# Confidential Information of ARM, Inc.
# Use subject to ARM license.
# Copyright (c) 2022 ARM, Inc.

# ACI Version r1p1

# Reifier 4.0.0

VERSION 5.7 ;

BUSBITCHARS "[]" ;

#name: High Density Single Port Register File RVT RVT Compiler | LOGIC0040LL 40nm Process 0.299um^2 Bit Cell
#version: r1p1
#comment: This is a memory instance
#configuration:  -activity_factor 50 -back_biasing off -bits 16 -bmux off -bus_notation on -check_instname on -diodes on -drive 6 -ema on -frequency 1.0 -instname RAMSP128X16 -left_bus_delim "[" -mux 2 -mvt "" -name_case upper -power_type otc -prefix "" -pwr_gnd_rename vddpe:VDDPE,vddce:VDDCE,vsse:VSSE -retention on -right_bus_delim "]" -ser none -site_def off -top_layer m5-m10 -words 128 -write_mask on -write_thru off -corners ff_1p10v_1p10v_0c,ff_1p10v_1p10v_125c,ff_1p10v_1p10v_m40c,ff_1p21v_1p21v_0c,ff_1p21v_1p21v_125c,ff_1p21v_1p21v_m40c,ff_1p26v_1p26v_0c,ff_1p26v_1p26v_125c,ff_1p26v_1p26v_85c,ff_1p26v_1p26v_m40c,ss_0p90v_0p90v_0c,ss_0p90v_0p90v_125c,ss_0p90v_0p90v_m40c,ss_0p99v_0p99v_0c,ss_0p99v_0p99v_125c,ss_0p99v_0p99v_m40c,ss_1p08v_1p08v_0c,ss_1p08v_1p08v_125c,ss_1p08v_1p08v_m40c,tt_1p00v_1p00v_125c,tt_1p00v_1p00v_25c,tt_1p00v_1p00v_85c,tt_1p10v_1p10v_125c,tt_1p10v_1p10v_25c,tt_1p10v_1p10v_85c,tt_1p20v_1p20v_125c,tt_1p20v_1p20v_25c,tt_1p20v_1p20v_85c
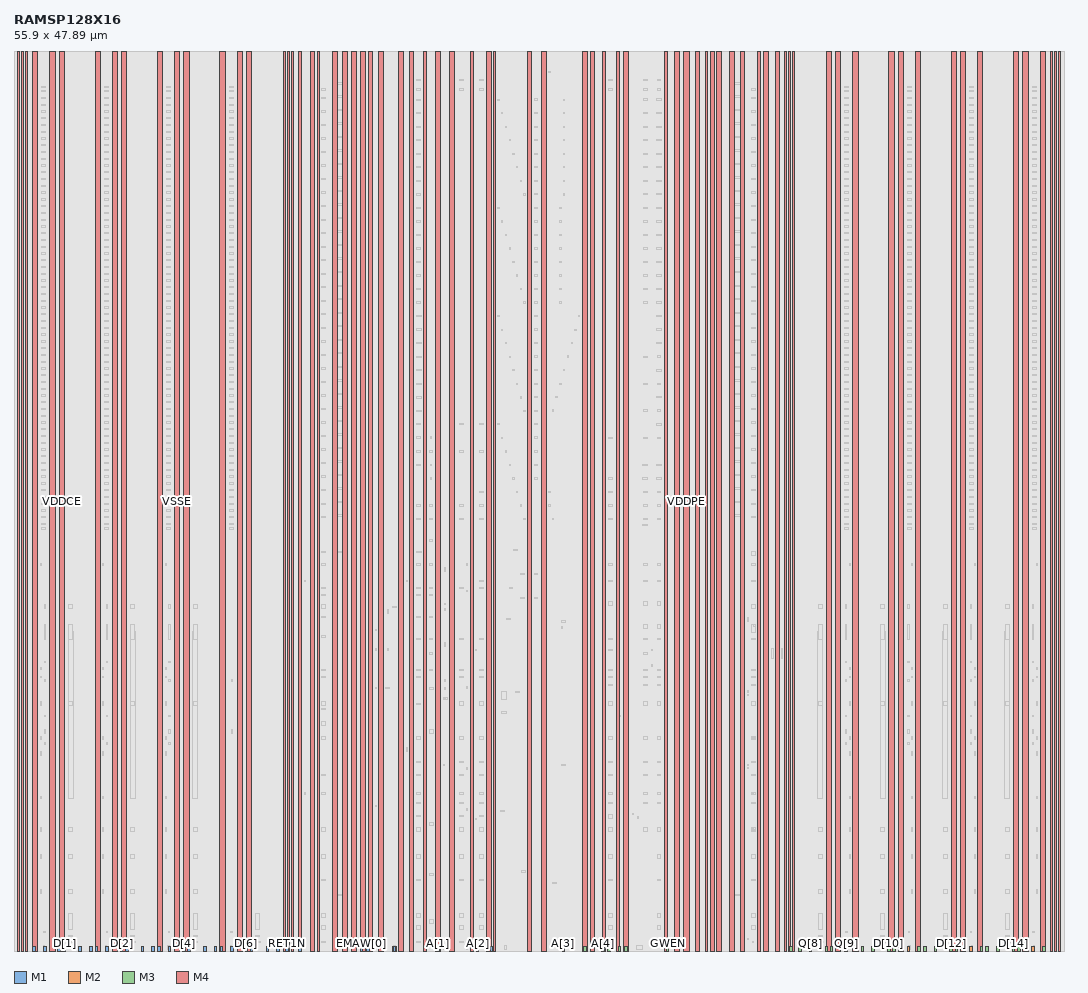
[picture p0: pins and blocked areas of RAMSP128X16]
MACRO RAMSP128X16
  FOREIGN RAMSP128X16 0 0 ;
  SYMMETRY X Y R90 ;
  SIZE 55.9 BY 47.89 ;
  CLASS BLOCK ;
  PIN A[3]
    DIRECTION INPUT ;
    USE SIGNAL ;
    SHAPE ABUTMENT ;
    PORT
      LAYER M1 ;
      RECT 29.175 0.0 29.315 0.25 ;
      LAYER M2 ;
      RECT 29.175 0.0 29.315 0.25 ;
      LAYER M3 ;
      RECT 29.175 0.0 29.315 0.25 ;
      END
    ANTENNAGATEAREA 0.0114 ;
    ANTENNADIFFAREA 0.035 ;
    END A[3]
  PIN A[5]
    DIRECTION INPUT ;
    USE SIGNAL ;
    SHAPE ABUTMENT ;
    PORT
      LAYER M3 ;
      RECT 25.345 0.0 25.485 0.25 ;
      LAYER M2 ;
      RECT 25.345 0.0 25.485 0.25 ;
      LAYER M1 ;
      RECT 25.345 0.0 25.485 0.25 ;
      END
    ANTENNAGATEAREA 0.0114 ;
    ANTENNADIFFAREA 0.035 ;
    END A[5]
  PIN EMA[0]
    DIRECTION INPUT ;
    USE SIGNAL ;
    SHAPE ABUTMENT ;
    PORT
      LAYER M1 ;
      RECT 30.33 0.0 30.47 0.25 ;
      LAYER M2 ;
      RECT 30.33 0.0 30.47 0.25 ;
      LAYER M3 ;
      RECT 30.33 0.0 30.47 0.25 ;
      END
    ANTENNAGATEAREA 0.0114 ;
    ANTENNADIFFAREA 0.035 ;
    END EMA[0]
  PIN A[2]
    DIRECTION INPUT ;
    USE SIGNAL ;
    SHAPE ABUTMENT ;
    PORT
      LAYER M3 ;
      RECT 24.615 0.0 24.755 0.25 ;
      LAYER M2 ;
      RECT 24.615 0.0 24.755 0.25 ;
      LAYER M1 ;
      RECT 24.615 0.0 24.755 0.25 ;
      END
    ANTENNAGATEAREA 0.0114 ;
    ANTENNADIFFAREA 0.035 ;
    END A[2]
  PIN A[4]
    DIRECTION INPUT ;
    USE SIGNAL ;
    SHAPE ABUTMENT ;
    PORT
      LAYER M1 ;
      RECT 31.29 0.0 31.43 0.25 ;
      LAYER M2 ;
      RECT 31.29 0.0 31.43 0.25 ;
      LAYER M3 ;
      RECT 31.29 0.0 31.43 0.25 ;
      END
    ANTENNAGATEAREA 0.0114 ;
    ANTENNADIFFAREA 0.035 ;
    END A[4]
  PIN A[1]
    DIRECTION INPUT ;
    USE SIGNAL ;
    SHAPE ABUTMENT ;
    PORT
      LAYER M3 ;
      RECT 22.52 0.0 22.66 0.25 ;
      LAYER M2 ;
      RECT 22.52 0.0 22.66 0.25 ;
      LAYER M1 ;
      RECT 22.52 0.0 22.66 0.25 ;
      END
    ANTENNAGATEAREA 0.0114 ;
    ANTENNADIFFAREA 0.035 ;
    END A[1]
  PIN A[6]
    DIRECTION INPUT ;
    USE SIGNAL ;
    SHAPE ABUTMENT ;
    PORT
      LAYER M1 ;
      RECT 31.595 0.0 31.735 0.25 ;
      LAYER M2 ;
      RECT 31.595 0.0 31.735 0.25 ;
      LAYER M3 ;
      RECT 31.595 0.0 31.735 0.25 ;
      END
    ANTENNAGATEAREA 0.0114 ;
    ANTENNADIFFAREA 0.035 ;
    END A[6]
  PIN CLK
    DIRECTION INPUT ;
    USE SIGNAL ;
    SHAPE ABUTMENT ;
    PORT
      LAYER M3 ;
      RECT 20.18 0.0 20.32 0.25 ;
      LAYER M2 ;
      RECT 20.18 0.0 20.32 0.25 ;
      LAYER M1 ;
      RECT 20.18 0.0 20.32 0.25 ;
      LAYER M4 ;
      RECT 20.14 0.0 20.35 0.25 ;
      END
    ANTENNAGATEAREA 0.0114 ;
    ANTENNADIFFAREA 0.035 ;
    END CLK
  PIN EMA[1]
    DIRECTION INPUT ;
    USE SIGNAL ;
    SHAPE ABUTMENT ;
    PORT
      LAYER M1 ;
      RECT 32.16 0.0 32.3 0.25 ;
      LAYER M2 ;
      RECT 32.16 0.0 32.3 0.25 ;
      LAYER M3 ;
      RECT 32.16 0.0 32.3 0.25 ;
      END
    ANTENNAGATEAREA 0.0114 ;
    ANTENNADIFFAREA 0.035 ;
    END EMA[1]
  PIN EMAW[1]
    DIRECTION INPUT ;
    USE SIGNAL ;
    SHAPE ABUTMENT ;
    PORT
      LAYER M3 ;
      RECT 18.785 0.0 18.925 0.25 ;
      LAYER M2 ;
      RECT 18.785 0.0 18.925 0.25 ;
      LAYER M1 ;
      RECT 18.785 0.0 18.925 0.25 ;
      END
    ANTENNAGATEAREA 0.0114 ;
    ANTENNADIFFAREA 0.035 ;
    END EMAW[1]
  PIN EMA[2]
    DIRECTION INPUT ;
    USE SIGNAL ;
    SHAPE ABUTMENT ;
    PORT
      LAYER M1 ;
      RECT 32.51 0.0 32.65 0.25 ;
      LAYER M2 ;
      RECT 32.51 0.0 32.65 0.25 ;
      LAYER M3 ;
      RECT 32.51 0.0 32.65 0.25 ;
      END
    ANTENNAGATEAREA 0.0114 ;
    ANTENNADIFFAREA 0.035 ;
    END EMA[2]
  PIN EMAW[0]
    DIRECTION INPUT ;
    USE SIGNAL ;
    SHAPE ABUTMENT ;
    PORT
      LAYER M3 ;
      RECT 18.43 0.0 18.57 0.25 ;
      LAYER M2 ;
      RECT 18.43 0.0 18.57 0.25 ;
      LAYER M1 ;
      RECT 18.43 0.0 18.57 0.25 ;
      END
    ANTENNAGATEAREA 0.0114 ;
    ANTENNADIFFAREA 0.035 ;
    END EMAW[0]
  PIN GWEN
    DIRECTION INPUT ;
    USE SIGNAL ;
    SHAPE ABUTMENT ;
    PORT
      LAYER M1 ;
      RECT 34.73 0.0 34.87 0.25 ;
      LAYER M2 ;
      RECT 34.73 0.0 34.87 0.25 ;
      LAYER M3 ;
      RECT 34.73 0.0 34.87 0.25 ;
      END
    ANTENNAGATEAREA 0.0114 ;
    ANTENNADIFFAREA 0.035 ;
    END GWEN
  PIN CEN
    DIRECTION INPUT ;
    USE SIGNAL ;
    SHAPE ABUTMENT ;
    PORT
      LAYER M3 ;
      RECT 15.17 0.0 15.31 0.25 ;
      LAYER M2 ;
      RECT 15.17 0.0 15.31 0.25 ;
      LAYER M1 ;
      RECT 15.17 0.0 15.31 0.25 ;
      END
    ANTENNAGATEAREA 0.0114 ;
    ANTENNADIFFAREA 0.035 ;
    END CEN
  PIN A[0]
    DIRECTION INPUT ;
    USE SIGNAL ;
    SHAPE ABUTMENT ;
    PORT
      LAYER M1 ;
      RECT 41.28 0.0 41.42 0.25 ;
      LAYER M2 ;
      RECT 41.28 0.0 41.42 0.25 ;
      LAYER M3 ;
      RECT 41.28 0.0 41.42 0.25 ;
      END
    ANTENNAGATEAREA 0.0114 ;
    ANTENNADIFFAREA 0.035 ;
    END A[0]
  PIN RET1N
    DIRECTION INPUT ;
    USE SIGNAL ;
    SHAPE ABUTMENT ;
    PORT
      LAYER M3 ;
      RECT 14.47 0.0 14.61 0.25 ;
      LAYER M2 ;
      RECT 14.47 0.0 14.61 0.25 ;
      LAYER M1 ;
      RECT 14.47 0.0 14.61 0.25 ;
      END
    ANTENNAGATEAREA 0.0114 ;
    ANTENNADIFFAREA 0.035 ;
    END RET1N
  PIN WEN[8]
    DIRECTION INPUT ;
    USE SIGNAL ;
    SHAPE ABUTMENT ;
    PORT
      LAYER M1 ;
      RECT 41.78 0.0 41.92 0.25 ;
      LAYER M2 ;
      RECT 41.78 0.0 41.92 0.25 ;
      LAYER M3 ;
      RECT 41.78 0.0 41.92 0.25 ;
      END
    ANTENNAGATEAREA 0.0114 ;
    ANTENNADIFFAREA 0.035 ;
    END WEN[8]
  PIN WEN[7]
    DIRECTION INPUT ;
    USE SIGNAL ;
    SHAPE ABUTMENT ;
    PORT
      LAYER M3 ;
      RECT 13.98 0.0 14.12 0.25 ;
      LAYER M2 ;
      RECT 13.98 0.0 14.12 0.25 ;
      LAYER M1 ;
      RECT 13.98 0.0 14.12 0.25 ;
      END
    ANTENNAGATEAREA 0.0114 ;
    ANTENNADIFFAREA 0.035 ;
    END WEN[7]
  PIN Q[8]
    DIRECTION OUTPUT ;
    USE SIGNAL ;
    SHAPE ABUTMENT ;
    PORT
      LAYER M1 ;
      RECT 42.34 0.0 42.48 0.25 ;
      LAYER M2 ;
      RECT 42.34 0.0 42.48 0.25 ;
      LAYER M3 ;
      RECT 42.34 0.0 42.48 0.25 ;
      END
    ANTENNADIFFAREA 0.035 ;
    END Q[8]
  PIN Q[7]
    DIRECTION OUTPUT ;
    USE SIGNAL ;
    SHAPE ABUTMENT ;
    PORT
      LAYER M3 ;
      RECT 13.42 0.0 13.56 0.25 ;
      LAYER M2 ;
      RECT 13.42 0.0 13.56 0.25 ;
      LAYER M1 ;
      RECT 13.42 0.0 13.56 0.25 ;
      END
    ANTENNADIFFAREA 0.035 ;
    END Q[7]
  PIN D[8]
    DIRECTION INPUT ;
    USE SIGNAL ;
    SHAPE ABUTMENT ;
    PORT
      LAYER M1 ;
      RECT 43.18 0.0 43.32 0.25 ;
      LAYER M2 ;
      RECT 43.18 0.0 43.32 0.25 ;
      LAYER M3 ;
      RECT 43.18 0.0 43.32 0.25 ;
      END
    ANTENNAGATEAREA 0.0114 ;
    ANTENNADIFFAREA 0.035 ;
    END D[8]
  PIN D[7]
    DIRECTION INPUT ;
    USE SIGNAL ;
    SHAPE ABUTMENT ;
    PORT
      LAYER M3 ;
      RECT 12.58 0.0 12.72 0.25 ;
      LAYER M2 ;
      RECT 12.58 0.0 12.72 0.25 ;
      LAYER M1 ;
      RECT 12.58 0.0 12.72 0.25 ;
      END
    ANTENNAGATEAREA 0.0114 ;
    ANTENNADIFFAREA 0.035 ;
    END D[7]
  PIN D[9]
    DIRECTION INPUT ;
    USE SIGNAL ;
    SHAPE ABUTMENT ;
    PORT
      LAYER M1 ;
      RECT 43.46 0.0 43.6 0.25 ;
      LAYER M2 ;
      RECT 43.46 0.0 43.6 0.25 ;
      LAYER M3 ;
      RECT 43.46 0.0 43.6 0.25 ;
      END
    ANTENNAGATEAREA 0.0114 ;
    ANTENNADIFFAREA 0.035 ;
    END D[9]
  PIN D[6]
    DIRECTION INPUT ;
    USE SIGNAL ;
    SHAPE ABUTMENT ;
    PORT
      LAYER M3 ;
      RECT 12.3 0.0 12.44 0.25 ;
      LAYER M2 ;
      RECT 12.3 0.0 12.44 0.25 ;
      LAYER M1 ;
      RECT 12.3 0.0 12.44 0.25 ;
      END
    ANTENNAGATEAREA 0.0114 ;
    ANTENNADIFFAREA 0.035 ;
    END D[6]
  PIN Q[9]
    DIRECTION OUTPUT ;
    USE SIGNAL ;
    SHAPE ABUTMENT ;
    PORT
      LAYER M1 ;
      RECT 44.23 0.0 44.37 0.25 ;
      LAYER M2 ;
      RECT 44.23 0.0 44.37 0.25 ;
      END
    ANTENNADIFFAREA 0.035 ;
    END Q[9]
  PIN Q[6]
    DIRECTION OUTPUT ;
    USE SIGNAL ;
    SHAPE ABUTMENT ;
    PORT
      LAYER M2 ;
      RECT 11.53 0.0 11.67 0.25 ;
      LAYER M1 ;
      RECT 11.53 0.0 11.67 0.25 ;
      END
    ANTENNADIFFAREA 0.035 ;
    END Q[6]
  PIN WEN[9]
    DIRECTION INPUT ;
    USE SIGNAL ;
    SHAPE ABUTMENT ;
    PORT
      LAYER M1 ;
      RECT 44.79 0.0 44.93 0.25 ;
      LAYER M2 ;
      RECT 44.79 0.0 44.93 0.25 ;
      LAYER M3 ;
      RECT 44.79 0.0 44.93 0.25 ;
      END
    ANTENNAGATEAREA 0.0114 ;
    ANTENNADIFFAREA 0.035 ;
    END WEN[9]
  PIN WEN[6]
    DIRECTION INPUT ;
    USE SIGNAL ;
    SHAPE ABUTMENT ;
    PORT
      LAYER M3 ;
      RECT 10.97 0.0 11.11 0.25 ;
      LAYER M2 ;
      RECT 10.97 0.0 11.11 0.25 ;
      LAYER M1 ;
      RECT 10.97 0.0 11.11 0.25 ;
      END
    ANTENNAGATEAREA 0.0114 ;
    ANTENNADIFFAREA 0.035 ;
    END WEN[6]
  PIN WEN[10]
    DIRECTION INPUT ;
    USE SIGNAL ;
    SHAPE ABUTMENT ;
    PORT
      LAYER M1 ;
      RECT 45.1 0.0 45.24 0.25 ;
      LAYER M2 ;
      RECT 45.1 0.0 45.24 0.25 ;
      LAYER M3 ;
      RECT 45.1 0.0 45.24 0.25 ;
      END
    ANTENNAGATEAREA 0.0114 ;
    ANTENNADIFFAREA 0.035 ;
    END WEN[10]
  PIN WEN[5]
    DIRECTION INPUT ;
    USE SIGNAL ;
    SHAPE ABUTMENT ;
    PORT
      LAYER M3 ;
      RECT 10.66 0.0 10.8 0.25 ;
      LAYER M2 ;
      RECT 10.66 0.0 10.8 0.25 ;
      LAYER M1 ;
      RECT 10.66 0.0 10.8 0.25 ;
      END
    ANTENNAGATEAREA 0.0114 ;
    ANTENNADIFFAREA 0.035 ;
    END WEN[5]
  PIN Q[10]
    DIRECTION OUTPUT ;
    USE SIGNAL ;
    SHAPE ABUTMENT ;
    PORT
      LAYER M1 ;
      RECT 45.66 0.0 45.8 0.25 ;
      LAYER M2 ;
      RECT 45.66 0.0 45.8 0.25 ;
      LAYER M3 ;
      RECT 45.66 0.0 45.8 0.25 ;
      END
    ANTENNADIFFAREA 0.035 ;
    END Q[10]
  PIN Q[5]
    DIRECTION OUTPUT ;
    USE SIGNAL ;
    SHAPE ABUTMENT ;
    PORT
      LAYER M3 ;
      RECT 10.1 0.0 10.24 0.25 ;
      LAYER M2 ;
      RECT 10.1 0.0 10.24 0.25 ;
      LAYER M1 ;
      RECT 10.1 0.0 10.24 0.25 ;
      END
    ANTENNADIFFAREA 0.035 ;
    END Q[5]
  PIN D[10]
    DIRECTION INPUT ;
    USE SIGNAL ;
    SHAPE ABUTMENT ;
    PORT
      LAYER M1 ;
      RECT 46.5 0.0 46.64 0.25 ;
      LAYER M2 ;
      RECT 46.5 0.0 46.64 0.25 ;
      LAYER M3 ;
      RECT 46.5 0.0 46.64 0.25 ;
      END
    ANTENNAGATEAREA 0.0114 ;
    ANTENNADIFFAREA 0.035 ;
    END D[10]
  PIN D[5]
    DIRECTION INPUT ;
    USE SIGNAL ;
    SHAPE ABUTMENT ;
    PORT
      LAYER M3 ;
      RECT 9.26 0.0 9.4 0.25 ;
      LAYER M2 ;
      RECT 9.26 0.0 9.4 0.25 ;
      LAYER M1 ;
      RECT 9.26 0.0 9.4 0.25 ;
      END
    ANTENNAGATEAREA 0.0114 ;
    ANTENNADIFFAREA 0.035 ;
    END D[5]
  PIN D[11]
    DIRECTION INPUT ;
    USE SIGNAL ;
    SHAPE ABUTMENT ;
    PORT
      LAYER M1 ;
      RECT 46.78 0.0 46.92 0.25 ;
      LAYER M2 ;
      RECT 46.78 0.0 46.92 0.25 ;
      LAYER M3 ;
      RECT 46.78 0.0 46.92 0.25 ;
      END
    ANTENNAGATEAREA 0.0114 ;
    ANTENNADIFFAREA 0.035 ;
    END D[11]
  PIN D[4]
    DIRECTION INPUT ;
    USE SIGNAL ;
    SHAPE ABUTMENT ;
    PORT
      LAYER M3 ;
      RECT 8.98 0.0 9.12 0.25 ;
      LAYER M2 ;
      RECT 8.98 0.0 9.12 0.25 ;
      LAYER M1 ;
      RECT 8.98 0.0 9.12 0.25 ;
      END
    ANTENNAGATEAREA 0.0114 ;
    ANTENNADIFFAREA 0.035 ;
    END D[4]
  PIN Q[11]
    DIRECTION OUTPUT ;
    USE SIGNAL ;
    SHAPE ABUTMENT ;
    PORT
      LAYER M1 ;
      RECT 47.55 0.0 47.69 0.25 ;
      LAYER M2 ;
      RECT 47.55 0.0 47.69 0.25 ;
      END
    ANTENNADIFFAREA 0.035 ;
    END Q[11]
  PIN Q[4]
    DIRECTION OUTPUT ;
    USE SIGNAL ;
    SHAPE ABUTMENT ;
    PORT
      LAYER M2 ;
      RECT 8.21 0.0 8.35 0.25 ;
      LAYER M1 ;
      RECT 8.21 0.0 8.35 0.25 ;
      END
    ANTENNADIFFAREA 0.035 ;
    END Q[4]
  PIN WEN[11]
    DIRECTION INPUT ;
    USE SIGNAL ;
    SHAPE ABUTMENT ;
    PORT
      LAYER M1 ;
      RECT 48.11 0.0 48.25 0.25 ;
      LAYER M2 ;
      RECT 48.11 0.0 48.25 0.25 ;
      LAYER M3 ;
      RECT 48.11 0.0 48.25 0.25 ;
      END
    ANTENNAGATEAREA 0.0114 ;
    ANTENNADIFFAREA 0.035 ;
    END WEN[11]
  PIN WEN[4]
    DIRECTION INPUT ;
    USE SIGNAL ;
    SHAPE ABUTMENT ;
    PORT
      LAYER M3 ;
      RECT 7.65 0.0 7.79 0.25 ;
      LAYER M2 ;
      RECT 7.65 0.0 7.79 0.25 ;
      LAYER M1 ;
      RECT 7.65 0.0 7.79 0.25 ;
      END
    ANTENNAGATEAREA 0.0114 ;
    ANTENNADIFFAREA 0.035 ;
    END WEN[4]
  PIN WEN[12]
    DIRECTION INPUT ;
    USE SIGNAL ;
    SHAPE ABUTMENT ;
    PORT
      LAYER M1 ;
      RECT 48.42 0.0 48.56 0.25 ;
      LAYER M2 ;
      RECT 48.42 0.0 48.56 0.25 ;
      LAYER M3 ;
      RECT 48.42 0.0 48.56 0.25 ;
      END
    ANTENNAGATEAREA 0.0114 ;
    ANTENNADIFFAREA 0.035 ;
    END WEN[12]
  PIN WEN[3]
    DIRECTION INPUT ;
    USE SIGNAL ;
    SHAPE ABUTMENT ;
    PORT
      LAYER M3 ;
      RECT 7.34 0.0 7.48 0.25 ;
      LAYER M2 ;
      RECT 7.34 0.0 7.48 0.25 ;
      LAYER M1 ;
      RECT 7.34 0.0 7.48 0.25 ;
      END
    ANTENNAGATEAREA 0.0114 ;
    ANTENNADIFFAREA 0.035 ;
    END WEN[3]
  PIN Q[12]
    DIRECTION OUTPUT ;
    USE SIGNAL ;
    SHAPE ABUTMENT ;
    PORT
      LAYER M1 ;
      RECT 48.98 0.0 49.12 0.25 ;
      LAYER M2 ;
      RECT 48.98 0.0 49.12 0.25 ;
      LAYER M3 ;
      RECT 48.98 0.0 49.12 0.25 ;
      END
    ANTENNADIFFAREA 0.035 ;
    END Q[12]
  PIN Q[3]
    DIRECTION OUTPUT ;
    USE SIGNAL ;
    SHAPE ABUTMENT ;
    PORT
      LAYER M3 ;
      RECT 6.78 0.0 6.92 0.25 ;
      LAYER M2 ;
      RECT 6.78 0.0 6.92 0.25 ;
      LAYER M1 ;
      RECT 6.78 0.0 6.92 0.25 ;
      END
    ANTENNADIFFAREA 0.035 ;
    END Q[3]
  PIN D[12]
    DIRECTION INPUT ;
    USE SIGNAL ;
    SHAPE ABUTMENT ;
    PORT
      LAYER M1 ;
      RECT 49.82 0.0 49.96 0.25 ;
      LAYER M2 ;
      RECT 49.82 0.0 49.96 0.25 ;
      LAYER M3 ;
      RECT 49.82 0.0 49.96 0.25 ;
      END
    ANTENNAGATEAREA 0.0114 ;
    ANTENNADIFFAREA 0.035 ;
    END D[12]
  PIN D[3]
    DIRECTION INPUT ;
    USE SIGNAL ;
    SHAPE ABUTMENT ;
    PORT
      LAYER M3 ;
      RECT 5.94 0.0 6.08 0.25 ;
      LAYER M2 ;
      RECT 5.94 0.0 6.08 0.25 ;
      LAYER M1 ;
      RECT 5.94 0.0 6.08 0.25 ;
      END
    ANTENNAGATEAREA 0.0114 ;
    ANTENNADIFFAREA 0.035 ;
    END D[3]
  PIN D[13]
    DIRECTION INPUT ;
    USE SIGNAL ;
    SHAPE ABUTMENT ;
    PORT
      LAYER M1 ;
      RECT 50.1 0.0 50.24 0.25 ;
      LAYER M2 ;
      RECT 50.1 0.0 50.24 0.25 ;
      LAYER M3 ;
      RECT 50.1 0.0 50.24 0.25 ;
      END
    ANTENNAGATEAREA 0.0114 ;
    ANTENNADIFFAREA 0.035 ;
    END D[13]
  PIN D[2]
    DIRECTION INPUT ;
    USE SIGNAL ;
    SHAPE ABUTMENT ;
    PORT
      LAYER M3 ;
      RECT 5.66 0.0 5.8 0.25 ;
      LAYER M2 ;
      RECT 5.66 0.0 5.8 0.25 ;
      LAYER M1 ;
      RECT 5.66 0.0 5.8 0.25 ;
      END
    ANTENNAGATEAREA 0.0114 ;
    ANTENNADIFFAREA 0.035 ;
    END D[2]
  PIN Q[13]
    DIRECTION OUTPUT ;
    USE SIGNAL ;
    SHAPE ABUTMENT ;
    PORT
      LAYER M1 ;
      RECT 50.87 0.0 51.01 0.25 ;
      LAYER M2 ;
      RECT 50.87 0.0 51.01 0.25 ;
      END
    ANTENNADIFFAREA 0.035 ;
    END Q[13]
  PIN Q[2]
    DIRECTION OUTPUT ;
    USE SIGNAL ;
    SHAPE ABUTMENT ;
    PORT
      LAYER M2 ;
      RECT 4.89 0.0 5.03 0.25 ;
      LAYER M1 ;
      RECT 4.89 0.0 5.03 0.25 ;
      END
    ANTENNADIFFAREA 0.035 ;
    END Q[2]
  PIN WEN[13]
    DIRECTION INPUT ;
    USE SIGNAL ;
    SHAPE ABUTMENT ;
    PORT
      LAYER M1 ;
      RECT 51.43 0.0 51.57 0.25 ;
      LAYER M2 ;
      RECT 51.43 0.0 51.57 0.25 ;
      LAYER M3 ;
      RECT 51.43 0.0 51.57 0.25 ;
      END
    ANTENNAGATEAREA 0.0114 ;
    ANTENNADIFFAREA 0.035 ;
    END WEN[13]
  PIN WEN[2]
    DIRECTION INPUT ;
    USE SIGNAL ;
    SHAPE ABUTMENT ;
    PORT
      LAYER M3 ;
      RECT 4.33 0.0 4.47 0.25 ;
      LAYER M2 ;
      RECT 4.33 0.0 4.47 0.25 ;
      LAYER M1 ;
      RECT 4.33 0.0 4.47 0.25 ;
      END
    ANTENNAGATEAREA 0.0114 ;
    ANTENNADIFFAREA 0.035 ;
    END WEN[2]
  PIN WEN[14]
    DIRECTION INPUT ;
    USE SIGNAL ;
    SHAPE ABUTMENT ;
    PORT
      LAYER M1 ;
      RECT 51.74 0.0 51.88 0.25 ;
      LAYER M2 ;
      RECT 51.74 0.0 51.88 0.25 ;
      LAYER M3 ;
      RECT 51.74 0.0 51.88 0.25 ;
      END
    ANTENNAGATEAREA 0.0114 ;
    ANTENNADIFFAREA 0.035 ;
    END WEN[14]
  PIN WEN[1]
    DIRECTION INPUT ;
    USE SIGNAL ;
    SHAPE ABUTMENT ;
    PORT
      LAYER M3 ;
      RECT 4.02 0.0 4.16 0.25 ;
      LAYER M2 ;
      RECT 4.02 0.0 4.16 0.25 ;
      LAYER M1 ;
      RECT 4.02 0.0 4.16 0.25 ;
      END
    ANTENNAGATEAREA 0.0114 ;
    ANTENNADIFFAREA 0.035 ;
    END WEN[1]
  PIN Q[14]
    DIRECTION OUTPUT ;
    USE SIGNAL ;
    SHAPE ABUTMENT ;
    PORT
      LAYER M1 ;
      RECT 52.3 0.0 52.44 0.25 ;
      LAYER M2 ;
      RECT 52.3 0.0 52.44 0.25 ;
      LAYER M3 ;
      RECT 52.3 0.0 52.44 0.25 ;
      END
    ANTENNADIFFAREA 0.035 ;
    END Q[14]
  PIN Q[1]
    DIRECTION OUTPUT ;
    USE SIGNAL ;
    SHAPE ABUTMENT ;
    PORT
      LAYER M3 ;
      RECT 3.46 0.0 3.6 0.25 ;
      LAYER M2 ;
      RECT 3.46 0.0 3.6 0.25 ;
      LAYER M1 ;
      RECT 3.46 0.0 3.6 0.25 ;
      END
    ANTENNADIFFAREA 0.035 ;
    END Q[1]
  PIN D[14]
    DIRECTION INPUT ;
    USE SIGNAL ;
    SHAPE ABUTMENT ;
    PORT
      LAYER M1 ;
      RECT 53.14 0.0 53.28 0.25 ;
      LAYER M2 ;
      RECT 53.14 0.0 53.28 0.25 ;
      LAYER M3 ;
      RECT 53.14 0.0 53.28 0.25 ;
      END
    ANTENNAGATEAREA 0.0114 ;
    ANTENNADIFFAREA 0.035 ;
    END D[14]
  PIN D[1]
    DIRECTION INPUT ;
    USE SIGNAL ;
    SHAPE ABUTMENT ;
    PORT
      LAYER M3 ;
      RECT 2.62 0.0 2.76 0.25 ;
      LAYER M2 ;
      RECT 2.62 0.0 2.76 0.25 ;
      LAYER M1 ;
      RECT 2.62 0.0 2.76 0.25 ;
      END
    ANTENNAGATEAREA 0.0114 ;
    ANTENNADIFFAREA 0.035 ;
    END D[1]
  PIN D[15]
    DIRECTION INPUT ;
    USE SIGNAL ;
    SHAPE ABUTMENT ;
    PORT
      LAYER M1 ;
      RECT 53.42 0.0 53.56 0.25 ;
      LAYER M2 ;
      RECT 53.42 0.0 53.56 0.25 ;
      LAYER M3 ;
      RECT 53.42 0.0 53.56 0.25 ;
      END
    ANTENNAGATEAREA 0.0114 ;
    ANTENNADIFFAREA 0.035 ;
    END D[15]
  PIN D[0]
    DIRECTION INPUT ;
    USE SIGNAL ;
    SHAPE ABUTMENT ;
    PORT
      LAYER M3 ;
      RECT 2.34 0.0 2.48 0.25 ;
      LAYER M2 ;
      RECT 2.34 0.0 2.48 0.25 ;
      LAYER M1 ;
      RECT 2.34 0.0 2.48 0.25 ;
      END
    ANTENNAGATEAREA 0.0114 ;
    ANTENNADIFFAREA 0.035 ;
    END D[0]
  PIN Q[15]
    DIRECTION OUTPUT ;
    USE SIGNAL ;
    SHAPE ABUTMENT ;
    PORT
      LAYER M1 ;
      RECT 54.19 0.0 54.33 0.25 ;
      LAYER M2 ;
      RECT 54.19 0.0 54.33 0.25 ;
      END
    ANTENNADIFFAREA 0.035 ;
    END Q[15]
  PIN Q[0]
    DIRECTION OUTPUT ;
    USE SIGNAL ;
    SHAPE ABUTMENT ;
    PORT
      LAYER M2 ;
      RECT 1.57 0.0 1.71 0.25 ;
      LAYER M1 ;
      RECT 1.57 0.0 1.71 0.25 ;
      END
    ANTENNADIFFAREA 0.035 ;
    END Q[0]
  PIN WEN[15]
    DIRECTION INPUT ;
    USE SIGNAL ;
    SHAPE ABUTMENT ;
    PORT
      LAYER M1 ;
      RECT 54.75 0.0 54.89 0.25 ;
      LAYER M2 ;
      RECT 54.75 0.0 54.89 0.25 ;
      LAYER M3 ;
      RECT 54.75 0.0 54.89 0.25 ;
      END
    ANTENNAGATEAREA 0.0114 ;
    ANTENNADIFFAREA 0.035 ;
    END WEN[15]
  PIN WEN[0]
    DIRECTION INPUT ;
    USE SIGNAL ;
    SHAPE ABUTMENT ;
    PORT
      LAYER M3 ;
      RECT 1.01 0.0 1.15 0.25 ;
      LAYER M2 ;
      RECT 1.01 0.0 1.15 0.25 ;
      LAYER M1 ;
      RECT 1.01 0.0 1.15 0.25 ;
      END
    ANTENNAGATEAREA 0.0114 ;
    ANTENNADIFFAREA 0.035 ;
    END WEN[0]
  PIN VDDPE
    DIRECTION INOUT ;
    USE POWER ;
    PORT
      LAYER M4 ;
      RECT 0.59 0.0 0.7 47.89 ;
      END
    PORT
      LAYER M4 ;
      RECT 0.995 0.0 1.275 47.89 ;
      END
    PORT
      LAYER M4 ;
      RECT 4.315 0.0 4.595 47.89 ;
      END
    PORT
      LAYER M4 ;
      RECT 7.635 0.0 7.915 47.89 ;
      END
    PORT
      LAYER M4 ;
      RECT 10.955 0.0 11.235 47.89 ;
      END
    PORT
      LAYER M4 ;
      RECT 14.355 0.0 14.465 47.89 ;
      END
    PORT
      LAYER M4 ;
      RECT 16.135 0.0 16.245 47.89 ;
      END
    PORT
      LAYER M4 ;
      RECT 18.44 0.0 18.72 47.89 ;
      END
    PORT
      LAYER M4 ;
      RECT 21.08 0.0 21.29 47.89 ;
      END
    PORT
      LAYER M4 ;
      RECT 21.825 0.0 21.975 47.89 ;
      END
    PORT
      LAYER M4 ;
      RECT 22.465 0.0 22.695 47.89 ;
      END
    PORT
      LAYER M4 ;
      RECT 23.175 0.0 23.445 47.89 ;
      END
    PORT
      LAYER M4 ;
      RECT 25.145 0.0 25.415 47.89 ;
      END
    PORT
      LAYER M4 ;
      RECT 27.335 0.0 27.545 47.89 ;
      END
    PORT
      LAYER M4 ;
      RECT 30.26 0.0 30.54 47.89 ;
      END
    PORT
      LAYER M4 ;
      RECT 31.35 0.0 31.49 47.89 ;
      END
    PORT
      LAYER M4 ;
      RECT 32.09 0.0 32.24 47.89 ;
      END
    PORT
      LAYER M4 ;
      RECT 32.45 0.0 32.72 47.89 ;
      END
    PORT
      LAYER M4 ;
      RECT 35.66 0.0 35.94 47.89 ;
      END
    PORT
      LAYER M4 ;
      RECT 37.07 0.0 37.28 47.89 ;
      END
    PORT
      LAYER M4 ;
      RECT 39.595 0.0 39.735 47.89 ;
      END
    PORT
      LAYER M4 ;
      RECT 40.525 0.0 40.735 47.89 ;
      END
    PORT
      LAYER M4 ;
      RECT 41.435 0.0 41.545 47.89 ;
      END
    PORT
      LAYER M4 ;
      RECT 44.665 0.0 44.945 47.89 ;
      END
    PORT
      LAYER M4 ;
      RECT 47.985 0.0 48.265 47.89 ;
      END
    PORT
      LAYER M4 ;
      RECT 51.305 0.0 51.585 47.89 ;
      END
    PORT
      LAYER M4 ;
      RECT 54.625 0.0 54.905 47.89 ;
      END
    PORT
      LAYER M4 ;
      RECT 55.2 0.0 55.31 47.89 ;
      END
    END VDDPE
  PIN VDDCE
    DIRECTION INOUT ;
    USE POWER ;
    PORT
      LAYER M4 ;
      RECT 0.17 0.0 0.28 47.89 ;
      END
    PORT
      LAYER M4 ;
      RECT 2.405 0.0 2.685 47.89 ;
      END
    PORT
      LAYER M4 ;
      RECT 5.725 0.0 6.005 47.89 ;
      END
    PORT
      LAYER M4 ;
      RECT 9.045 0.0 9.325 47.89 ;
      END
    PORT
      LAYER M4 ;
      RECT 12.365 0.0 12.645 47.89 ;
      END
    PORT
      LAYER M4 ;
      RECT 14.775 0.0 14.885 47.89 ;
      END
    PORT
      LAYER M4 ;
      RECT 16.965 0.0 17.235 47.89 ;
      END
    PORT
      LAYER M4 ;
      RECT 17.495 0.0 17.765 47.89 ;
      END
    PORT
      LAYER M4 ;
      RECT 19.405 0.0 19.665 47.89 ;
      END
    PORT
      LAYER M4 ;
      RECT 36.27 0.0 36.48 47.89 ;
      END
    PORT
      LAYER M4 ;
      RECT 38.075 0.0 38.345 47.89 ;
      END
    PORT
      LAYER M4 ;
      RECT 38.685 0.0 38.895 47.89 ;
      END
    PORT
      LAYER M4 ;
      RECT 41.015 0.0 41.125 47.89 ;
      END
    PORT
      LAYER M4 ;
      RECT 43.255 0.0 43.535 47.89 ;
      END
    PORT
      LAYER M4 ;
      RECT 46.575 0.0 46.855 47.89 ;
      END
    PORT
      LAYER M4 ;
      RECT 49.895 0.0 50.175 47.89 ;
      END
    PORT
      LAYER M4 ;
      RECT 53.215 0.0 53.495 47.89 ;
      END
    PORT
      LAYER M4 ;
      RECT 55.62 0.0 55.73 47.89 ;
      END
    END VDDCE
  PIN VSSE
    DIRECTION INOUT ;
    USE GROUND ;
    PORT
      LAYER M4 ;
      RECT 0.38 0.0 0.49 47.89 ;
      END
    PORT
      LAYER M4 ;
      RECT 1.915 0.0 2.195 47.89 ;
      END
    PORT
      LAYER M4 ;
      RECT 5.235 0.0 5.515 47.89 ;
      END
    PORT
      LAYER M4 ;
      RECT 8.555 0.0 8.835 47.89 ;
      END
    PORT
      LAYER M4 ;
      RECT 11.875 0.0 12.155 47.89 ;
      END
    PORT
      LAYER M4 ;
      RECT 14.565 0.0 14.675 47.89 ;
      END
    PORT
      LAYER M4 ;
      RECT 15.16 0.0 15.31 47.89 ;
      END
    PORT
      LAYER M4 ;
      RECT 15.8 0.0 16.01 47.89 ;
      END
    PORT
      LAYER M4 ;
      RECT 17.98 0.0 18.26 47.89 ;
      END
    PORT
      LAYER M4 ;
      RECT 18.87 0.0 19.08 47.89 ;
      END
    PORT
      LAYER M4 ;
      RECT 20.49 0.0 20.76 47.89 ;
      END
    PORT
      LAYER M4 ;
      RECT 24.315 0.0 24.465 47.89 ;
      END
    PORT
      LAYER M4 ;
      RECT 25.535 0.0 25.645 47.89 ;
      END
    PORT
      LAYER M4 ;
      RECT 28.065 0.0 28.345 47.89 ;
      END
    PORT
      LAYER M4 ;
      RECT 30.68 0.0 30.89 47.89 ;
      END
    PORT
      LAYER M4 ;
      RECT 34.615 0.0 34.765 47.89 ;
      END
    PORT
      LAYER M4 ;
      RECT 35.14 0.0 35.42 47.89 ;
      END
    PORT
      LAYER M4 ;
      RECT 36.79 0.0 36.93 47.89 ;
      END
    PORT
      LAYER M4 ;
      RECT 37.42 0.0 37.69 47.89 ;
      END
    PORT
      LAYER M4 ;
      RECT 39.885 0.0 40.165 47.89 ;
      END
    PORT
      LAYER M4 ;
      RECT 41.225 0.0 41.335 47.89 ;
      END
    PORT
      LAYER M4 ;
      RECT 43.745 0.0 44.025 47.89 ;
      END
    PORT
      LAYER M4 ;
      RECT 47.065 0.0 47.345 47.89 ;
      END
    PORT
      LAYER M4 ;
      RECT 50.385 0.0 50.665 47.89 ;
      END
    PORT
      LAYER M4 ;
      RECT 53.705 0.0 53.985 47.89 ;
      END
    PORT
      LAYER M4 ;
      RECT 55.41 0.0 55.52 47.89 ;
      END
    END VSSE
  OBS
    #otc obstructions
    LAYER M1 DESIGNRULEWIDTH 0.07 ;
    RECT 55.03 0.0 55.9 0.32 ;
    RECT 54.47 0.0 54.61 0.32 ;
    RECT 53.7 0.0 54.05 0.32 ;
    RECT 52.58 0.0 53.0 0.32 ;
    RECT 52.02 0.0 52.16 0.32 ;
    RECT 51.15 0.0 51.29 0.32 ;
    RECT 50.38 0.0 50.73 0.32 ;
    RECT 49.26 0.0 49.68 0.32 ;
    RECT 48.7 0.0 48.84 0.32 ;
    RECT 47.83 0.0 47.97 0.32 ;
    RECT 47.06 0.0 47.41 0.32 ;
    RECT 45.94 0.0 46.36 0.32 ;
    RECT 45.38 0.0 45.52 0.32 ;
    RECT 44.51 0.0 44.65 0.32 ;
    RECT 43.74 0.0 44.09 0.32 ;
    RECT 42.62 0.0 43.04 0.32 ;
    RECT 42.06 0.0 42.2 0.32 ;
    RECT 41.56 0.0 41.64 0.32 ;
    RECT 35.01 0.0 41.14 0.32 ;
    RECT 32.79 0.0 34.59 0.32 ;
    RECT 31.875 0.0 32.02 0.32 ;
    RECT 30.61 0.0 31.15 0.32 ;
    RECT 29.455 0.0 30.19 0.32 ;
    RECT 25.625 0.0 29.035 0.32 ;
    RECT 24.895 0.0 25.205 0.32 ;
    RECT 22.8 0.0 24.475 0.32 ;
    RECT 20.46 0.0 22.38 0.32 ;
    RECT 19.065 0.0 20.04 0.32 ;
    RECT 15.45 0.0 18.29 0.32 ;
    RECT 14.75 0.0 15.03 0.32 ;
    RECT 14.26 0.0 14.33 0.32 ;
    RECT 13.7 0.0 13.84 0.32 ;
    RECT 12.86 0.0 13.28 0.32 ;
    RECT 11.81 0.0 12.16 0.32 ;
    RECT 11.25 0.0 11.39 0.32 ;
    RECT 10.38 0.0 10.52 0.32 ;
    RECT 9.54 0.0 9.96 0.32 ;
    RECT 8.49 0.0 8.84 0.32 ;
    RECT 7.93 0.0 8.07 0.32 ;
    RECT 7.06 0.0 7.2 0.32 ;
    RECT 6.22 0.0 6.64 0.32 ;
    RECT 5.17 0.0 5.52 0.32 ;
    RECT 4.61 0.0 4.75 0.32 ;
    RECT 3.74 0.0 3.88 0.32 ;
    RECT 2.9 0.0 3.32 0.32 ;
    RECT 1.85 0.0 2.2 0.32 ;
    RECT 1.29 0.0 1.43 0.32 ;
    RECT 0.0 0.0 0.87 0.32 ;
    RECT 0.0 0.32 55.9 47.89 ;
    LAYER V1 ;
    RECT 0.0 0.0 55.9 47.89 ;
    LAYER M2 DESIGNRULEWIDTH 0.07 ;
    RECT 55.03 0.0 55.9 0.32 ;
    RECT 54.47 0.0 54.61 0.32 ;
    RECT 53.7 0.0 54.05 0.32 ;
    RECT 52.58 0.0 53.0 0.32 ;
    RECT 52.02 0.0 52.16 0.32 ;
    RECT 51.15 0.0 51.29 0.32 ;
    RECT 50.38 0.0 50.73 0.32 ;
    RECT 49.26 0.0 49.68 0.32 ;
    RECT 48.7 0.0 48.84 0.32 ;
    RECT 47.83 0.0 47.97 0.32 ;
    RECT 47.06 0.0 47.41 0.32 ;
    RECT 45.94 0.0 46.36 0.32 ;
    RECT 45.38 0.0 45.52 0.32 ;
    RECT 44.51 0.0 44.65 0.32 ;
    RECT 43.74 0.0 44.09 0.32 ;
    RECT 42.62 0.0 43.04 0.32 ;
    RECT 42.06 0.0 42.2 0.32 ;
    RECT 41.56 0.0 41.64 0.32 ;
    RECT 35.01 0.0 41.14 0.32 ;
    RECT 32.79 0.0 34.59 0.32 ;
    RECT 31.875 0.0 32.02 0.32 ;
    RECT 30.61 0.0 31.15 0.32 ;
    RECT 29.455 0.0 30.19 0.32 ;
    RECT 25.625 0.0 29.035 0.32 ;
    RECT 24.895 0.0 25.205 0.32 ;
    RECT 22.8 0.0 24.475 0.32 ;
    RECT 20.46 0.0 22.38 0.32 ;
    RECT 19.065 0.0 20.04 0.32 ;
    RECT 15.45 0.0 18.29 0.32 ;
    RECT 14.75 0.0 15.03 0.32 ;
    RECT 14.26 0.0 14.33 0.32 ;
    RECT 13.7 0.0 13.84 0.32 ;
    RECT 12.86 0.0 13.28 0.32 ;
    RECT 11.81 0.0 12.16 0.32 ;
    RECT 11.25 0.0 11.39 0.32 ;
    RECT 10.38 0.0 10.52 0.32 ;
    RECT 9.54 0.0 9.96 0.32 ;
    RECT 8.49 0.0 8.84 0.32 ;
    RECT 7.93 0.0 8.07 0.32 ;
    RECT 7.06 0.0 7.2 0.32 ;
    RECT 6.22 0.0 6.64 0.32 ;
    RECT 5.17 0.0 5.52 0.32 ;
    RECT 4.61 0.0 4.75 0.32 ;
    RECT 3.74 0.0 3.88 0.32 ;
    RECT 2.9 0.0 3.32 0.32 ;
    RECT 1.85 0.0 2.2 0.32 ;
    RECT 1.29 0.0 1.43 0.32 ;
    RECT 0.0 0.0 0.87 0.32 ;
    RECT 0.0 0.32 55.9 47.89 ;
    LAYER V2 ;
    RECT 0.0 0.0 55.9 47.89 ;
    LAYER M3 DESIGNRULEWIDTH 0.07 ;
    RECT 55.03 0.0 55.9 0.32 ;
    RECT 53.7 0.0 54.61 0.32 ;
    RECT 52.58 0.0 53.0 0.32 ;
    RECT 52.02 0.0 52.16 0.32 ;
    RECT 50.38 0.0 51.29 0.32 ;
    RECT 49.26 0.0 49.68 0.32 ;
    RECT 48.7 0.0 48.84 0.32 ;
    RECT 47.06 0.0 47.97 0.32 ;
    RECT 45.94 0.0 46.36 0.32 ;
    RECT 45.38 0.0 45.52 0.32 ;
    RECT 43.74 0.0 44.65 0.32 ;
    RECT 42.62 0.0 43.04 0.32 ;
    RECT 42.06 0.0 42.2 0.32 ;
    RECT 41.56 0.0 41.64 0.32 ;
    RECT 35.01 0.0 41.14 0.32 ;
    RECT 32.79 0.0 34.59 0.32 ;
    RECT 31.875 0.0 32.02 0.32 ;
    RECT 30.61 0.0 31.15 0.32 ;
    RECT 29.455 0.0 30.19 0.32 ;
    RECT 25.625 0.0 29.035 0.32 ;
    RECT 24.895 0.0 25.205 0.32 ;
    RECT 22.8 0.0 24.475 0.32 ;
    RECT 20.46 0.0 22.38 0.32 ;
    RECT 19.065 0.0 20.04 0.32 ;
    RECT 15.45 0.0 18.29 0.32 ;
    RECT 14.75 0.0 15.03 0.32 ;
    RECT 14.26 0.0 14.33 0.32 ;
    RECT 13.7 0.0 13.84 0.32 ;
    RECT 12.86 0.0 13.28 0.32 ;
    RECT 11.25 0.0 12.16 0.32 ;
    RECT 10.38 0.0 10.52 0.32 ;
    RECT 9.54 0.0 9.96 0.32 ;
    RECT 7.93 0.0 8.84 0.32 ;
    RECT 7.06 0.0 7.2 0.32 ;
    RECT 6.22 0.0 6.64 0.32 ;
    RECT 4.61 0.0 5.52 0.32 ;
    RECT 3.74 0.0 3.88 0.32 ;
    RECT 2.9 0.0 3.32 0.32 ;
    RECT 1.29 0.0 2.2 0.32 ;
    RECT 0.0 0.0 0.87 0.32 ;
    RECT 0.0 0.32 55.9 47.89 ;
    LAYER V3 ;
    RECT 0.0 0.0 55.9 47.89 ;
    LAYER V3 ;
    RECT 11.515 0.06 11.585 0.27 ;
    RECT 11.515 0.06 11.585 0.27 ;
    RECT 12.825 0.435 13.105 0.505 ;
    RECT 11.91 0.432 12.12 0.502 ;
    RECT 54.275 0.06 54.345 0.27 ;
    RECT 54.275 0.06 54.345 0.27 ;
    RECT 52.755 0.435 53.035 0.505 ;
    RECT 53.74 0.432 53.95 0.502 ;
    RECT 8.195 0.06 8.265 0.27 ;
    RECT 8.195 0.06 8.265 0.27 ;
    RECT 9.505 0.435 9.785 0.505 ;
    RECT 8.59 0.432 8.8 0.502 ;
    RECT 50.955 0.06 51.025 0.27 ;
    RECT 50.955 0.06 51.025 0.27 ;
    RECT 49.435 0.435 49.715 0.505 ;
    RECT 50.42 0.432 50.63 0.502 ;
    RECT 4.875 0.06 4.945 0.27 ;
    RECT 4.875 0.06 4.945 0.27 ;
    RECT 6.185 0.435 6.465 0.505 ;
    RECT 5.27 0.432 5.48 0.502 ;
    RECT 47.635 0.06 47.705 0.27 ;
    RECT 47.635 0.06 47.705 0.27 ;
    RECT 46.115 0.435 46.395 0.505 ;
    RECT 47.1 0.432 47.31 0.502 ;
    RECT 1.555 0.06 1.625 0.27 ;
    RECT 1.555 0.06 1.625 0.27 ;
    RECT 2.865 0.435 3.145 0.505 ;
    RECT 1.95 0.432 2.16 0.502 ;
    RECT 44.315 0.06 44.385 0.27 ;
    RECT 44.315 0.06 44.385 0.27 ;
    RECT 42.795 0.435 43.075 0.505 ;
    RECT 43.78 0.432 43.99 0.502 ;
    RECT 16.395 0.43 16.605 0.5 ;
    RECT 20.215 0.06 20.285 0.27 ;
    RECT 21.45 0.435 21.66 0.505 ;
    RECT 22.88 0.06 22.95 0.27 ;
    RECT 23.73 0.435 23.94 0.505 ;
    RECT 24.075 0.06 24.145 0.27 ;
    RECT 24.76 0.435 24.97 0.505 ;
    RECT 26.13 0.06 26.2 0.27 ;
    RECT 31.66 0.45 31.87 0.52 ;
    RECT 33.115 0.06 33.47 0.27 ;
    RECT 34.235 0.435 34.445 0.505 ;
    RECT 39.04 0.605 39.11 0.675 ;
    RECT 39.3 0.435 39.37 0.505 ;
    RECT 44.24 45.02 44.45 45.09 ;
    RECT 44.24 45.38 44.45 45.45 ;
    RECT 44.24 45.74 44.45 45.81 ;
    RECT 43.78 45.02 43.99 45.09 ;
    RECT 43.78 45.38 43.99 45.45 ;
    RECT 43.78 45.74 43.99 45.81 ;
    RECT 41.245 45.38 41.315 45.45 ;
    RECT 55.43 45.38 55.5 45.45 ;
    RECT 54.2 45.02 54.41 45.09 ;
    RECT 54.2 45.38 54.41 45.45 ;
    RECT 54.2 45.74 54.41 45.81 ;
    RECT 53.74 45.02 53.95 45.09 ;
    RECT 53.74 45.38 53.95 45.45 ;
    RECT 53.74 45.74 53.95 45.81 ;
    RECT 50.88 45.02 51.09 45.09 ;
    RECT 50.88 45.38 51.09 45.45 ;
    RECT 50.88 45.74 51.09 45.81 ;
    RECT 50.42 45.02 50.63 45.09 ;
    RECT 50.42 45.38 50.63 45.45 ;
    RECT 50.42 45.74 50.63 45.81 ;
    RECT 47.56 45.02 47.77 45.09 ;
    RECT 47.56 45.38 47.77 45.45 ;
    RECT 47.56 45.74 47.77 45.81 ;
    RECT 47.1 45.02 47.31 45.09 ;
    RECT 47.1 45.38 47.31 45.45 ;
    RECT 47.1 45.74 47.31 45.81 ;
    RECT 44.24 34.22 44.45 34.29 ;
    RECT 44.24 34.58 44.45 34.65 ;
    RECT 44.24 34.94 44.45 35.01 ;
    RECT 43.78 34.22 43.99 34.29 ;
    RECT 43.78 34.58 43.99 34.65 ;
    RECT 43.78 34.94 43.99 35.01 ;
    RECT 41.245 34.58 41.315 34.65 ;
    RECT 54.2 34.22 54.41 34.29 ;
    RECT 54.2 34.58 54.41 34.65 ;
    RECT 54.2 34.94 54.41 35.01 ;
    RECT 53.74 34.22 53.95 34.29 ;
    RECT 53.74 34.58 53.95 34.65 ;
    RECT 53.74 34.94 53.95 35.01 ;
    RECT 50.88 34.22 51.09 34.29 ;
    RECT 50.88 34.58 51.09 34.65 ;
    RECT 50.88 34.94 51.09 35.01 ;
    RECT 50.42 34.22 50.63 34.29 ;
    RECT 50.42 34.58 50.63 34.65 ;
    RECT 50.42 34.94 50.63 35.01 ;
    RECT 55.43 34.58 55.5 34.65 ;
    RECT 47.56 34.22 47.77 34.29 ;
    RECT 47.56 34.58 47.77 34.65 ;
    RECT 47.56 34.94 47.77 35.01 ;
    RECT 47.1 34.22 47.31 34.29 ;
    RECT 47.1 34.58 47.31 34.65 ;
    RECT 47.1 34.94 47.31 35.01 ;
    RECT 44.24 44.3 44.45 44.37 ;
    RECT 44.24 44.66 44.45 44.73 ;
    RECT 44.24 45.02 44.45 45.09 ;
    RECT 43.78 44.3 43.99 44.37 ;
    RECT 43.78 44.66 43.99 44.73 ;
    RECT 43.78 45.02 43.99 45.09 ;
    RECT 41.245 44.66 41.315 44.73 ;
    RECT 55.43 44.66 55.5 44.73 ;
    RECT 54.2 44.3 54.41 44.37 ;
    RECT 54.2 44.66 54.41 44.73 ;
    RECT 54.2 45.02 54.41 45.09 ;
    RECT 53.74 44.3 53.95 44.37 ;
    RECT 53.74 44.66 53.95 44.73 ;
    RECT 53.74 45.02 53.95 45.09 ;
    RECT 50.88 44.3 51.09 44.37 ;
    RECT 50.88 44.66 51.09 44.73 ;
    RECT 50.88 45.02 51.09 45.09 ;
    RECT 50.42 44.3 50.63 44.37 ;
    RECT 50.42 44.66 50.63 44.73 ;
    RECT 50.42 45.02 50.63 45.09 ;
    RECT 47.56 44.3 47.77 44.37 ;
    RECT 47.56 44.66 47.77 44.73 ;
    RECT 47.56 45.02 47.77 45.09 ;
    RECT 47.1 44.3 47.31 44.37 ;
    RECT 47.1 44.66 47.31 44.73 ;
    RECT 47.1 45.02 47.31 45.09 ;
    RECT 55.64 46.24 55.71 46.31 ;
    RECT 55.43 45.98 55.5 46.05 ;
    RECT 43.78 45.98 43.99 46.05 ;
    RECT 41.035 46.24 41.105 46.31 ;
    RECT 41.245 45.98 41.315 46.05 ;
    RECT 47.1 45.98 47.31 46.05 ;
    RECT 47.56 45.98 47.77 46.05 ;
    RECT 43.29 46.5 43.5 46.57 ;
    RECT 50.42 45.98 50.63 46.05 ;
    RECT 50.88 45.98 51.09 46.05 ;
    RECT 54.655 46.76 54.875 46.83 ;
    RECT 51.335 46.76 51.555 46.83 ;
    RECT 48.015 46.76 48.235 46.83 ;
    RECT 44.695 46.76 44.915 46.83 ;
    RECT 46.61 46.5 46.82 46.57 ;
    RECT 53.74 45.98 53.95 46.05 ;
    RECT 43.29 46.24 43.5 46.31 ;
    RECT 53.25 46.24 53.46 46.31 ;
    RECT 54.2 45.98 54.41 46.05 ;
    RECT 44.24 45.98 44.45 46.05 ;
    RECT 49.93 46.5 50.14 46.57 ;
    RECT 46.61 46.24 46.82 46.31 ;
    RECT 53.25 46.5 53.46 46.57 ;
    RECT 49.93 46.24 50.14 46.31 ;
    RECT 44.24 32.78 44.45 32.85 ;
    RECT 44.24 33.14 44.45 33.21 ;
    RECT 44.24 33.5 44.45 33.57 ;
    RECT 43.78 32.78 43.99 32.85 ;
    RECT 43.78 33.14 43.99 33.21 ;
    RECT 43.78 33.5 43.99 33.57 ;
    RECT 55.43 33.14 55.5 33.21 ;
    RECT 41.245 33.14 41.315 33.21 ;
    RECT 54.2 32.78 54.41 32.85 ;
    RECT 54.2 33.14 54.41 33.21 ;
    RECT 54.2 33.5 54.41 33.57 ;
    RECT 53.74 32.78 53.95 32.85 ;
    RECT 53.74 33.14 53.95 33.21 ;
    RECT 53.74 33.5 53.95 33.57 ;
    RECT 50.88 32.78 51.09 32.85 ;
    RECT 50.88 33.14 51.09 33.21 ;
    RECT 50.88 33.5 51.09 33.57 ;
    RECT 50.42 32.78 50.63 32.85 ;
    RECT 50.42 33.14 50.63 33.21 ;
    RECT 50.42 33.5 50.63 33.57 ;
    RECT 47.56 32.78 47.77 32.85 ;
    RECT 47.56 33.14 47.77 33.21 ;
    RECT 47.56 33.5 47.77 33.57 ;
    RECT 47.1 32.78 47.31 32.85 ;
    RECT 47.1 33.14 47.31 33.21 ;
    RECT 47.1 33.5 47.31 33.57 ;
    RECT 44.24 43.58 44.45 43.65 ;
    RECT 44.24 43.94 44.45 44.01 ;
    RECT 44.24 44.3 44.45 44.37 ;
    RECT 43.78 43.58 43.99 43.65 ;
    RECT 43.78 43.94 43.99 44.01 ;
    RECT 43.78 44.3 43.99 44.37 ;
    RECT 41.245 43.94 41.315 44.01 ;
    RECT 55.43 43.94 55.5 44.01 ;
    RECT 54.2 43.58 54.41 43.65 ;
    RECT 54.2 43.94 54.41 44.01 ;
    RECT 54.2 44.3 54.41 44.37 ;
    RECT 53.74 43.58 53.95 43.65 ;
    RECT 53.74 43.94 53.95 44.01 ;
    RECT 53.74 44.3 53.95 44.37 ;
    RECT 50.88 43.58 51.09 43.65 ;
    RECT 50.88 43.94 51.09 44.01 ;
    RECT 50.88 44.3 51.09 44.37 ;
    RECT 50.42 43.58 50.63 43.65 ;
    RECT 50.42 43.94 50.63 44.01 ;
    RECT 50.42 44.3 50.63 44.37 ;
    RECT 47.56 43.58 47.77 43.65 ;
    RECT 47.56 43.94 47.77 44.01 ;
    RECT 47.56 44.3 47.77 44.37 ;
    RECT 47.1 43.58 47.31 43.65 ;
    RECT 47.1 43.94 47.31 44.01 ;
    RECT 47.1 44.3 47.31 44.37 ;
    RECT 44.24 42.86 44.45 42.93 ;
    RECT 44.24 43.22 44.45 43.29 ;
    RECT 44.24 43.58 44.45 43.65 ;
    RECT 43.78 42.86 43.99 42.93 ;
    RECT 43.78 43.22 43.99 43.29 ;
    RECT 43.78 43.58 43.99 43.65 ;
    RECT 41.245 43.22 41.315 43.29 ;
    RECT 55.43 43.22 55.5 43.29 ;
    RECT 54.2 42.86 54.41 42.93 ;
    RECT 54.2 43.22 54.41 43.29 ;
    RECT 54.2 43.58 54.41 43.65 ;
    RECT 53.74 42.86 53.95 42.93 ;
    RECT 53.74 43.22 53.95 43.29 ;
    RECT 53.74 43.58 53.95 43.65 ;
    RECT 50.88 42.86 51.09 42.93 ;
    RECT 50.88 43.22 51.09 43.29 ;
    RECT 50.88 43.58 51.09 43.65 ;
    RECT 50.42 42.86 50.63 42.93 ;
    RECT 50.42 43.22 50.63 43.29 ;
    RECT 50.42 43.58 50.63 43.65 ;
    RECT 47.56 42.86 47.77 42.93 ;
    RECT 47.56 43.22 47.77 43.29 ;
    RECT 47.56 43.58 47.77 43.65 ;
    RECT 47.1 42.86 47.31 42.93 ;
    RECT 47.1 43.22 47.31 43.29 ;
    RECT 47.1 43.58 47.31 43.65 ;
    RECT 44.24 42.14 44.45 42.21 ;
    RECT 44.24 42.5 44.45 42.57 ;
    RECT 44.24 42.86 44.45 42.93 ;
    RECT 43.78 42.14 43.99 42.21 ;
    RECT 43.78 42.5 43.99 42.57 ;
    RECT 43.78 42.86 43.99 42.93 ;
    RECT 41.245 42.5 41.315 42.57 ;
    RECT 55.43 42.5 55.5 42.57 ;
    RECT 54.2 42.14 54.41 42.21 ;
    RECT 54.2 42.5 54.41 42.57 ;
    RECT 54.2 42.86 54.41 42.93 ;
    RECT 53.74 42.14 53.95 42.21 ;
    RECT 53.74 42.5 53.95 42.57 ;
    RECT 53.74 42.86 53.95 42.93 ;
    RECT 50.88 42.14 51.09 42.21 ;
    RECT 50.88 42.5 51.09 42.57 ;
    RECT 50.88 42.86 51.09 42.93 ;
    RECT 50.42 42.14 50.63 42.21 ;
    RECT 50.42 42.5 50.63 42.57 ;
    RECT 50.42 42.86 50.63 42.93 ;
    RECT 47.56 42.14 47.77 42.21 ;
    RECT 47.56 42.5 47.77 42.57 ;
    RECT 47.56 42.86 47.77 42.93 ;
    RECT 47.1 42.14 47.31 42.21 ;
    RECT 47.1 42.5 47.31 42.57 ;
    RECT 47.1 42.86 47.31 42.93 ;
    RECT 44.24 41.42 44.45 41.49 ;
    RECT 44.24 41.78 44.45 41.85 ;
    RECT 44.24 42.14 44.45 42.21 ;
    RECT 43.78 41.42 43.99 41.49 ;
    RECT 43.78 41.78 43.99 41.85 ;
    RECT 43.78 42.14 43.99 42.21 ;
    RECT 41.245 41.78 41.315 41.85 ;
    RECT 55.43 41.78 55.5 41.85 ;
    RECT 54.2 41.42 54.41 41.49 ;
    RECT 54.2 41.78 54.41 41.85 ;
    RECT 54.2 42.14 54.41 42.21 ;
    RECT 53.74 41.42 53.95 41.49 ;
    RECT 53.74 41.78 53.95 41.85 ;
    RECT 53.74 42.14 53.95 42.21 ;
    RECT 50.88 41.42 51.09 41.49 ;
    RECT 50.88 41.78 51.09 41.85 ;
    RECT 50.88 42.14 51.09 42.21 ;
    RECT 50.42 41.42 50.63 41.49 ;
    RECT 50.42 41.78 50.63 41.85 ;
    RECT 50.42 42.14 50.63 42.21 ;
    RECT 47.56 41.42 47.77 41.49 ;
    RECT 47.56 41.78 47.77 41.85 ;
    RECT 47.56 42.14 47.77 42.21 ;
    RECT 47.1 41.42 47.31 41.49 ;
    RECT 47.1 41.78 47.31 41.85 ;
    RECT 47.1 42.14 47.31 42.21 ;
    RECT 44.24 40.7 44.45 40.77 ;
    RECT 44.24 41.06 44.45 41.13 ;
    RECT 44.24 41.42 44.45 41.49 ;
    RECT 43.78 40.7 43.99 40.77 ;
    RECT 43.78 41.06 43.99 41.13 ;
    RECT 43.78 41.42 43.99 41.49 ;
    RECT 41.245 41.06 41.315 41.13 ;
    RECT 55.43 41.06 55.5 41.13 ;
    RECT 54.2 40.7 54.41 40.77 ;
    RECT 54.2 41.06 54.41 41.13 ;
    RECT 54.2 41.42 54.41 41.49 ;
    RECT 53.74 40.7 53.95 40.77 ;
    RECT 53.74 41.06 53.95 41.13 ;
    RECT 53.74 41.42 53.95 41.49 ;
    RECT 50.88 40.7 51.09 40.77 ;
    RECT 50.88 41.06 51.09 41.13 ;
    RECT 50.88 41.42 51.09 41.49 ;
    RECT 50.42 40.7 50.63 40.77 ;
    RECT 50.42 41.06 50.63 41.13 ;
    RECT 50.42 41.42 50.63 41.49 ;
    RECT 47.56 40.7 47.77 40.77 ;
    RECT 47.56 41.06 47.77 41.13 ;
    RECT 47.56 41.42 47.77 41.49 ;
    RECT 47.1 40.7 47.31 40.77 ;
    RECT 47.1 41.06 47.31 41.13 ;
    RECT 47.1 41.42 47.31 41.49 ;
    RECT 44.24 39.98 44.45 40.05 ;
    RECT 44.24 40.34 44.45 40.41 ;
    RECT 44.24 40.7 44.45 40.77 ;
    RECT 43.78 39.98 43.99 40.05 ;
    RECT 43.78 40.34 43.99 40.41 ;
    RECT 43.78 40.7 43.99 40.77 ;
    RECT 41.245 40.34 41.315 40.41 ;
    RECT 55.43 40.34 55.5 40.41 ;
    RECT 54.2 39.98 54.41 40.05 ;
    RECT 54.2 40.34 54.41 40.41 ;
    RECT 54.2 40.7 54.41 40.77 ;
    RECT 53.74 39.98 53.95 40.05 ;
    RECT 53.74 40.34 53.95 40.41 ;
    RECT 53.74 40.7 53.95 40.77 ;
    RECT 50.88 39.98 51.09 40.05 ;
    RECT 50.88 40.34 51.09 40.41 ;
    RECT 50.88 40.7 51.09 40.77 ;
    RECT 50.42 39.98 50.63 40.05 ;
    RECT 50.42 40.34 50.63 40.41 ;
    RECT 50.42 40.7 50.63 40.77 ;
    RECT 47.56 39.98 47.77 40.05 ;
    RECT 47.56 40.34 47.77 40.41 ;
    RECT 47.56 40.7 47.77 40.77 ;
    RECT 47.1 39.98 47.31 40.05 ;
    RECT 47.1 40.34 47.31 40.41 ;
    RECT 47.1 40.7 47.31 40.77 ;
    RECT 44.24 39.26 44.45 39.33 ;
    RECT 44.24 39.62 44.45 39.69 ;
    RECT 44.24 39.98 44.45 40.05 ;
    RECT 43.78 39.26 43.99 39.33 ;
    RECT 43.78 39.62 43.99 39.69 ;
    RECT 43.78 39.98 43.99 40.05 ;
    RECT 41.245 39.62 41.315 39.69 ;
    RECT 55.43 39.62 55.5 39.69 ;
    RECT 54.2 39.26 54.41 39.33 ;
    RECT 54.2 39.62 54.41 39.69 ;
    RECT 54.2 39.98 54.41 40.05 ;
    RECT 53.74 39.26 53.95 39.33 ;
    RECT 53.74 39.62 53.95 39.69 ;
    RECT 53.74 39.98 53.95 40.05 ;
    RECT 50.88 39.26 51.09 39.33 ;
    RECT 50.88 39.62 51.09 39.69 ;
    RECT 50.88 39.98 51.09 40.05 ;
    RECT 50.42 39.26 50.63 39.33 ;
    RECT 50.42 39.62 50.63 39.69 ;
    RECT 50.42 39.98 50.63 40.05 ;
    RECT 47.56 39.26 47.77 39.33 ;
    RECT 47.56 39.62 47.77 39.69 ;
    RECT 47.56 39.98 47.77 40.05 ;
    RECT 47.1 39.26 47.31 39.33 ;
    RECT 47.1 39.62 47.31 39.69 ;
    RECT 47.1 39.98 47.31 40.05 ;
    RECT 44.24 38.54 44.45 38.61 ;
    RECT 44.24 38.9 44.45 38.97 ;
    RECT 44.24 39.26 44.45 39.33 ;
    RECT 43.78 38.54 43.99 38.61 ;
    RECT 43.78 38.9 43.99 38.97 ;
    RECT 43.78 39.26 43.99 39.33 ;
    RECT 41.245 38.9 41.315 38.97 ;
    RECT 55.43 38.9 55.5 38.97 ;
    RECT 54.2 38.54 54.41 38.61 ;
    RECT 54.2 38.9 54.41 38.97 ;
    RECT 54.2 39.26 54.41 39.33 ;
    RECT 53.74 38.54 53.95 38.61 ;
    RECT 53.74 38.9 53.95 38.97 ;
    RECT 53.74 39.26 53.95 39.33 ;
    RECT 50.88 38.54 51.09 38.61 ;
    RECT 50.88 38.9 51.09 38.97 ;
    RECT 50.88 39.26 51.09 39.33 ;
    RECT 50.42 38.54 50.63 38.61 ;
    RECT 50.42 38.9 50.63 38.97 ;
    RECT 50.42 39.26 50.63 39.33 ;
    RECT 47.56 38.54 47.77 38.61 ;
    RECT 47.56 38.9 47.77 38.97 ;
    RECT 47.56 39.26 47.77 39.33 ;
    RECT 47.1 38.54 47.31 38.61 ;
    RECT 47.1 38.9 47.31 38.97 ;
    RECT 47.1 39.26 47.31 39.33 ;
    RECT 44.24 37.82 44.45 37.89 ;
    RECT 44.24 38.18 44.45 38.25 ;
    RECT 44.24 38.54 44.45 38.61 ;
    RECT 43.78 37.82 43.99 37.89 ;
    RECT 43.78 38.18 43.99 38.25 ;
    RECT 43.78 38.54 43.99 38.61 ;
    RECT 41.245 38.18 41.315 38.25 ;
    RECT 55.43 38.18 55.5 38.25 ;
    RECT 54.2 37.82 54.41 37.89 ;
    RECT 54.2 38.18 54.41 38.25 ;
    RECT 54.2 38.54 54.41 38.61 ;
    RECT 53.74 37.82 53.95 37.89 ;
    RECT 53.74 38.18 53.95 38.25 ;
    RECT 53.74 38.54 53.95 38.61 ;
    RECT 50.88 37.82 51.09 37.89 ;
    RECT 50.88 38.18 51.09 38.25 ;
    RECT 50.88 38.54 51.09 38.61 ;
    RECT 50.42 37.82 50.63 37.89 ;
    RECT 50.42 38.18 50.63 38.25 ;
    RECT 50.42 38.54 50.63 38.61 ;
    RECT 47.56 37.82 47.77 37.89 ;
    RECT 47.56 38.18 47.77 38.25 ;
    RECT 47.56 38.54 47.77 38.61 ;
    RECT 47.1 37.82 47.31 37.89 ;
    RECT 47.1 38.18 47.31 38.25 ;
    RECT 47.1 38.54 47.31 38.61 ;
    RECT 44.24 37.1 44.45 37.17 ;
    RECT 44.24 37.46 44.45 37.53 ;
    RECT 44.24 37.82 44.45 37.89 ;
    RECT 43.78 37.1 43.99 37.17 ;
    RECT 43.78 37.46 43.99 37.53 ;
    RECT 43.78 37.82 43.99 37.89 ;
    RECT 41.245 37.46 41.315 37.53 ;
    RECT 55.43 37.46 55.5 37.53 ;
    RECT 54.2 37.1 54.41 37.17 ;
    RECT 54.2 37.46 54.41 37.53 ;
    RECT 54.2 37.82 54.41 37.89 ;
    RECT 53.74 37.1 53.95 37.17 ;
    RECT 53.74 37.46 53.95 37.53 ;
    RECT 53.74 37.82 53.95 37.89 ;
    RECT 50.88 37.1 51.09 37.17 ;
    RECT 50.88 37.46 51.09 37.53 ;
    RECT 50.88 37.82 51.09 37.89 ;
    RECT 50.42 37.1 50.63 37.17 ;
    RECT 50.42 37.46 50.63 37.53 ;
    RECT 50.42 37.82 50.63 37.89 ;
    RECT 47.56 37.1 47.77 37.17 ;
    RECT 47.56 37.46 47.77 37.53 ;
    RECT 47.56 37.82 47.77 37.89 ;
    RECT 47.1 37.1 47.31 37.17 ;
    RECT 47.1 37.46 47.31 37.53 ;
    RECT 47.1 37.82 47.31 37.89 ;
    RECT 44.24 29.18 44.45 29.25 ;
    RECT 44.24 29.54 44.45 29.61 ;
    RECT 44.24 29.9 44.45 29.97 ;
    RECT 43.78 29.18 43.99 29.25 ;
    RECT 43.78 29.54 43.99 29.61 ;
    RECT 43.78 29.9 43.99 29.97 ;
    RECT 41.245 29.54 41.315 29.61 ;
    RECT 55.43 29.54 55.5 29.61 ;
    RECT 54.2 29.18 54.41 29.25 ;
    RECT 54.2 29.54 54.41 29.61 ;
    RECT 54.2 29.9 54.41 29.97 ;
    RECT 53.74 29.18 53.95 29.25 ;
    RECT 53.74 29.54 53.95 29.61 ;
    RECT 53.74 29.9 53.95 29.97 ;
    RECT 50.88 29.18 51.09 29.25 ;
    RECT 50.88 29.54 51.09 29.61 ;
    RECT 50.88 29.9 51.09 29.97 ;
    RECT 50.42 29.18 50.63 29.25 ;
    RECT 50.42 29.54 50.63 29.61 ;
    RECT 50.42 29.9 50.63 29.97 ;
    RECT 47.56 29.18 47.77 29.25 ;
    RECT 47.56 29.54 47.77 29.61 ;
    RECT 47.56 29.9 47.77 29.97 ;
    RECT 47.1 29.18 47.31 29.25 ;
    RECT 47.1 29.54 47.31 29.61 ;
    RECT 47.1 29.9 47.31 29.97 ;
    RECT 44.24 28.46 44.45 28.53 ;
    RECT 44.24 28.82 44.45 28.89 ;
    RECT 44.24 29.18 44.45 29.25 ;
    RECT 43.78 28.46 43.99 28.53 ;
    RECT 43.78 28.82 43.99 28.89 ;
    RECT 43.78 29.18 43.99 29.25 ;
    RECT 41.245 28.82 41.315 28.89 ;
    RECT 55.43 28.82 55.5 28.89 ;
    RECT 54.2 28.46 54.41 28.53 ;
    RECT 54.2 28.82 54.41 28.89 ;
    RECT 54.2 29.18 54.41 29.25 ;
    RECT 53.74 28.46 53.95 28.53 ;
    RECT 53.74 28.82 53.95 28.89 ;
    RECT 53.74 29.18 53.95 29.25 ;
    RECT 50.88 28.46 51.09 28.53 ;
    RECT 50.88 28.82 51.09 28.89 ;
    RECT 50.88 29.18 51.09 29.25 ;
    RECT 50.42 28.46 50.63 28.53 ;
    RECT 50.42 28.82 50.63 28.89 ;
    RECT 50.42 29.18 50.63 29.25 ;
    RECT 47.56 28.46 47.77 28.53 ;
    RECT 47.56 28.82 47.77 28.89 ;
    RECT 47.56 29.18 47.77 29.25 ;
    RECT 47.1 28.46 47.31 28.53 ;
    RECT 47.1 28.82 47.31 28.89 ;
    RECT 47.1 29.18 47.31 29.25 ;
    RECT 44.24 27.74 44.45 27.81 ;
    RECT 44.24 28.1 44.45 28.17 ;
    RECT 44.24 28.46 44.45 28.53 ;
    RECT 43.78 27.74 43.99 27.81 ;
    RECT 43.78 28.1 43.99 28.17 ;
    RECT 43.78 28.46 43.99 28.53 ;
    RECT 41.245 28.1 41.315 28.17 ;
    RECT 55.43 28.1 55.5 28.17 ;
    RECT 54.2 27.74 54.41 27.81 ;
    RECT 54.2 28.1 54.41 28.17 ;
    RECT 54.2 28.46 54.41 28.53 ;
    RECT 53.74 27.74 53.95 27.81 ;
    RECT 53.74 28.1 53.95 28.17 ;
    RECT 53.74 28.46 53.95 28.53 ;
    RECT 50.88 27.74 51.09 27.81 ;
    RECT 50.88 28.1 51.09 28.17 ;
    RECT 50.88 28.46 51.09 28.53 ;
    RECT 50.42 27.74 50.63 27.81 ;
    RECT 50.42 28.1 50.63 28.17 ;
    RECT 50.42 28.46 50.63 28.53 ;
    RECT 47.56 27.74 47.77 27.81 ;
    RECT 47.56 28.1 47.77 28.17 ;
    RECT 47.56 28.46 47.77 28.53 ;
    RECT 47.1 27.74 47.31 27.81 ;
    RECT 47.1 28.1 47.31 28.17 ;
    RECT 47.1 28.46 47.31 28.53 ;
    RECT 44.24 27.02 44.45 27.09 ;
    RECT 44.24 27.38 44.45 27.45 ;
    RECT 44.24 27.74 44.45 27.81 ;
    RECT 43.78 27.02 43.99 27.09 ;
    RECT 43.78 27.38 43.99 27.45 ;
    RECT 43.78 27.74 43.99 27.81 ;
    RECT 41.245 27.38 41.315 27.45 ;
    RECT 55.43 27.38 55.5 27.45 ;
    RECT 54.2 27.02 54.41 27.09 ;
    RECT 54.2 27.38 54.41 27.45 ;
    RECT 54.2 27.74 54.41 27.81 ;
    RECT 53.74 27.02 53.95 27.09 ;
    RECT 53.74 27.38 53.95 27.45 ;
    RECT 53.74 27.74 53.95 27.81 ;
    RECT 50.88 27.02 51.09 27.09 ;
    RECT 50.88 27.38 51.09 27.45 ;
    RECT 50.88 27.74 51.09 27.81 ;
    RECT 50.42 27.02 50.63 27.09 ;
    RECT 50.42 27.38 50.63 27.45 ;
    RECT 50.42 27.74 50.63 27.81 ;
    RECT 47.56 27.02 47.77 27.09 ;
    RECT 47.56 27.38 47.77 27.45 ;
    RECT 47.56 27.74 47.77 27.81 ;
    RECT 47.1 27.02 47.31 27.09 ;
    RECT 47.1 27.38 47.31 27.45 ;
    RECT 47.1 27.74 47.31 27.81 ;
    RECT 44.24 26.3 44.45 26.37 ;
    RECT 44.24 26.66 44.45 26.73 ;
    RECT 44.24 27.02 44.45 27.09 ;
    RECT 43.78 26.3 43.99 26.37 ;
    RECT 43.78 26.66 43.99 26.73 ;
    RECT 43.78 27.02 43.99 27.09 ;
    RECT 41.245 26.66 41.315 26.73 ;
    RECT 55.43 26.66 55.5 26.73 ;
    RECT 54.2 26.3 54.41 26.37 ;
    RECT 54.2 26.66 54.41 26.73 ;
    RECT 54.2 27.02 54.41 27.09 ;
    RECT 53.74 26.3 53.95 26.37 ;
    RECT 53.74 26.66 53.95 26.73 ;
    RECT 53.74 27.02 53.95 27.09 ;
    RECT 50.88 26.3 51.09 26.37 ;
    RECT 50.88 26.66 51.09 26.73 ;
    RECT 50.88 27.02 51.09 27.09 ;
    RECT 50.42 26.3 50.63 26.37 ;
    RECT 50.42 26.66 50.63 26.73 ;
    RECT 50.42 27.02 50.63 27.09 ;
    RECT 47.56 26.3 47.77 26.37 ;
    RECT 47.56 26.66 47.77 26.73 ;
    RECT 47.56 27.02 47.77 27.09 ;
    RECT 47.1 26.3 47.31 26.37 ;
    RECT 47.1 26.66 47.31 26.73 ;
    RECT 47.1 27.02 47.31 27.09 ;
    RECT 44.24 25.58 44.45 25.65 ;
    RECT 44.24 25.94 44.45 26.01 ;
    RECT 44.24 26.3 44.45 26.37 ;
    RECT 43.78 25.58 43.99 25.65 ;
    RECT 43.78 25.94 43.99 26.01 ;
    RECT 43.78 26.3 43.99 26.37 ;
    RECT 41.245 25.94 41.315 26.01 ;
    RECT 55.43 25.94 55.5 26.01 ;
    RECT 54.2 25.58 54.41 25.65 ;
    RECT 54.2 25.94 54.41 26.01 ;
    RECT 54.2 26.3 54.41 26.37 ;
    RECT 53.74 25.58 53.95 25.65 ;
    RECT 53.74 25.94 53.95 26.01 ;
    RECT 53.74 26.3 53.95 26.37 ;
    RECT 50.88 25.58 51.09 25.65 ;
    RECT 50.88 25.94 51.09 26.01 ;
    RECT 50.88 26.3 51.09 26.37 ;
    RECT 50.42 25.58 50.63 25.65 ;
    RECT 50.42 25.94 50.63 26.01 ;
    RECT 50.42 26.3 50.63 26.37 ;
    RECT 47.56 25.58 47.77 25.65 ;
    RECT 47.56 25.94 47.77 26.01 ;
    RECT 47.56 26.3 47.77 26.37 ;
    RECT 47.1 25.58 47.31 25.65 ;
    RECT 47.1 25.94 47.31 26.01 ;
    RECT 47.1 26.3 47.31 26.37 ;
    RECT 44.24 33.5 44.45 33.57 ;
    RECT 44.24 33.86 44.45 33.93 ;
    RECT 44.24 34.22 44.45 34.29 ;
    RECT 43.78 33.5 43.99 33.57 ;
    RECT 43.78 33.86 43.99 33.93 ;
    RECT 43.78 34.22 43.99 34.29 ;
    RECT 55.43 33.86 55.5 33.93 ;
    RECT 41.245 33.86 41.315 33.93 ;
    RECT 54.2 33.5 54.41 33.57 ;
    RECT 54.2 33.86 54.41 33.93 ;
    RECT 54.2 34.22 54.41 34.29 ;
    RECT 53.74 33.5 53.95 33.57 ;
    RECT 53.74 33.86 53.95 33.93 ;
    RECT 53.74 34.22 53.95 34.29 ;
    RECT 50.88 33.5 51.09 33.57 ;
    RECT 50.88 33.86 51.09 33.93 ;
    RECT 50.88 34.22 51.09 34.29 ;
    RECT 50.42 33.5 50.63 33.57 ;
    RECT 50.42 33.86 50.63 33.93 ;
    RECT 50.42 34.22 50.63 34.29 ;
    RECT 47.56 33.5 47.77 33.57 ;
    RECT 47.56 33.86 47.77 33.93 ;
    RECT 47.56 34.22 47.77 34.29 ;
    RECT 47.1 33.5 47.31 33.57 ;
    RECT 47.1 33.86 47.31 33.93 ;
    RECT 47.1 34.22 47.31 34.29 ;
    RECT 44.24 24.86 44.45 24.93 ;
    RECT 44.24 25.22 44.45 25.29 ;
    RECT 44.24 25.58 44.45 25.65 ;
    RECT 43.78 24.86 43.99 24.93 ;
    RECT 43.78 25.22 43.99 25.29 ;
    RECT 43.78 25.58 43.99 25.65 ;
    RECT 41.245 25.22 41.315 25.29 ;
    RECT 55.43 25.22 55.5 25.29 ;
    RECT 54.2 24.86 54.41 24.93 ;
    RECT 54.2 25.22 54.41 25.29 ;
    RECT 54.2 25.58 54.41 25.65 ;
    RECT 53.74 24.86 53.95 24.93 ;
    RECT 53.74 25.22 53.95 25.29 ;
    RECT 53.74 25.58 53.95 25.65 ;
    RECT 50.88 24.86 51.09 24.93 ;
    RECT 50.88 25.22 51.09 25.29 ;
    RECT 50.88 25.58 51.09 25.65 ;
    RECT 50.42 24.86 50.63 24.93 ;
    RECT 50.42 25.22 50.63 25.29 ;
    RECT 50.42 25.58 50.63 25.65 ;
    RECT 47.56 24.86 47.77 24.93 ;
    RECT 47.56 25.22 47.77 25.29 ;
    RECT 47.56 25.58 47.77 25.65 ;
    RECT 47.1 24.86 47.31 24.93 ;
    RECT 47.1 25.22 47.31 25.29 ;
    RECT 47.1 25.58 47.31 25.65 ;
    RECT 44.24 24.14 44.45 24.21 ;
    RECT 44.24 24.5 44.45 24.57 ;
    RECT 44.24 24.86 44.45 24.93 ;
    RECT 43.78 24.14 43.99 24.21 ;
    RECT 43.78 24.5 43.99 24.57 ;
    RECT 43.78 24.86 43.99 24.93 ;
    RECT 41.245 24.5 41.315 24.57 ;
    RECT 55.43 24.5 55.5 24.57 ;
    RECT 54.2 24.14 54.41 24.21 ;
    RECT 54.2 24.5 54.41 24.57 ;
    RECT 54.2 24.86 54.41 24.93 ;
    RECT 53.74 24.14 53.95 24.21 ;
    RECT 53.74 24.5 53.95 24.57 ;
    RECT 53.74 24.86 53.95 24.93 ;
    RECT 50.88 24.14 51.09 24.21 ;
    RECT 50.88 24.5 51.09 24.57 ;
    RECT 50.88 24.86 51.09 24.93 ;
    RECT 50.42 24.14 50.63 24.21 ;
    RECT 50.42 24.5 50.63 24.57 ;
    RECT 50.42 24.86 50.63 24.93 ;
    RECT 47.56 24.14 47.77 24.21 ;
    RECT 47.56 24.5 47.77 24.57 ;
    RECT 47.56 24.86 47.77 24.93 ;
    RECT 47.1 24.14 47.31 24.21 ;
    RECT 47.1 24.5 47.31 24.57 ;
    RECT 47.1 24.86 47.31 24.93 ;
    RECT 44.24 23.42 44.45 23.49 ;
    RECT 44.24 23.78 44.45 23.85 ;
    RECT 44.24 24.14 44.45 24.21 ;
    RECT 43.78 23.42 43.99 23.49 ;
    RECT 43.78 23.78 43.99 23.85 ;
    RECT 43.78 24.14 43.99 24.21 ;
    RECT 41.245 23.78 41.315 23.85 ;
    RECT 55.43 23.78 55.5 23.85 ;
    RECT 54.2 23.42 54.41 23.49 ;
    RECT 54.2 23.78 54.41 23.85 ;
    RECT 54.2 24.14 54.41 24.21 ;
    RECT 53.74 23.42 53.95 23.49 ;
    RECT 53.74 23.78 53.95 23.85 ;
    RECT 53.74 24.14 53.95 24.21 ;
    RECT 50.88 23.42 51.09 23.49 ;
    RECT 50.88 23.78 51.09 23.85 ;
    RECT 50.88 24.14 51.09 24.21 ;
    RECT 50.42 23.42 50.63 23.49 ;
    RECT 50.42 23.78 50.63 23.85 ;
    RECT 50.42 24.14 50.63 24.21 ;
    RECT 47.56 23.42 47.77 23.49 ;
    RECT 47.56 23.78 47.77 23.85 ;
    RECT 47.56 24.14 47.77 24.21 ;
    RECT 47.1 23.42 47.31 23.49 ;
    RECT 47.1 23.78 47.31 23.85 ;
    RECT 47.1 24.14 47.31 24.21 ;
    RECT 44.24 36.38 44.45 36.45 ;
    RECT 44.24 36.74 44.45 36.81 ;
    RECT 44.24 37.1 44.45 37.17 ;
    RECT 43.78 36.38 43.99 36.45 ;
    RECT 43.78 36.74 43.99 36.81 ;
    RECT 43.78 37.1 43.99 37.17 ;
    RECT 41.245 36.74 41.315 36.81 ;
    RECT 55.43 36.74 55.5 36.81 ;
    RECT 54.2 36.38 54.41 36.45 ;
    RECT 54.2 36.74 54.41 36.81 ;
    RECT 54.2 37.1 54.41 37.17 ;
    RECT 53.74 36.38 53.95 36.45 ;
    RECT 53.74 36.74 53.95 36.81 ;
    RECT 53.74 37.1 53.95 37.17 ;
    RECT 50.88 36.38 51.09 36.45 ;
    RECT 50.88 36.74 51.09 36.81 ;
    RECT 50.88 37.1 51.09 37.17 ;
    RECT 50.42 36.38 50.63 36.45 ;
    RECT 50.42 36.74 50.63 36.81 ;
    RECT 50.42 37.1 50.63 37.17 ;
    RECT 47.56 36.38 47.77 36.45 ;
    RECT 47.56 36.74 47.77 36.81 ;
    RECT 47.56 37.1 47.77 37.17 ;
    RECT 47.1 36.38 47.31 36.45 ;
    RECT 47.1 36.74 47.31 36.81 ;
    RECT 47.1 37.1 47.31 37.17 ;
    RECT 44.24 35.66 44.45 35.73 ;
    RECT 44.24 36.02 44.45 36.09 ;
    RECT 44.24 36.38 44.45 36.45 ;
    RECT 43.78 35.66 43.99 35.73 ;
    RECT 43.78 36.02 43.99 36.09 ;
    RECT 43.78 36.38 43.99 36.45 ;
    RECT 41.245 36.02 41.315 36.09 ;
    RECT 55.43 36.02 55.5 36.09 ;
    RECT 54.2 35.66 54.41 35.73 ;
    RECT 54.2 36.02 54.41 36.09 ;
    RECT 54.2 36.38 54.41 36.45 ;
    RECT 53.74 35.66 53.95 35.73 ;
    RECT 53.74 36.02 53.95 36.09 ;
    RECT 53.74 36.38 53.95 36.45 ;
    RECT 50.88 35.66 51.09 35.73 ;
    RECT 50.88 36.02 51.09 36.09 ;
    RECT 50.88 36.38 51.09 36.45 ;
    RECT 50.42 35.66 50.63 35.73 ;
    RECT 50.42 36.02 50.63 36.09 ;
    RECT 50.42 36.38 50.63 36.45 ;
    RECT 47.56 35.66 47.77 35.73 ;
    RECT 47.56 36.02 47.77 36.09 ;
    RECT 47.56 36.38 47.77 36.45 ;
    RECT 47.1 35.66 47.31 35.73 ;
    RECT 47.1 36.02 47.31 36.09 ;
    RECT 47.1 36.38 47.31 36.45 ;
    RECT 44.24 34.94 44.45 35.01 ;
    RECT 44.24 35.3 44.45 35.37 ;
    RECT 44.24 35.66 44.45 35.73 ;
    RECT 43.78 34.94 43.99 35.01 ;
    RECT 43.78 35.3 43.99 35.37 ;
    RECT 43.78 35.66 43.99 35.73 ;
    RECT 41.245 35.3 41.315 35.37 ;
    RECT 55.43 35.3 55.5 35.37 ;
    RECT 54.2 34.94 54.41 35.01 ;
    RECT 54.2 35.3 54.41 35.37 ;
    RECT 54.2 35.66 54.41 35.73 ;
    RECT 53.74 34.94 53.95 35.01 ;
    RECT 53.74 35.3 53.95 35.37 ;
    RECT 53.74 35.66 53.95 35.73 ;
    RECT 50.88 34.94 51.09 35.01 ;
    RECT 50.88 35.3 51.09 35.37 ;
    RECT 50.88 35.66 51.09 35.73 ;
    RECT 50.42 34.94 50.63 35.01 ;
    RECT 50.42 35.3 50.63 35.37 ;
    RECT 50.42 35.66 50.63 35.73 ;
    RECT 47.56 34.94 47.77 35.01 ;
    RECT 47.56 35.3 47.77 35.37 ;
    RECT 47.56 35.66 47.77 35.73 ;
    RECT 47.1 34.94 47.31 35.01 ;
    RECT 47.1 35.3 47.31 35.37 ;
    RECT 47.1 35.66 47.31 35.73 ;
    RECT 44.24 32.06 44.45 32.13 ;
    RECT 44.24 32.42 44.45 32.49 ;
    RECT 44.24 32.78 44.45 32.85 ;
    RECT 43.78 32.06 43.99 32.13 ;
    RECT 43.78 32.42 43.99 32.49 ;
    RECT 43.78 32.78 43.99 32.85 ;
    RECT 41.245 32.42 41.315 32.49 ;
    RECT 55.43 32.42 55.5 32.49 ;
    RECT 54.2 32.06 54.41 32.13 ;
    RECT 54.2 32.42 54.41 32.49 ;
    RECT 54.2 32.78 54.41 32.85 ;
    RECT 53.74 32.06 53.95 32.13 ;
    RECT 53.74 32.42 53.95 32.49 ;
    RECT 53.74 32.78 53.95 32.85 ;
    RECT 50.88 32.06 51.09 32.13 ;
    RECT 50.88 32.42 51.09 32.49 ;
    RECT 50.88 32.78 51.09 32.85 ;
    RECT 50.42 32.06 50.63 32.13 ;
    RECT 50.42 32.42 50.63 32.49 ;
    RECT 50.42 32.78 50.63 32.85 ;
    RECT 47.56 32.06 47.77 32.13 ;
    RECT 47.56 32.42 47.77 32.49 ;
    RECT 47.56 32.78 47.77 32.85 ;
    RECT 47.1 32.06 47.31 32.13 ;
    RECT 47.1 32.42 47.31 32.49 ;
    RECT 47.1 32.78 47.31 32.85 ;
    RECT 44.24 31.34 44.45 31.41 ;
    RECT 44.24 31.7 44.45 31.77 ;
    RECT 44.24 32.06 44.45 32.13 ;
    RECT 43.78 31.34 43.99 31.41 ;
    RECT 43.78 31.7 43.99 31.77 ;
    RECT 43.78 32.06 43.99 32.13 ;
    RECT 41.245 31.7 41.315 31.77 ;
    RECT 55.43 31.7 55.5 31.77 ;
    RECT 54.2 31.34 54.41 31.41 ;
    RECT 54.2 31.7 54.41 31.77 ;
    RECT 54.2 32.06 54.41 32.13 ;
    RECT 53.74 31.34 53.95 31.41 ;
    RECT 53.74 31.7 53.95 31.77 ;
    RECT 53.74 32.06 53.95 32.13 ;
    RECT 50.88 31.34 51.09 31.41 ;
    RECT 50.88 31.7 51.09 31.77 ;
    RECT 50.88 32.06 51.09 32.13 ;
    RECT 50.42 31.34 50.63 31.41 ;
    RECT 50.42 31.7 50.63 31.77 ;
    RECT 50.42 32.06 50.63 32.13 ;
    RECT 47.56 31.34 47.77 31.41 ;
    RECT 47.56 31.7 47.77 31.77 ;
    RECT 47.56 32.06 47.77 32.13 ;
    RECT 47.1 31.34 47.31 31.41 ;
    RECT 47.1 31.7 47.31 31.77 ;
    RECT 47.1 32.06 47.31 32.13 ;
    RECT 54.2 22.7 54.41 22.77 ;
    RECT 54.2 23.06 54.41 23.13 ;
    RECT 54.2 23.42 54.41 23.49 ;
    RECT 53.74 22.7 53.95 22.77 ;
    RECT 53.74 23.06 53.95 23.13 ;
    RECT 53.74 23.42 53.95 23.49 ;
    RECT 41.245 23.06 41.315 23.13 ;
    RECT 44.24 22.7 44.45 22.77 ;
    RECT 44.24 23.06 44.45 23.13 ;
    RECT 44.24 23.42 44.45 23.49 ;
    RECT 43.78 22.7 43.99 22.77 ;
    RECT 43.78 23.06 43.99 23.13 ;
    RECT 43.78 23.42 43.99 23.49 ;
    RECT 55.43 23.06 55.5 23.13 ;
    RECT 50.88 22.7 51.09 22.77 ;
    RECT 50.88 23.06 51.09 23.13 ;
    RECT 50.88 23.42 51.09 23.49 ;
    RECT 50.42 22.7 50.63 22.77 ;
    RECT 50.42 23.06 50.63 23.13 ;
    RECT 50.42 23.42 50.63 23.49 ;
    RECT 47.56 22.7 47.77 22.77 ;
    RECT 47.56 23.06 47.77 23.13 ;
    RECT 47.56 23.42 47.77 23.49 ;
    RECT 47.1 22.7 47.31 22.77 ;
    RECT 47.1 23.06 47.31 23.13 ;
    RECT 47.1 23.42 47.31 23.49 ;
    RECT 44.24 30.62 44.45 30.69 ;
    RECT 44.24 30.98 44.45 31.05 ;
    RECT 44.24 31.34 44.45 31.41 ;
    RECT 43.78 30.62 43.99 30.69 ;
    RECT 43.78 30.98 43.99 31.05 ;
    RECT 43.78 31.34 43.99 31.41 ;
    RECT 41.245 30.98 41.315 31.05 ;
    RECT 55.43 30.98 55.5 31.05 ;
    RECT 54.2 30.62 54.41 30.69 ;
    RECT 54.2 30.98 54.41 31.05 ;
    RECT 54.2 31.34 54.41 31.41 ;
    RECT 53.74 30.62 53.95 30.69 ;
    RECT 53.74 30.98 53.95 31.05 ;
    RECT 53.74 31.34 53.95 31.41 ;
    RECT 50.88 30.62 51.09 30.69 ;
    RECT 50.88 30.98 51.09 31.05 ;
    RECT 50.88 31.34 51.09 31.41 ;
    RECT 50.42 30.62 50.63 30.69 ;
    RECT 50.42 30.98 50.63 31.05 ;
    RECT 50.42 31.34 50.63 31.41 ;
    RECT 47.56 30.62 47.77 30.69 ;
    RECT 47.56 30.98 47.77 31.05 ;
    RECT 47.56 31.34 47.77 31.41 ;
    RECT 47.1 30.62 47.31 30.69 ;
    RECT 47.1 30.98 47.31 31.05 ;
    RECT 47.1 31.34 47.31 31.41 ;
    RECT 44.24 29.9 44.45 29.97 ;
    RECT 44.24 30.26 44.45 30.33 ;
    RECT 44.24 30.62 44.45 30.69 ;
    RECT 43.78 29.9 43.99 29.97 ;
    RECT 43.78 30.26 43.99 30.33 ;
    RECT 43.78 30.62 43.99 30.69 ;
    RECT 41.245 30.26 41.315 30.33 ;
    RECT 55.43 30.26 55.5 30.33 ;
    RECT 54.2 29.9 54.41 29.97 ;
    RECT 54.2 30.26 54.41 30.33 ;
    RECT 54.2 30.62 54.41 30.69 ;
    RECT 53.74 29.9 53.95 29.97 ;
    RECT 53.74 30.26 53.95 30.33 ;
    RECT 53.74 30.62 53.95 30.69 ;
    RECT 50.88 29.9 51.09 29.97 ;
    RECT 50.88 30.26 51.09 30.33 ;
    RECT 50.88 30.62 51.09 30.69 ;
    RECT 50.42 29.9 50.63 29.97 ;
    RECT 50.42 30.26 50.63 30.33 ;
    RECT 50.42 30.62 50.63 30.69 ;
    RECT 47.56 29.9 47.77 29.97 ;
    RECT 47.56 30.26 47.77 30.33 ;
    RECT 47.56 30.62 47.77 30.69 ;
    RECT 47.1 29.9 47.31 29.97 ;
    RECT 47.1 30.26 47.31 30.33 ;
    RECT 47.1 30.62 47.31 30.69 ;
    RECT 1.49 45.02 1.7 45.09 ;
    RECT 1.49 45.38 1.7 45.45 ;
    RECT 1.49 45.74 1.7 45.81 ;
    RECT 1.95 45.02 2.16 45.09 ;
    RECT 1.95 45.38 2.16 45.45 ;
    RECT 1.95 45.74 2.16 45.81 ;
    RECT 14.585 45.38 14.655 45.45 ;
    RECT 11.45 45.02 11.66 45.09 ;
    RECT 11.45 45.38 11.66 45.45 ;
    RECT 11.45 45.74 11.66 45.81 ;
    RECT 11.91 45.02 12.12 45.09 ;
    RECT 11.91 45.38 12.12 45.45 ;
    RECT 11.91 45.74 12.12 45.81 ;
    RECT 0.4 45.38 0.47 45.45 ;
    RECT 8.13 45.02 8.34 45.09 ;
    RECT 8.13 45.38 8.34 45.45 ;
    RECT 8.13 45.74 8.34 45.81 ;
    RECT 8.59 45.02 8.8 45.09 ;
    RECT 8.59 45.38 8.8 45.45 ;
    RECT 8.59 45.74 8.8 45.81 ;
    RECT 4.81 45.02 5.02 45.09 ;
    RECT 4.81 45.38 5.02 45.45 ;
    RECT 4.81 45.74 5.02 45.81 ;
    RECT 5.27 45.02 5.48 45.09 ;
    RECT 5.27 45.38 5.48 45.45 ;
    RECT 5.27 45.74 5.48 45.81 ;
    RECT 1.49 34.22 1.7 34.29 ;
    RECT 1.49 34.58 1.7 34.65 ;
    RECT 1.49 34.94 1.7 35.01 ;
    RECT 1.95 34.22 2.16 34.29 ;
    RECT 1.95 34.58 2.16 34.65 ;
    RECT 1.95 34.94 2.16 35.01 ;
    RECT 14.585 34.58 14.655 34.65 ;
    RECT 11.45 34.22 11.66 34.29 ;
    RECT 11.45 34.58 11.66 34.65 ;
    RECT 11.45 34.94 11.66 35.01 ;
    RECT 11.91 34.22 12.12 34.29 ;
    RECT 11.91 34.58 12.12 34.65 ;
    RECT 11.91 34.94 12.12 35.01 ;
    RECT 8.13 34.22 8.34 34.29 ;
    RECT 8.13 34.58 8.34 34.65 ;
    RECT 8.13 34.94 8.34 35.01 ;
    RECT 8.59 34.22 8.8 34.29 ;
    RECT 8.59 34.58 8.8 34.65 ;
    RECT 8.59 34.94 8.8 35.01 ;
    RECT 4.81 34.22 5.02 34.29 ;
    RECT 4.81 34.58 5.02 34.65 ;
    RECT 4.81 34.94 5.02 35.01 ;
    RECT 5.27 34.22 5.48 34.29 ;
    RECT 5.27 34.58 5.48 34.65 ;
    RECT 5.27 34.94 5.48 35.01 ;
    RECT 0.4 34.58 0.47 34.65 ;
    RECT 1.49 36.38 1.7 36.45 ;
    RECT 1.49 36.74 1.7 36.81 ;
    RECT 1.49 37.1 1.7 37.17 ;
    RECT 1.95 36.38 2.16 36.45 ;
    RECT 1.95 36.74 2.16 36.81 ;
    RECT 1.95 37.1 2.16 37.17 ;
    RECT 14.585 36.74 14.655 36.81 ;
    RECT 0.4 36.74 0.47 36.81 ;
    RECT 11.45 36.38 11.66 36.45 ;
    RECT 11.45 36.74 11.66 36.81 ;
    RECT 11.45 37.1 11.66 37.17 ;
    RECT 11.91 36.38 12.12 36.45 ;
    RECT 11.91 36.74 12.12 36.81 ;
    RECT 11.91 37.1 12.12 37.17 ;
    RECT 8.13 36.38 8.34 36.45 ;
    RECT 8.13 36.74 8.34 36.81 ;
    RECT 8.13 37.1 8.34 37.17 ;
    RECT 8.59 36.38 8.8 36.45 ;
    RECT 8.59 36.74 8.8 36.81 ;
    RECT 8.59 37.1 8.8 37.17 ;
    RECT 4.81 36.38 5.02 36.45 ;
    RECT 4.81 36.74 5.02 36.81 ;
    RECT 4.81 37.1 5.02 37.17 ;
    RECT 5.27 36.38 5.48 36.45 ;
    RECT 5.27 36.74 5.48 36.81 ;
    RECT 5.27 37.1 5.48 37.17 ;
    RECT 1.49 35.66 1.7 35.73 ;
    RECT 1.49 36.02 1.7 36.09 ;
    RECT 1.49 36.38 1.7 36.45 ;
    RECT 1.95 35.66 2.16 35.73 ;
    RECT 1.95 36.02 2.16 36.09 ;
    RECT 1.95 36.38 2.16 36.45 ;
    RECT 14.585 36.02 14.655 36.09 ;
    RECT 0.4 36.02 0.47 36.09 ;
    RECT 11.45 35.66 11.66 35.73 ;
    RECT 11.45 36.02 11.66 36.09 ;
    RECT 11.45 36.38 11.66 36.45 ;
    RECT 11.91 35.66 12.12 35.73 ;
    RECT 11.91 36.02 12.12 36.09 ;
    RECT 11.91 36.38 12.12 36.45 ;
    RECT 8.13 35.66 8.34 35.73 ;
    RECT 8.13 36.02 8.34 36.09 ;
    RECT 8.13 36.38 8.34 36.45 ;
    RECT 8.59 35.66 8.8 35.73 ;
    RECT 8.59 36.02 8.8 36.09 ;
    RECT 8.59 36.38 8.8 36.45 ;
    RECT 4.81 35.66 5.02 35.73 ;
    RECT 4.81 36.02 5.02 36.09 ;
    RECT 4.81 36.38 5.02 36.45 ;
    RECT 5.27 35.66 5.48 35.73 ;
    RECT 5.27 36.02 5.48 36.09 ;
    RECT 5.27 36.38 5.48 36.45 ;
    RECT 1.49 34.94 1.7 35.01 ;
    RECT 1.49 35.3 1.7 35.37 ;
    RECT 1.49 35.66 1.7 35.73 ;
    RECT 1.95 34.94 2.16 35.01 ;
    RECT 1.95 35.3 2.16 35.37 ;
    RECT 1.95 35.66 2.16 35.73 ;
    RECT 14.585 35.3 14.655 35.37 ;
    RECT 0.4 35.3 0.47 35.37 ;
    RECT 11.45 34.94 11.66 35.01 ;
    RECT 11.45 35.3 11.66 35.37 ;
    RECT 11.45 35.66 11.66 35.73 ;
    RECT 11.91 34.94 12.12 35.01 ;
    RECT 11.91 35.3 12.12 35.37 ;
    RECT 11.91 35.66 12.12 35.73 ;
    RECT 8.13 34.94 8.34 35.01 ;
    RECT 8.13 35.3 8.34 35.37 ;
    RECT 8.13 35.66 8.34 35.73 ;
    RECT 8.59 34.94 8.8 35.01 ;
    RECT 8.59 35.3 8.8 35.37 ;
    RECT 8.59 35.66 8.8 35.73 ;
    RECT 4.81 34.94 5.02 35.01 ;
    RECT 4.81 35.3 5.02 35.37 ;
    RECT 4.81 35.66 5.02 35.73 ;
    RECT 5.27 34.94 5.48 35.01 ;
    RECT 5.27 35.3 5.48 35.37 ;
    RECT 5.27 35.66 5.48 35.73 ;
    RECT 1.49 32.06 1.7 32.13 ;
    RECT 1.49 32.42 1.7 32.49 ;
    RECT 1.49 32.78 1.7 32.85 ;
    RECT 1.95 32.06 2.16 32.13 ;
    RECT 1.95 32.42 2.16 32.49 ;
    RECT 1.95 32.78 2.16 32.85 ;
    RECT 14.585 32.42 14.655 32.49 ;
    RECT 0.4 32.42 0.47 32.49 ;
    RECT 11.45 32.06 11.66 32.13 ;
    RECT 11.45 32.42 11.66 32.49 ;
    RECT 11.45 32.78 11.66 32.85 ;
    RECT 11.91 32.06 12.12 32.13 ;
    RECT 11.91 32.42 12.12 32.49 ;
    RECT 11.91 32.78 12.12 32.85 ;
    RECT 8.13 32.06 8.34 32.13 ;
    RECT 8.13 32.42 8.34 32.49 ;
    RECT 8.13 32.78 8.34 32.85 ;
    RECT 8.59 32.06 8.8 32.13 ;
    RECT 8.59 32.42 8.8 32.49 ;
    RECT 8.59 32.78 8.8 32.85 ;
    RECT 4.81 32.06 5.02 32.13 ;
    RECT 4.81 32.42 5.02 32.49 ;
    RECT 4.81 32.78 5.02 32.85 ;
    RECT 5.27 32.06 5.48 32.13 ;
    RECT 5.27 32.42 5.48 32.49 ;
    RECT 5.27 32.78 5.48 32.85 ;
    RECT 1.49 31.34 1.7 31.41 ;
    RECT 1.49 31.7 1.7 31.77 ;
    RECT 1.49 32.06 1.7 32.13 ;
    RECT 1.95 31.34 2.16 31.41 ;
    RECT 1.95 31.7 2.16 31.77 ;
    RECT 1.95 32.06 2.16 32.13 ;
    RECT 14.585 31.7 14.655 31.77 ;
    RECT 0.4 31.7 0.47 31.77 ;
    RECT 11.45 31.34 11.66 31.41 ;
    RECT 11.45 31.7 11.66 31.77 ;
    RECT 11.45 32.06 11.66 32.13 ;
    RECT 11.91 31.34 12.12 31.41 ;
    RECT 11.91 31.7 12.12 31.77 ;
    RECT 11.91 32.06 12.12 32.13 ;
    RECT 8.13 31.34 8.34 31.41 ;
    RECT 8.13 31.7 8.34 31.77 ;
    RECT 8.13 32.06 8.34 32.13 ;
    RECT 8.59 31.34 8.8 31.41 ;
    RECT 8.59 31.7 8.8 31.77 ;
    RECT 8.59 32.06 8.8 32.13 ;
    RECT 4.81 31.34 5.02 31.41 ;
    RECT 4.81 31.7 5.02 31.77 ;
    RECT 4.81 32.06 5.02 32.13 ;
    RECT 5.27 31.34 5.48 31.41 ;
    RECT 5.27 31.7 5.48 31.77 ;
    RECT 5.27 32.06 5.48 32.13 ;
    RECT 1.49 30.62 1.7 30.69 ;
    RECT 1.49 30.98 1.7 31.05 ;
    RECT 1.49 31.34 1.7 31.41 ;
    RECT 1.95 30.62 2.16 30.69 ;
    RECT 1.95 30.98 2.16 31.05 ;
    RECT 1.95 31.34 2.16 31.41 ;
    RECT 14.585 30.98 14.655 31.05 ;
    RECT 0.4 30.98 0.47 31.05 ;
    RECT 11.45 30.62 11.66 30.69 ;
    RECT 11.45 30.98 11.66 31.05 ;
    RECT 11.45 31.34 11.66 31.41 ;
    RECT 11.91 30.62 12.12 30.69 ;
    RECT 11.91 30.98 12.12 31.05 ;
    RECT 11.91 31.34 12.12 31.41 ;
    RECT 8.13 30.62 8.34 30.69 ;
    RECT 8.13 30.98 8.34 31.05 ;
    RECT 8.13 31.34 8.34 31.41 ;
    RECT 8.59 30.62 8.8 30.69 ;
    RECT 8.59 30.98 8.8 31.05 ;
    RECT 8.59 31.34 8.8 31.41 ;
    RECT 4.81 30.62 5.02 30.69 ;
    RECT 4.81 30.98 5.02 31.05 ;
    RECT 4.81 31.34 5.02 31.41 ;
    RECT 5.27 30.62 5.48 30.69 ;
    RECT 5.27 30.98 5.48 31.05 ;
    RECT 5.27 31.34 5.48 31.41 ;
    RECT 1.49 29.9 1.7 29.97 ;
    RECT 1.49 30.26 1.7 30.33 ;
    RECT 1.49 30.62 1.7 30.69 ;
    RECT 1.95 29.9 2.16 29.97 ;
    RECT 1.95 30.26 2.16 30.33 ;
    RECT 1.95 30.62 2.16 30.69 ;
    RECT 14.585 30.26 14.655 30.33 ;
    RECT 0.4 30.26 0.47 30.33 ;
    RECT 11.45 29.9 11.66 29.97 ;
    RECT 11.45 30.26 11.66 30.33 ;
    RECT 11.45 30.62 11.66 30.69 ;
    RECT 11.91 29.9 12.12 29.97 ;
    RECT 11.91 30.26 12.12 30.33 ;
    RECT 11.91 30.62 12.12 30.69 ;
    RECT 8.13 29.9 8.34 29.97 ;
    RECT 8.13 30.26 8.34 30.33 ;
    RECT 8.13 30.62 8.34 30.69 ;
    RECT 8.59 29.9 8.8 29.97 ;
    RECT 8.59 30.26 8.8 30.33 ;
    RECT 8.59 30.62 8.8 30.69 ;
    RECT 4.81 29.9 5.02 29.97 ;
    RECT 4.81 30.26 5.02 30.33 ;
    RECT 4.81 30.62 5.02 30.69 ;
    RECT 5.27 29.9 5.48 29.97 ;
    RECT 5.27 30.26 5.48 30.33 ;
    RECT 5.27 30.62 5.48 30.69 ;
    RECT 1.49 32.78 1.7 32.85 ;
    RECT 1.49 33.14 1.7 33.21 ;
    RECT 1.49 33.5 1.7 33.57 ;
    RECT 1.95 32.78 2.16 32.85 ;
    RECT 1.95 33.14 2.16 33.21 ;
    RECT 1.95 33.5 2.16 33.57 ;
    RECT 0.4 33.14 0.47 33.21 ;
    RECT 11.45 32.78 11.66 32.85 ;
    RECT 11.45 33.14 11.66 33.21 ;
    RECT 11.45 33.5 11.66 33.57 ;
    RECT 11.91 32.78 12.12 32.85 ;
    RECT 11.91 33.14 12.12 33.21 ;
    RECT 11.91 33.5 12.12 33.57 ;
    RECT 8.13 32.78 8.34 32.85 ;
    RECT 8.13 33.14 8.34 33.21 ;
    RECT 8.13 33.5 8.34 33.57 ;
    RECT 8.59 32.78 8.8 32.85 ;
    RECT 8.59 33.14 8.8 33.21 ;
    RECT 8.59 33.5 8.8 33.57 ;
    RECT 14.585 33.14 14.655 33.21 ;
    RECT 4.81 32.78 5.02 32.85 ;
    RECT 4.81 33.14 5.02 33.21 ;
    RECT 4.81 33.5 5.02 33.57 ;
    RECT 5.27 32.78 5.48 32.85 ;
    RECT 5.27 33.14 5.48 33.21 ;
    RECT 5.27 33.5 5.48 33.57 ;
    RECT 14.795 46.24 14.865 46.31 ;
    RECT 14.585 45.98 14.655 46.05 ;
    RECT 12.4 46.24 12.61 46.31 ;
    RECT 12.4 46.5 12.61 46.57 ;
    RECT 0.19 46.24 0.26 46.31 ;
    RECT 0.4 45.98 0.47 46.05 ;
    RECT 1.95 45.98 2.16 46.05 ;
    RECT 1.49 45.98 1.7 46.05 ;
    RECT 5.27 45.98 5.48 46.05 ;
    RECT 10.985 46.76 11.205 46.83 ;
    RECT 7.665 46.76 7.885 46.83 ;
    RECT 4.81 45.98 5.02 46.05 ;
    RECT 4.345 46.76 4.565 46.83 ;
    RECT 1.025 46.76 1.245 46.83 ;
    RECT 2.44 46.5 2.65 46.57 ;
    RECT 8.59 45.98 8.8 46.05 ;
    RECT 8.13 45.98 8.34 46.05 ;
    RECT 5.76 46.24 5.97 46.31 ;
    RECT 5.76 46.5 5.97 46.57 ;
    RECT 11.91 45.98 12.12 46.05 ;
    RECT 11.45 45.98 11.66 46.05 ;
    RECT 2.44 46.24 2.65 46.31 ;
    RECT 9.08 46.24 9.29 46.31 ;
    RECT 9.08 46.5 9.29 46.57 ;
    RECT 1.49 44.3 1.7 44.37 ;
    RECT 1.49 44.66 1.7 44.73 ;
    RECT 1.49 45.02 1.7 45.09 ;
    RECT 1.95 44.3 2.16 44.37 ;
    RECT 1.95 44.66 2.16 44.73 ;
    RECT 1.95 45.02 2.16 45.09 ;
    RECT 14.585 44.66 14.655 44.73 ;
    RECT 0.4 44.66 0.47 44.73 ;
    RECT 11.45 44.3 11.66 44.37 ;
    RECT 11.45 44.66 11.66 44.73 ;
    RECT 11.45 45.02 11.66 45.09 ;
    RECT 11.91 44.3 12.12 44.37 ;
    RECT 11.91 44.66 12.12 44.73 ;
    RECT 11.91 45.02 12.12 45.09 ;
    RECT 8.13 44.3 8.34 44.37 ;
    RECT 8.13 44.66 8.34 44.73 ;
    RECT 8.13 45.02 8.34 45.09 ;
    RECT 8.59 44.3 8.8 44.37 ;
    RECT 8.59 44.66 8.8 44.73 ;
    RECT 8.59 45.02 8.8 45.09 ;
    RECT 4.81 44.3 5.02 44.37 ;
    RECT 4.81 44.66 5.02 44.73 ;
    RECT 4.81 45.02 5.02 45.09 ;
    RECT 5.27 44.3 5.48 44.37 ;
    RECT 5.27 44.66 5.48 44.73 ;
    RECT 5.27 45.02 5.48 45.09 ;
    RECT 1.49 33.5 1.7 33.57 ;
    RECT 1.49 33.86 1.7 33.93 ;
    RECT 1.49 34.22 1.7 34.29 ;
    RECT 1.95 33.5 2.16 33.57 ;
    RECT 1.95 33.86 2.16 33.93 ;
    RECT 1.95 34.22 2.16 34.29 ;
    RECT 0.4 33.86 0.47 33.93 ;
    RECT 14.585 33.86 14.655 33.93 ;
    RECT 11.45 33.5 11.66 33.57 ;
    RECT 11.45 33.86 11.66 33.93 ;
    RECT 11.45 34.22 11.66 34.29 ;
    RECT 11.91 33.5 12.12 33.57 ;
    RECT 11.91 33.86 12.12 33.93 ;
    RECT 11.91 34.22 12.12 34.29 ;
    RECT 8.13 33.5 8.34 33.57 ;
    RECT 8.13 33.86 8.34 33.93 ;
    RECT 8.13 34.22 8.34 34.29 ;
    RECT 8.59 33.5 8.8 33.57 ;
    RECT 8.59 33.86 8.8 33.93 ;
    RECT 8.59 34.22 8.8 34.29 ;
    RECT 4.81 33.5 5.02 33.57 ;
    RECT 4.81 33.86 5.02 33.93 ;
    RECT 4.81 34.22 5.02 34.29 ;
    RECT 5.27 33.5 5.48 33.57 ;
    RECT 5.27 33.86 5.48 33.93 ;
    RECT 5.27 34.22 5.48 34.29 ;
    RECT 1.49 43.58 1.7 43.65 ;
    RECT 1.49 43.94 1.7 44.01 ;
    RECT 1.49 44.3 1.7 44.37 ;
    RECT 1.95 43.58 2.16 43.65 ;
    RECT 1.95 43.94 2.16 44.01 ;
    RECT 1.95 44.3 2.16 44.37 ;
    RECT 14.585 43.94 14.655 44.01 ;
    RECT 0.4 43.94 0.47 44.01 ;
    RECT 11.45 43.58 11.66 43.65 ;
    RECT 11.45 43.94 11.66 44.01 ;
    RECT 11.45 44.3 11.66 44.37 ;
    RECT 11.91 43.58 12.12 43.65 ;
    RECT 11.91 43.94 12.12 44.01 ;
    RECT 11.91 44.3 12.12 44.37 ;
    RECT 8.13 43.58 8.34 43.65 ;
    RECT 8.13 43.94 8.34 44.01 ;
    RECT 8.13 44.3 8.34 44.37 ;
    RECT 8.59 43.58 8.8 43.65 ;
    RECT 8.59 43.94 8.8 44.01 ;
    RECT 8.59 44.3 8.8 44.37 ;
    RECT 4.81 43.58 5.02 43.65 ;
    RECT 4.81 43.94 5.02 44.01 ;
    RECT 4.81 44.3 5.02 44.37 ;
    RECT 5.27 43.58 5.48 43.65 ;
    RECT 5.27 43.94 5.48 44.01 ;
    RECT 5.27 44.3 5.48 44.37 ;
    RECT 1.49 42.86 1.7 42.93 ;
    RECT 1.49 43.22 1.7 43.29 ;
    RECT 1.49 43.58 1.7 43.65 ;
    RECT 1.95 42.86 2.16 42.93 ;
    RECT 1.95 43.22 2.16 43.29 ;
    RECT 1.95 43.58 2.16 43.65 ;
    RECT 14.585 43.22 14.655 43.29 ;
    RECT 0.4 43.22 0.47 43.29 ;
    RECT 11.45 42.86 11.66 42.93 ;
    RECT 11.45 43.22 11.66 43.29 ;
    RECT 11.45 43.58 11.66 43.65 ;
    RECT 11.91 42.86 12.12 42.93 ;
    RECT 11.91 43.22 12.12 43.29 ;
    RECT 11.91 43.58 12.12 43.65 ;
    RECT 8.13 42.86 8.34 42.93 ;
    RECT 8.13 43.22 8.34 43.29 ;
    RECT 8.13 43.58 8.34 43.65 ;
    RECT 8.59 42.86 8.8 42.93 ;
    RECT 8.59 43.22 8.8 43.29 ;
    RECT 8.59 43.58 8.8 43.65 ;
    RECT 4.81 42.86 5.02 42.93 ;
    RECT 4.81 43.22 5.02 43.29 ;
    RECT 4.81 43.58 5.02 43.65 ;
    RECT 5.27 42.86 5.48 42.93 ;
    RECT 5.27 43.22 5.48 43.29 ;
    RECT 5.27 43.58 5.48 43.65 ;
    RECT 1.49 42.14 1.7 42.21 ;
    RECT 1.49 42.5 1.7 42.57 ;
    RECT 1.49 42.86 1.7 42.93 ;
    RECT 1.95 42.14 2.16 42.21 ;
    RECT 1.95 42.5 2.16 42.57 ;
    RECT 1.95 42.86 2.16 42.93 ;
    RECT 14.585 42.5 14.655 42.57 ;
    RECT 0.4 42.5 0.47 42.57 ;
    RECT 11.45 42.14 11.66 42.21 ;
    RECT 11.45 42.5 11.66 42.57 ;
    RECT 11.45 42.86 11.66 42.93 ;
    RECT 11.91 42.14 12.12 42.21 ;
    RECT 11.91 42.5 12.12 42.57 ;
    RECT 11.91 42.86 12.12 42.93 ;
    RECT 8.13 42.14 8.34 42.21 ;
    RECT 8.13 42.5 8.34 42.57 ;
    RECT 8.13 42.86 8.34 42.93 ;
    RECT 8.59 42.14 8.8 42.21 ;
    RECT 8.59 42.5 8.8 42.57 ;
    RECT 8.59 42.86 8.8 42.93 ;
    RECT 4.81 42.14 5.02 42.21 ;
    RECT 4.81 42.5 5.02 42.57 ;
    RECT 4.81 42.86 5.02 42.93 ;
    RECT 5.27 42.14 5.48 42.21 ;
    RECT 5.27 42.5 5.48 42.57 ;
    RECT 5.27 42.86 5.48 42.93 ;
    RECT 1.49 41.42 1.7 41.49 ;
    RECT 1.49 41.78 1.7 41.85 ;
    RECT 1.49 42.14 1.7 42.21 ;
    RECT 1.95 41.42 2.16 41.49 ;
    RECT 1.95 41.78 2.16 41.85 ;
    RECT 1.95 42.14 2.16 42.21 ;
    RECT 14.585 41.78 14.655 41.85 ;
    RECT 0.4 41.78 0.47 41.85 ;
    RECT 11.45 41.42 11.66 41.49 ;
    RECT 11.45 41.78 11.66 41.85 ;
    RECT 11.45 42.14 11.66 42.21 ;
    RECT 11.91 41.42 12.12 41.49 ;
    RECT 11.91 41.78 12.12 41.85 ;
    RECT 11.91 42.14 12.12 42.21 ;
    RECT 8.13 41.42 8.34 41.49 ;
    RECT 8.13 41.78 8.34 41.85 ;
    RECT 8.13 42.14 8.34 42.21 ;
    RECT 8.59 41.42 8.8 41.49 ;
    RECT 8.59 41.78 8.8 41.85 ;
    RECT 8.59 42.14 8.8 42.21 ;
    RECT 4.81 41.42 5.02 41.49 ;
    RECT 4.81 41.78 5.02 41.85 ;
    RECT 4.81 42.14 5.02 42.21 ;
    RECT 5.27 41.42 5.48 41.49 ;
    RECT 5.27 41.78 5.48 41.85 ;
    RECT 5.27 42.14 5.48 42.21 ;
    RECT 1.49 40.7 1.7 40.77 ;
    RECT 1.49 41.06 1.7 41.13 ;
    RECT 1.49 41.42 1.7 41.49 ;
    RECT 1.95 40.7 2.16 40.77 ;
    RECT 1.95 41.06 2.16 41.13 ;
    RECT 1.95 41.42 2.16 41.49 ;
    RECT 14.585 41.06 14.655 41.13 ;
    RECT 0.4 41.06 0.47 41.13 ;
    RECT 11.45 40.7 11.66 40.77 ;
    RECT 11.45 41.06 11.66 41.13 ;
    RECT 11.45 41.42 11.66 41.49 ;
    RECT 11.91 40.7 12.12 40.77 ;
    RECT 11.91 41.06 12.12 41.13 ;
    RECT 11.91 41.42 12.12 41.49 ;
    RECT 8.13 40.7 8.34 40.77 ;
    RECT 8.13 41.06 8.34 41.13 ;
    RECT 8.13 41.42 8.34 41.49 ;
    RECT 8.59 40.7 8.8 40.77 ;
    RECT 8.59 41.06 8.8 41.13 ;
    RECT 8.59 41.42 8.8 41.49 ;
    RECT 4.81 40.7 5.02 40.77 ;
    RECT 4.81 41.06 5.02 41.13 ;
    RECT 4.81 41.42 5.02 41.49 ;
    RECT 5.27 40.7 5.48 40.77 ;
    RECT 5.27 41.06 5.48 41.13 ;
    RECT 5.27 41.42 5.48 41.49 ;
    RECT 1.49 39.98 1.7 40.05 ;
    RECT 1.49 40.34 1.7 40.41 ;
    RECT 1.49 40.7 1.7 40.77 ;
    RECT 1.95 39.98 2.16 40.05 ;
    RECT 1.95 40.34 2.16 40.41 ;
    RECT 1.95 40.7 2.16 40.77 ;
    RECT 14.585 40.34 14.655 40.41 ;
    RECT 0.4 40.34 0.47 40.41 ;
    RECT 11.45 39.98 11.66 40.05 ;
    RECT 11.45 40.34 11.66 40.41 ;
    RECT 11.45 40.7 11.66 40.77 ;
    RECT 11.91 39.98 12.12 40.05 ;
    RECT 11.91 40.34 12.12 40.41 ;
    RECT 11.91 40.7 12.12 40.77 ;
    RECT 8.13 39.98 8.34 40.05 ;
    RECT 8.13 40.34 8.34 40.41 ;
    RECT 8.13 40.7 8.34 40.77 ;
    RECT 8.59 39.98 8.8 40.05 ;
    RECT 8.59 40.34 8.8 40.41 ;
    RECT 8.59 40.7 8.8 40.77 ;
    RECT 4.81 39.98 5.02 40.05 ;
    RECT 4.81 40.34 5.02 40.41 ;
    RECT 4.81 40.7 5.02 40.77 ;
    RECT 5.27 39.98 5.48 40.05 ;
    RECT 5.27 40.34 5.48 40.41 ;
    RECT 5.27 40.7 5.48 40.77 ;
    RECT 1.49 29.18 1.7 29.25 ;
    RECT 1.49 29.54 1.7 29.61 ;
    RECT 1.49 29.9 1.7 29.97 ;
    RECT 1.95 29.18 2.16 29.25 ;
    RECT 1.95 29.54 2.16 29.61 ;
    RECT 1.95 29.9 2.16 29.97 ;
    RECT 14.585 29.54 14.655 29.61 ;
    RECT 0.4 29.54 0.47 29.61 ;
    RECT 11.45 29.18 11.66 29.25 ;
    RECT 11.45 29.54 11.66 29.61 ;
    RECT 11.45 29.9 11.66 29.97 ;
    RECT 11.91 29.18 12.12 29.25 ;
    RECT 11.91 29.54 12.12 29.61 ;
    RECT 11.91 29.9 12.12 29.97 ;
    RECT 8.13 29.18 8.34 29.25 ;
    RECT 8.13 29.54 8.34 29.61 ;
    RECT 8.13 29.9 8.34 29.97 ;
    RECT 8.59 29.18 8.8 29.25 ;
    RECT 8.59 29.54 8.8 29.61 ;
    RECT 8.59 29.9 8.8 29.97 ;
    RECT 4.81 29.18 5.02 29.25 ;
    RECT 4.81 29.54 5.02 29.61 ;
    RECT 4.81 29.9 5.02 29.97 ;
    RECT 5.27 29.18 5.48 29.25 ;
    RECT 5.27 29.54 5.48 29.61 ;
    RECT 5.27 29.9 5.48 29.97 ;
    RECT 1.49 39.26 1.7 39.33 ;
    RECT 1.49 39.62 1.7 39.69 ;
    RECT 1.49 39.98 1.7 40.05 ;
    RECT 1.95 39.26 2.16 39.33 ;
    RECT 1.95 39.62 2.16 39.69 ;
    RECT 1.95 39.98 2.16 40.05 ;
    RECT 14.585 39.62 14.655 39.69 ;
    RECT 0.4 39.62 0.47 39.69 ;
    RECT 11.45 39.26 11.66 39.33 ;
    RECT 11.45 39.62 11.66 39.69 ;
    RECT 11.45 39.98 11.66 40.05 ;
    RECT 11.91 39.26 12.12 39.33 ;
    RECT 11.91 39.62 12.12 39.69 ;
    RECT 11.91 39.98 12.12 40.05 ;
    RECT 8.13 39.26 8.34 39.33 ;
    RECT 8.13 39.62 8.34 39.69 ;
    RECT 8.13 39.98 8.34 40.05 ;
    RECT 8.59 39.26 8.8 39.33 ;
    RECT 8.59 39.62 8.8 39.69 ;
    RECT 8.59 39.98 8.8 40.05 ;
    RECT 4.81 39.26 5.02 39.33 ;
    RECT 4.81 39.62 5.02 39.69 ;
    RECT 4.81 39.98 5.02 40.05 ;
    RECT 5.27 39.26 5.48 39.33 ;
    RECT 5.27 39.62 5.48 39.69 ;
    RECT 5.27 39.98 5.48 40.05 ;
    RECT 1.49 28.46 1.7 28.53 ;
    RECT 1.49 28.82 1.7 28.89 ;
    RECT 1.49 29.18 1.7 29.25 ;
    RECT 1.95 28.46 2.16 28.53 ;
    RECT 1.95 28.82 2.16 28.89 ;
    RECT 1.95 29.18 2.16 29.25 ;
    RECT 14.585 28.82 14.655 28.89 ;
    RECT 0.4 28.82 0.47 28.89 ;
    RECT 11.45 28.46 11.66 28.53 ;
    RECT 11.45 28.82 11.66 28.89 ;
    RECT 11.45 29.18 11.66 29.25 ;
    RECT 11.91 28.46 12.12 28.53 ;
    RECT 11.91 28.82 12.12 28.89 ;
    RECT 11.91 29.18 12.12 29.25 ;
    RECT 8.13 28.46 8.34 28.53 ;
    RECT 8.13 28.82 8.34 28.89 ;
    RECT 8.13 29.18 8.34 29.25 ;
    RECT 8.59 28.46 8.8 28.53 ;
    RECT 8.59 28.82 8.8 28.89 ;
    RECT 8.59 29.18 8.8 29.25 ;
    RECT 4.81 28.46 5.02 28.53 ;
    RECT 4.81 28.82 5.02 28.89 ;
    RECT 4.81 29.18 5.02 29.25 ;
    RECT 5.27 28.46 5.48 28.53 ;
    RECT 5.27 28.82 5.48 28.89 ;
    RECT 5.27 29.18 5.48 29.25 ;
    RECT 1.49 38.54 1.7 38.61 ;
    RECT 1.49 38.9 1.7 38.97 ;
    RECT 1.49 39.26 1.7 39.33 ;
    RECT 1.95 38.54 2.16 38.61 ;
    RECT 1.95 38.9 2.16 38.97 ;
    RECT 1.95 39.26 2.16 39.33 ;
    RECT 14.585 38.9 14.655 38.97 ;
    RECT 0.4 38.9 0.47 38.97 ;
    RECT 11.45 38.54 11.66 38.61 ;
    RECT 11.45 38.9 11.66 38.97 ;
    RECT 11.45 39.26 11.66 39.33 ;
    RECT 11.91 38.54 12.12 38.61 ;
    RECT 11.91 38.9 12.12 38.97 ;
    RECT 11.91 39.26 12.12 39.33 ;
    RECT 8.13 38.54 8.34 38.61 ;
    RECT 8.13 38.9 8.34 38.97 ;
    RECT 8.13 39.26 8.34 39.33 ;
    RECT 8.59 38.54 8.8 38.61 ;
    RECT 8.59 38.9 8.8 38.97 ;
    RECT 8.59 39.26 8.8 39.33 ;
    RECT 4.81 38.54 5.02 38.61 ;
    RECT 4.81 38.9 5.02 38.97 ;
    RECT 4.81 39.26 5.02 39.33 ;
    RECT 5.27 38.54 5.48 38.61 ;
    RECT 5.27 38.9 5.48 38.97 ;
    RECT 5.27 39.26 5.48 39.33 ;
    RECT 1.49 27.74 1.7 27.81 ;
    RECT 1.49 28.1 1.7 28.17 ;
    RECT 1.49 28.46 1.7 28.53 ;
    RECT 1.95 27.74 2.16 27.81 ;
    RECT 1.95 28.1 2.16 28.17 ;
    RECT 1.95 28.46 2.16 28.53 ;
    RECT 14.585 28.1 14.655 28.17 ;
    RECT 0.4 28.1 0.47 28.17 ;
    RECT 11.45 27.74 11.66 27.81 ;
    RECT 11.45 28.1 11.66 28.17 ;
    RECT 11.45 28.46 11.66 28.53 ;
    RECT 11.91 27.74 12.12 27.81 ;
    RECT 11.91 28.1 12.12 28.17 ;
    RECT 11.91 28.46 12.12 28.53 ;
    RECT 8.13 27.74 8.34 27.81 ;
    RECT 8.13 28.1 8.34 28.17 ;
    RECT 8.13 28.46 8.34 28.53 ;
    RECT 8.59 27.74 8.8 27.81 ;
    RECT 8.59 28.1 8.8 28.17 ;
    RECT 8.59 28.46 8.8 28.53 ;
    RECT 4.81 27.74 5.02 27.81 ;
    RECT 4.81 28.1 5.02 28.17 ;
    RECT 4.81 28.46 5.02 28.53 ;
    RECT 5.27 27.74 5.48 27.81 ;
    RECT 5.27 28.1 5.48 28.17 ;
    RECT 5.27 28.46 5.48 28.53 ;
    RECT 1.49 37.82 1.7 37.89 ;
    RECT 1.49 38.18 1.7 38.25 ;
    RECT 1.49 38.54 1.7 38.61 ;
    RECT 1.95 37.82 2.16 37.89 ;
    RECT 1.95 38.18 2.16 38.25 ;
    RECT 1.95 38.54 2.16 38.61 ;
    RECT 14.585 38.18 14.655 38.25 ;
    RECT 0.4 38.18 0.47 38.25 ;
    RECT 11.45 37.82 11.66 37.89 ;
    RECT 11.45 38.18 11.66 38.25 ;
    RECT 11.45 38.54 11.66 38.61 ;
    RECT 11.91 37.82 12.12 37.89 ;
    RECT 11.91 38.18 12.12 38.25 ;
    RECT 11.91 38.54 12.12 38.61 ;
    RECT 8.13 37.82 8.34 37.89 ;
    RECT 8.13 38.18 8.34 38.25 ;
    RECT 8.13 38.54 8.34 38.61 ;
    RECT 8.59 37.82 8.8 37.89 ;
    RECT 8.59 38.18 8.8 38.25 ;
    RECT 8.59 38.54 8.8 38.61 ;
    RECT 4.81 37.82 5.02 37.89 ;
    RECT 4.81 38.18 5.02 38.25 ;
    RECT 4.81 38.54 5.02 38.61 ;
    RECT 5.27 37.82 5.48 37.89 ;
    RECT 5.27 38.18 5.48 38.25 ;
    RECT 5.27 38.54 5.48 38.61 ;
    RECT 1.49 27.02 1.7 27.09 ;
    RECT 1.49 27.38 1.7 27.45 ;
    RECT 1.49 27.74 1.7 27.81 ;
    RECT 1.95 27.02 2.16 27.09 ;
    RECT 1.95 27.38 2.16 27.45 ;
    RECT 1.95 27.74 2.16 27.81 ;
    RECT 14.585 27.38 14.655 27.45 ;
    RECT 0.4 27.38 0.47 27.45 ;
    RECT 11.45 27.02 11.66 27.09 ;
    RECT 11.45 27.38 11.66 27.45 ;
    RECT 11.45 27.74 11.66 27.81 ;
    RECT 11.91 27.02 12.12 27.09 ;
    RECT 11.91 27.38 12.12 27.45 ;
    RECT 11.91 27.74 12.12 27.81 ;
    RECT 8.13 27.02 8.34 27.09 ;
    RECT 8.13 27.38 8.34 27.45 ;
    RECT 8.13 27.74 8.34 27.81 ;
    RECT 8.59 27.02 8.8 27.09 ;
    RECT 8.59 27.38 8.8 27.45 ;
    RECT 8.59 27.74 8.8 27.81 ;
    RECT 4.81 27.02 5.02 27.09 ;
    RECT 4.81 27.38 5.02 27.45 ;
    RECT 4.81 27.74 5.02 27.81 ;
    RECT 5.27 27.02 5.48 27.09 ;
    RECT 5.27 27.38 5.48 27.45 ;
    RECT 5.27 27.74 5.48 27.81 ;
    RECT 1.49 37.1 1.7 37.17 ;
    RECT 1.49 37.46 1.7 37.53 ;
    RECT 1.49 37.82 1.7 37.89 ;
    RECT 1.95 37.1 2.16 37.17 ;
    RECT 1.95 37.46 2.16 37.53 ;
    RECT 1.95 37.82 2.16 37.89 ;
    RECT 14.585 37.46 14.655 37.53 ;
    RECT 0.4 37.46 0.47 37.53 ;
    RECT 11.45 37.1 11.66 37.17 ;
    RECT 11.45 37.46 11.66 37.53 ;
    RECT 11.45 37.82 11.66 37.89 ;
    RECT 11.91 37.1 12.12 37.17 ;
    RECT 11.91 37.46 12.12 37.53 ;
    RECT 11.91 37.82 12.12 37.89 ;
    RECT 8.13 37.1 8.34 37.17 ;
    RECT 8.13 37.46 8.34 37.53 ;
    RECT 8.13 37.82 8.34 37.89 ;
    RECT 8.59 37.1 8.8 37.17 ;
    RECT 8.59 37.46 8.8 37.53 ;
    RECT 8.59 37.82 8.8 37.89 ;
    RECT 4.81 37.1 5.02 37.17 ;
    RECT 4.81 37.46 5.02 37.53 ;
    RECT 4.81 37.82 5.02 37.89 ;
    RECT 5.27 37.1 5.48 37.17 ;
    RECT 5.27 37.46 5.48 37.53 ;
    RECT 5.27 37.82 5.48 37.89 ;
    RECT 1.49 26.3 1.7 26.37 ;
    RECT 1.49 26.66 1.7 26.73 ;
    RECT 1.49 27.02 1.7 27.09 ;
    RECT 1.95 26.3 2.16 26.37 ;
    RECT 1.95 26.66 2.16 26.73 ;
    RECT 1.95 27.02 2.16 27.09 ;
    RECT 14.585 26.66 14.655 26.73 ;
    RECT 0.4 26.66 0.47 26.73 ;
    RECT 11.45 26.3 11.66 26.37 ;
    RECT 11.45 26.66 11.66 26.73 ;
    RECT 11.45 27.02 11.66 27.09 ;
    RECT 11.91 26.3 12.12 26.37 ;
    RECT 11.91 26.66 12.12 26.73 ;
    RECT 11.91 27.02 12.12 27.09 ;
    RECT 8.13 26.3 8.34 26.37 ;
    RECT 8.13 26.66 8.34 26.73 ;
    RECT 8.13 27.02 8.34 27.09 ;
    RECT 8.59 26.3 8.8 26.37 ;
    RECT 8.59 26.66 8.8 26.73 ;
    RECT 8.59 27.02 8.8 27.09 ;
    RECT 4.81 26.3 5.02 26.37 ;
    RECT 4.81 26.66 5.02 26.73 ;
    RECT 4.81 27.02 5.02 27.09 ;
    RECT 5.27 26.3 5.48 26.37 ;
    RECT 5.27 26.66 5.48 26.73 ;
    RECT 5.27 27.02 5.48 27.09 ;
    RECT 1.49 25.58 1.7 25.65 ;
    RECT 1.49 25.94 1.7 26.01 ;
    RECT 1.49 26.3 1.7 26.37 ;
    RECT 1.95 25.58 2.16 25.65 ;
    RECT 1.95 25.94 2.16 26.01 ;
    RECT 1.95 26.3 2.16 26.37 ;
    RECT 14.585 25.94 14.655 26.01 ;
    RECT 0.4 25.94 0.47 26.01 ;
    RECT 11.45 25.58 11.66 25.65 ;
    RECT 11.45 25.94 11.66 26.01 ;
    RECT 11.45 26.3 11.66 26.37 ;
    RECT 11.91 25.58 12.12 25.65 ;
    RECT 11.91 25.94 12.12 26.01 ;
    RECT 11.91 26.3 12.12 26.37 ;
    RECT 8.13 25.58 8.34 25.65 ;
    RECT 8.13 25.94 8.34 26.01 ;
    RECT 8.13 26.3 8.34 26.37 ;
    RECT 8.59 25.58 8.8 25.65 ;
    RECT 8.59 25.94 8.8 26.01 ;
    RECT 8.59 26.3 8.8 26.37 ;
    RECT 4.81 25.58 5.02 25.65 ;
    RECT 4.81 25.94 5.02 26.01 ;
    RECT 4.81 26.3 5.02 26.37 ;
    RECT 5.27 25.58 5.48 25.65 ;
    RECT 5.27 25.94 5.48 26.01 ;
    RECT 5.27 26.3 5.48 26.37 ;
    RECT 1.49 24.86 1.7 24.93 ;
    RECT 1.49 25.22 1.7 25.29 ;
    RECT 1.49 25.58 1.7 25.65 ;
    RECT 1.95 24.86 2.16 24.93 ;
    RECT 1.95 25.22 2.16 25.29 ;
    RECT 1.95 25.58 2.16 25.65 ;
    RECT 14.585 25.22 14.655 25.29 ;
    RECT 0.4 25.22 0.47 25.29 ;
    RECT 11.45 24.86 11.66 24.93 ;
    RECT 11.45 25.22 11.66 25.29 ;
    RECT 11.45 25.58 11.66 25.65 ;
    RECT 11.91 24.86 12.12 24.93 ;
    RECT 11.91 25.22 12.12 25.29 ;
    RECT 11.91 25.58 12.12 25.65 ;
    RECT 8.13 24.86 8.34 24.93 ;
    RECT 8.13 25.22 8.34 25.29 ;
    RECT 8.13 25.58 8.34 25.65 ;
    RECT 8.59 24.86 8.8 24.93 ;
    RECT 8.59 25.22 8.8 25.29 ;
    RECT 8.59 25.58 8.8 25.65 ;
    RECT 4.81 24.86 5.02 24.93 ;
    RECT 4.81 25.22 5.02 25.29 ;
    RECT 4.81 25.58 5.02 25.65 ;
    RECT 5.27 24.86 5.48 24.93 ;
    RECT 5.27 25.22 5.48 25.29 ;
    RECT 5.27 25.58 5.48 25.65 ;
    RECT 1.49 24.14 1.7 24.21 ;
    RECT 1.49 24.5 1.7 24.57 ;
    RECT 1.49 24.86 1.7 24.93 ;
    RECT 1.95 24.14 2.16 24.21 ;
    RECT 1.95 24.5 2.16 24.57 ;
    RECT 1.95 24.86 2.16 24.93 ;
    RECT 14.585 24.5 14.655 24.57 ;
    RECT 0.4 24.5 0.47 24.57 ;
    RECT 11.45 24.14 11.66 24.21 ;
    RECT 11.45 24.5 11.66 24.57 ;
    RECT 11.45 24.86 11.66 24.93 ;
    RECT 11.91 24.14 12.12 24.21 ;
    RECT 11.91 24.5 12.12 24.57 ;
    RECT 11.91 24.86 12.12 24.93 ;
    RECT 8.13 24.14 8.34 24.21 ;
    RECT 8.13 24.5 8.34 24.57 ;
    RECT 8.13 24.86 8.34 24.93 ;
    RECT 8.59 24.14 8.8 24.21 ;
    RECT 8.59 24.5 8.8 24.57 ;
    RECT 8.59 24.86 8.8 24.93 ;
    RECT 4.81 24.14 5.02 24.21 ;
    RECT 4.81 24.5 5.02 24.57 ;
    RECT 4.81 24.86 5.02 24.93 ;
    RECT 5.27 24.14 5.48 24.21 ;
    RECT 5.27 24.5 5.48 24.57 ;
    RECT 5.27 24.86 5.48 24.93 ;
    RECT 1.49 23.42 1.7 23.49 ;
    RECT 1.49 23.78 1.7 23.85 ;
    RECT 1.49 24.14 1.7 24.21 ;
    RECT 1.95 23.42 2.16 23.49 ;
    RECT 1.95 23.78 2.16 23.85 ;
    RECT 1.95 24.14 2.16 24.21 ;
    RECT 14.585 23.78 14.655 23.85 ;
    RECT 0.4 23.78 0.47 23.85 ;
    RECT 11.45 23.42 11.66 23.49 ;
    RECT 11.45 23.78 11.66 23.85 ;
    RECT 11.45 24.14 11.66 24.21 ;
    RECT 11.91 23.42 12.12 23.49 ;
    RECT 11.91 23.78 12.12 23.85 ;
    RECT 11.91 24.14 12.12 24.21 ;
    RECT 8.13 23.42 8.34 23.49 ;
    RECT 8.13 23.78 8.34 23.85 ;
    RECT 8.13 24.14 8.34 24.21 ;
    RECT 8.59 23.42 8.8 23.49 ;
    RECT 8.59 23.78 8.8 23.85 ;
    RECT 8.59 24.14 8.8 24.21 ;
    RECT 4.81 23.42 5.02 23.49 ;
    RECT 4.81 23.78 5.02 23.85 ;
    RECT 4.81 24.14 5.02 24.21 ;
    RECT 5.27 23.42 5.48 23.49 ;
    RECT 5.27 23.78 5.48 23.85 ;
    RECT 5.27 24.14 5.48 24.21 ;
    RECT 11.45 22.7 11.66 22.77 ;
    RECT 11.45 23.06 11.66 23.13 ;
    RECT 11.45 23.42 11.66 23.49 ;
    RECT 11.91 22.7 12.12 22.77 ;
    RECT 11.91 23.06 12.12 23.13 ;
    RECT 11.91 23.42 12.12 23.49 ;
    RECT 14.585 23.06 14.655 23.13 ;
    RECT 1.49 22.7 1.7 22.77 ;
    RECT 1.49 23.06 1.7 23.13 ;
    RECT 1.49 23.42 1.7 23.49 ;
    RECT 1.95 22.7 2.16 22.77 ;
    RECT 1.95 23.06 2.16 23.13 ;
    RECT 1.95 23.42 2.16 23.49 ;
    RECT 0.4 23.06 0.47 23.13 ;
    RECT 8.13 22.7 8.34 22.77 ;
    RECT 8.13 23.06 8.34 23.13 ;
    RECT 8.13 23.42 8.34 23.49 ;
    RECT 8.59 22.7 8.8 22.77 ;
    RECT 8.59 23.06 8.8 23.13 ;
    RECT 8.59 23.42 8.8 23.49 ;
    RECT 4.81 22.7 5.02 22.77 ;
    RECT 4.81 23.06 5.02 23.13 ;
    RECT 4.81 23.42 5.02 23.49 ;
    RECT 5.27 22.7 5.48 22.77 ;
    RECT 5.27 23.06 5.48 23.13 ;
    RECT 5.27 23.42 5.48 23.49 ;
    RECT 33.49 40.25 33.7 40.32 ;
    RECT 21.45 40.247 21.66 40.317 ;
    RECT 16.39 40.34 16.6 40.41 ;
    RECT 34.235 31.607 34.445 31.677 ;
    RECT 34.235 30.162 34.445 30.232 ;
    RECT 34.235 28.732 34.445 28.802 ;
    RECT 39.245 45.38 39.455 45.45 ;
    RECT 33.49 45.29 33.7 45.36 ;
    RECT 21.45 45.287 21.66 45.357 ;
    RECT 29.26 43.127 29.33 43.197 ;
    RECT 39.245 39.62 39.455 39.69 ;
    RECT 34.235 27.267 34.445 27.337 ;
    RECT 26.95 40.967 27.02 41.037 ;
    RECT 34.235 24.405 34.445 24.475 ;
    RECT 34.235 23.69 34.445 23.76 ;
    RECT 16.39 45.38 16.6 45.45 ;
    RECT 33.49 39.53 33.7 39.6 ;
    RECT 21.45 39.527 21.66 39.597 ;
    RECT 16.39 39.62 16.6 39.69 ;
    RECT 29.26 42.407 29.33 42.477 ;
    RECT 27.15 40.247 27.22 40.317 ;
    RECT 39.245 44.66 39.455 44.73 ;
    RECT 33.49 44.57 33.7 44.64 ;
    RECT 33.49 22.975 33.7 23.045 ;
    RECT 31.66 24.405 31.87 24.475 ;
    RECT 21.45 44.567 21.66 44.637 ;
    RECT 30.68 22.975 30.89 23.045 ;
    RECT 36.27 46.152 36.48 46.222 ;
    RECT 25.755 45.287 25.825 45.357 ;
    RECT 19.43 46.152 19.64 46.222 ;
    RECT 25.555 24.4 25.625 24.47 ;
    RECT 22.095 26.557 22.305 26.627 ;
    RECT 22.095 23.685 22.305 23.755 ;
    RECT 22.095 22.97 22.305 23.04 ;
    RECT 39.245 38.9 39.455 38.97 ;
    RECT 33.49 38.81 33.7 38.88 ;
    RECT 16.39 44.66 16.6 44.73 ;
    RECT 21.45 38.807 21.66 38.877 ;
    RECT 29.26 41.687 29.33 41.757 ;
    RECT 25.755 39.527 25.825 39.597 ;
    RECT 29.26 40.967 29.33 41.037 ;
    RECT 16.39 38.9 16.6 38.97 ;
    RECT 39.245 43.94 39.455 44.01 ;
    RECT 33.49 43.85 33.7 43.92 ;
    RECT 25.955 44.567 26.025 44.637 ;
    RECT 21.45 43.847 21.66 43.917 ;
    RECT 21.45 27.297 21.66 27.367 ;
    RECT 21.45 25.832 21.66 25.902 ;
    RECT 29.26 40.247 29.33 40.317 ;
    RECT 39.245 38.18 39.455 38.25 ;
    RECT 33.49 38.09 33.7 38.16 ;
    RECT 16.39 43.94 16.6 44.01 ;
    RECT 21.45 38.087 21.66 38.157 ;
    RECT 25.955 38.807 26.025 38.877 ;
    RECT 26.155 43.847 26.225 43.917 ;
    RECT 16.39 33.86 16.6 33.93 ;
    RECT 16.39 33.14 16.6 33.21 ;
    RECT 16.39 32.42 16.6 32.49 ;
    RECT 16.39 31.7 16.6 31.77 ;
    RECT 16.39 30.98 16.6 31.05 ;
    RECT 16.39 30.26 16.6 30.33 ;
    RECT 39.245 43.22 39.455 43.29 ;
    RECT 33.49 43.13 33.7 43.2 ;
    RECT 16.39 38.18 16.6 38.25 ;
    RECT 16.39 29.54 16.6 29.61 ;
    RECT 16.39 28.82 16.6 28.89 ;
    RECT 16.39 28.1 16.6 28.17 ;
    RECT 16.39 27.38 16.6 27.45 ;
    RECT 16.39 26.66 16.6 26.73 ;
    RECT 16.39 25.94 16.6 26.01 ;
    RECT 26.155 38.087 26.225 38.157 ;
    RECT 16.39 25.22 16.6 25.29 ;
    RECT 16.39 24.5 16.6 24.57 ;
    RECT 16.39 23.78 16.6 23.85 ;
    RECT 16.39 23.06 16.6 23.13 ;
    RECT 29.065 39.527 29.135 39.597 ;
    RECT 21.45 43.127 21.66 43.197 ;
    RECT 16.39 43.22 16.6 43.29 ;
    RECT 39.245 37.46 39.455 37.53 ;
    RECT 33.49 37.37 33.7 37.44 ;
    RECT 39.245 45.827 39.455 45.897 ;
    RECT 21.45 37.367 21.66 37.437 ;
    RECT 35.175 46.335 35.385 46.405 ;
    RECT 26.355 43.127 26.425 43.197 ;
    RECT 29.065 38.807 29.135 38.877 ;
    RECT 39.245 42.5 39.455 42.57 ;
    RECT 33.49 42.41 33.7 42.48 ;
    RECT 16.39 37.46 16.6 37.53 ;
    RECT 34.235 45.827 34.445 45.897 ;
    RECT 26.355 37.367 26.425 37.437 ;
    RECT 33.49 46.335 33.7 46.405 ;
    RECT 31.66 45.827 31.87 45.897 ;
    RECT 21.45 42.407 21.66 42.477 ;
    RECT 16.39 42.5 16.6 42.57 ;
    RECT 39.245 36.74 39.455 36.81 ;
    RECT 30.68 46.335 30.89 46.405 ;
    RECT 33.49 36.65 33.7 36.72 ;
    RECT 28.1 46.335 28.31 46.405 ;
    RECT 25.555 46.335 25.625 46.405 ;
    RECT 24.76 45.827 24.97 45.897 ;
    RECT 21.45 36.647 21.66 36.717 ;
    RECT 26.55 42.407 26.62 42.477 ;
    RECT 23.725 45.827 23.935 45.897 ;
    RECT 26.55 36.647 26.62 36.717 ;
    RECT 29.065 38.087 29.135 38.157 ;
    RECT 39.245 41.78 39.455 41.85 ;
    RECT 33.49 41.69 33.7 41.76 ;
    RECT 21.45 45.827 21.66 45.897 ;
    RECT 16.39 36.74 16.6 36.81 ;
    RECT 16.39 45.827 16.6 45.897 ;
    RECT 26.75 41.687 26.82 41.757 ;
    RECT 21.45 41.687 21.66 41.757 ;
    RECT 16.39 41.78 16.6 41.85 ;
    RECT 39.245 36.02 39.455 36.09 ;
    RECT 33.49 35.93 33.7 36.0 ;
    RECT 15.2 40.7 15.27 41.49 ;
    RECT 15.8 40.7 16.01 40.77 ;
    RECT 15.8 41.055 16.01 41.125 ;
    RECT 15.8 41.42 16.01 41.49 ;
    RECT 16.965 41.145 17.765 41.215 ;
    RECT 19.43 40.97 19.665 41.04 ;
    RECT 20.49 40.97 20.75 41.04 ;
    RECT 22.465 40.97 22.695 41.04 ;
    RECT 23.18 40.97 23.44 41.04 ;
    RECT 24.35 40.97 24.42 41.04 ;
    RECT 27.685 40.97 27.895 41.04 ;
    RECT 28.07 40.97 28.34 41.04 ;
    RECT 32.125 40.97 32.195 41.04 ;
    RECT 32.455 40.97 32.72 41.04 ;
    RECT 34.21 40.97 34.47 41.04 ;
    RECT 34.655 40.97 34.725 41.04 ;
    RECT 35.145 40.97 35.405 41.04 ;
    RECT 36.27 40.97 36.48 41.04 ;
    RECT 38.08 41.145 38.895 41.215 ;
    RECT 39.885 40.7 40.155 40.77 ;
    RECT 39.885 41.055 40.155 41.125 ;
    RECT 39.885 41.42 40.155 41.49 ;
    RECT 26.75 35.927 26.82 35.997 ;
    RECT 15.2 39.98 15.27 40.77 ;
    RECT 15.8 39.98 16.01 40.05 ;
    RECT 15.8 40.335 16.01 40.405 ;
    RECT 15.8 40.7 16.01 40.77 ;
    RECT 16.965 40.425 17.765 40.495 ;
    RECT 19.43 40.25 19.665 40.32 ;
    RECT 20.49 40.25 20.75 40.32 ;
    RECT 22.465 40.25 22.695 40.32 ;
    RECT 23.18 40.25 23.44 40.32 ;
    RECT 24.35 40.25 24.42 40.32 ;
    RECT 27.685 40.25 27.895 40.32 ;
    RECT 28.07 40.25 28.34 40.32 ;
    RECT 32.125 40.25 32.195 40.32 ;
    RECT 32.455 40.25 32.72 40.32 ;
    RECT 34.21 40.25 34.47 40.32 ;
    RECT 34.655 40.25 34.725 40.32 ;
    RECT 35.145 40.25 35.405 40.32 ;
    RECT 36.27 40.25 36.48 40.32 ;
    RECT 38.08 40.425 38.895 40.495 ;
    RECT 39.885 39.98 40.155 40.05 ;
    RECT 39.885 40.335 40.155 40.405 ;
    RECT 39.885 40.7 40.155 40.77 ;
    RECT 15.2 39.26 15.27 40.05 ;
    RECT 15.8 39.26 16.01 39.33 ;
    RECT 15.8 39.615 16.01 39.685 ;
    RECT 15.8 39.98 16.01 40.05 ;
    RECT 16.965 39.705 17.765 39.775 ;
    RECT 19.43 39.53 19.665 39.6 ;
    RECT 20.49 39.53 20.75 39.6 ;
    RECT 22.465 39.53 22.695 39.6 ;
    RECT 23.18 39.53 23.44 39.6 ;
    RECT 24.35 39.53 24.42 39.6 ;
    RECT 27.685 39.53 27.895 39.6 ;
    RECT 28.07 39.53 28.34 39.6 ;
    RECT 32.125 39.53 32.195 39.6 ;
    RECT 32.455 39.53 32.72 39.6 ;
    RECT 34.21 39.53 34.47 39.6 ;
    RECT 34.655 39.53 34.725 39.6 ;
    RECT 35.145 39.53 35.405 39.6 ;
    RECT 36.27 39.53 36.48 39.6 ;
    RECT 38.08 39.705 38.895 39.775 ;
    RECT 39.885 39.26 40.155 39.33 ;
    RECT 39.885 39.615 40.155 39.685 ;
    RECT 39.885 39.98 40.155 40.05 ;
    RECT 15.2 38.54 15.27 39.33 ;
    RECT 15.8 38.54 16.01 38.61 ;
    RECT 15.8 38.895 16.01 38.965 ;
    RECT 15.8 39.26 16.01 39.33 ;
    RECT 16.965 38.985 17.765 39.055 ;
    RECT 19.43 38.81 19.665 38.88 ;
    RECT 20.49 38.81 20.75 38.88 ;
    RECT 22.465 38.81 22.695 38.88 ;
    RECT 23.18 38.81 23.44 38.88 ;
    RECT 24.35 38.81 24.42 38.88 ;
    RECT 27.685 38.81 27.895 38.88 ;
    RECT 28.07 38.81 28.34 38.88 ;
    RECT 32.125 38.81 32.195 38.88 ;
    RECT 32.455 38.81 32.72 38.88 ;
    RECT 34.21 38.81 34.47 38.88 ;
    RECT 34.655 38.81 34.725 38.88 ;
    RECT 35.145 38.81 35.405 38.88 ;
    RECT 36.27 38.81 36.48 38.88 ;
    RECT 38.08 38.985 38.895 39.055 ;
    RECT 39.885 38.54 40.155 38.61 ;
    RECT 39.885 38.895 40.155 38.965 ;
    RECT 39.885 39.26 40.155 39.33 ;
    RECT 15.2 37.82 15.27 38.61 ;
    RECT 15.8 37.82 16.01 37.89 ;
    RECT 15.8 38.175 16.01 38.245 ;
    RECT 15.8 38.54 16.01 38.61 ;
    RECT 16.965 38.265 17.765 38.335 ;
    RECT 19.43 38.09 19.665 38.16 ;
    RECT 20.49 38.09 20.75 38.16 ;
    RECT 22.465 38.09 22.695 38.16 ;
    RECT 23.18 38.09 23.44 38.16 ;
    RECT 24.35 38.09 24.42 38.16 ;
    RECT 27.685 38.09 27.895 38.16 ;
    RECT 28.07 38.09 28.34 38.16 ;
    RECT 32.125 38.09 32.195 38.16 ;
    RECT 32.455 38.09 32.72 38.16 ;
    RECT 34.21 38.09 34.47 38.16 ;
    RECT 34.655 38.09 34.725 38.16 ;
    RECT 35.145 38.09 35.405 38.16 ;
    RECT 36.27 38.09 36.48 38.16 ;
    RECT 38.08 38.265 38.895 38.335 ;
    RECT 39.885 37.82 40.155 37.89 ;
    RECT 39.885 38.175 40.155 38.245 ;
    RECT 39.885 38.54 40.155 38.61 ;
    RECT 15.2 37.1 15.27 37.89 ;
    RECT 15.8 37.1 16.01 37.17 ;
    RECT 15.8 37.455 16.01 37.525 ;
    RECT 15.8 37.82 16.01 37.89 ;
    RECT 16.965 37.545 17.765 37.615 ;
    RECT 19.43 37.37 19.665 37.44 ;
    RECT 20.49 37.37 20.75 37.44 ;
    RECT 22.465 37.37 22.695 37.44 ;
    RECT 23.18 37.37 23.44 37.44 ;
    RECT 24.35 37.37 24.42 37.44 ;
    RECT 27.685 37.37 27.895 37.44 ;
    RECT 28.07 37.37 28.34 37.44 ;
    RECT 32.125 37.37 32.195 37.44 ;
    RECT 32.455 37.37 32.72 37.44 ;
    RECT 34.21 37.37 34.47 37.44 ;
    RECT 34.655 37.37 34.725 37.44 ;
    RECT 35.145 37.37 35.405 37.44 ;
    RECT 36.27 37.37 36.48 37.44 ;
    RECT 38.08 37.545 38.895 37.615 ;
    RECT 39.885 37.1 40.155 37.17 ;
    RECT 39.885 37.455 40.155 37.525 ;
    RECT 39.885 37.82 40.155 37.89 ;
    RECT 29.065 37.367 29.135 37.437 ;
    RECT 15.2 36.38 15.27 37.17 ;
    RECT 15.8 36.38 16.01 36.45 ;
    RECT 15.8 36.735 16.01 36.805 ;
    RECT 15.8 37.1 16.01 37.17 ;
    RECT 16.965 36.825 17.765 36.895 ;
    RECT 19.43 36.65 19.665 36.72 ;
    RECT 20.49 36.65 20.75 36.72 ;
    RECT 22.465 36.65 22.695 36.72 ;
    RECT 23.18 36.65 23.44 36.72 ;
    RECT 24.35 36.65 24.42 36.72 ;
    RECT 27.685 36.65 27.895 36.72 ;
    RECT 28.07 36.65 28.34 36.72 ;
    RECT 32.125 36.65 32.195 36.72 ;
    RECT 32.455 36.65 32.72 36.72 ;
    RECT 34.21 36.65 34.47 36.72 ;
    RECT 34.655 36.65 34.725 36.72 ;
    RECT 35.145 36.65 35.405 36.72 ;
    RECT 36.27 36.65 36.48 36.72 ;
    RECT 38.08 36.825 38.895 36.895 ;
    RECT 39.885 36.38 40.155 36.45 ;
    RECT 39.885 36.735 40.155 36.805 ;
    RECT 39.885 37.1 40.155 37.17 ;
    RECT 15.2 35.66 15.27 36.45 ;
    RECT 15.8 35.66 16.01 35.73 ;
    RECT 15.8 36.015 16.01 36.085 ;
    RECT 15.8 36.38 16.01 36.45 ;
    RECT 16.965 36.105 17.765 36.175 ;
    RECT 19.43 35.93 19.665 36.0 ;
    RECT 20.49 35.93 20.75 36.0 ;
    RECT 22.465 35.93 22.695 36.0 ;
    RECT 23.18 35.93 23.44 36.0 ;
    RECT 24.35 35.93 24.42 36.0 ;
    RECT 27.685 35.93 27.895 36.0 ;
    RECT 28.07 35.93 28.34 36.0 ;
    RECT 32.125 35.93 32.195 36.0 ;
    RECT 32.455 35.93 32.72 36.0 ;
    RECT 34.21 35.93 34.47 36.0 ;
    RECT 34.655 35.93 34.725 36.0 ;
    RECT 35.145 35.93 35.405 36.0 ;
    RECT 36.27 35.93 36.48 36.0 ;
    RECT 38.08 36.105 38.895 36.175 ;
    RECT 39.885 35.66 40.155 35.73 ;
    RECT 39.885 36.015 40.155 36.085 ;
    RECT 39.885 36.38 40.155 36.45 ;
    RECT 15.2 34.94 15.27 35.73 ;
    RECT 15.8 34.94 16.01 35.01 ;
    RECT 15.8 35.295 16.01 35.365 ;
    RECT 15.8 35.66 16.01 35.73 ;
    RECT 16.965 35.385 17.765 35.455 ;
    RECT 19.43 35.21 19.665 35.28 ;
    RECT 20.49 35.21 20.75 35.28 ;
    RECT 22.465 35.21 22.695 35.28 ;
    RECT 23.18 35.21 23.44 35.28 ;
    RECT 24.35 35.21 24.42 35.28 ;
    RECT 27.685 35.21 27.895 35.28 ;
    RECT 28.07 35.21 28.34 35.28 ;
    RECT 32.125 35.21 32.195 35.28 ;
    RECT 32.455 35.21 32.72 35.28 ;
    RECT 34.21 35.21 34.47 35.28 ;
    RECT 34.655 35.21 34.725 35.28 ;
    RECT 35.145 35.21 35.405 35.28 ;
    RECT 36.27 35.21 36.48 35.28 ;
    RECT 38.08 35.385 38.895 35.455 ;
    RECT 39.885 34.94 40.155 35.01 ;
    RECT 39.885 35.295 40.155 35.365 ;
    RECT 39.885 35.66 40.155 35.73 ;
    RECT 15.2 34.22 15.27 35.01 ;
    RECT 15.8 34.22 16.01 34.29 ;
    RECT 15.8 34.575 16.01 34.645 ;
    RECT 15.8 34.94 16.01 35.01 ;
    RECT 16.965 34.665 17.765 34.735 ;
    RECT 19.43 34.49 19.665 34.56 ;
    RECT 20.49 34.49 20.75 34.56 ;
    RECT 22.465 34.49 22.695 34.56 ;
    RECT 23.18 34.49 23.44 34.56 ;
    RECT 24.35 34.49 24.42 34.56 ;
    RECT 27.685 34.49 27.895 34.56 ;
    RECT 28.07 34.49 28.34 34.56 ;
    RECT 32.125 34.49 32.195 34.56 ;
    RECT 32.455 34.49 32.72 34.56 ;
    RECT 34.21 34.49 34.47 34.56 ;
    RECT 34.655 34.49 34.725 34.56 ;
    RECT 35.145 34.49 35.405 34.56 ;
    RECT 36.27 34.49 36.48 34.56 ;
    RECT 38.08 34.665 38.895 34.735 ;
    RECT 39.885 34.22 40.155 34.29 ;
    RECT 39.885 34.575 40.155 34.645 ;
    RECT 39.885 34.94 40.155 35.01 ;
    RECT 21.45 35.927 21.66 35.997 ;
    RECT 15.2 45.02 15.27 45.81 ;
    RECT 15.8 45.02 16.01 45.09 ;
    RECT 15.8 45.375 16.01 45.445 ;
    RECT 15.8 45.74 16.01 45.81 ;
    RECT 16.965 45.465 17.765 45.535 ;
    RECT 19.43 45.29 19.665 45.36 ;
    RECT 20.49 45.29 20.75 45.36 ;
    RECT 22.465 45.29 22.695 45.36 ;
    RECT 23.18 45.29 23.44 45.36 ;
    RECT 24.35 45.29 24.42 45.36 ;
    RECT 27.685 45.29 27.895 45.36 ;
    RECT 28.07 45.29 28.34 45.36 ;
    RECT 32.125 45.29 32.195 45.36 ;
    RECT 32.455 45.29 32.72 45.36 ;
    RECT 34.21 45.29 34.47 45.36 ;
    RECT 34.655 45.29 34.725 45.36 ;
    RECT 35.145 45.29 35.405 45.36 ;
    RECT 36.27 45.29 36.48 45.36 ;
    RECT 38.08 45.465 38.895 45.535 ;
    RECT 39.885 45.02 40.155 45.09 ;
    RECT 39.885 45.375 40.155 45.445 ;
    RECT 39.885 45.74 40.155 45.81 ;
    RECT 16.39 36.02 16.6 36.09 ;
    RECT 29.065 36.647 29.135 36.717 ;
    RECT 15.2 44.3 15.27 45.09 ;
    RECT 15.8 44.3 16.01 44.37 ;
    RECT 15.8 44.655 16.01 44.725 ;
    RECT 15.8 45.02 16.01 45.09 ;
    RECT 16.965 44.745 17.765 44.815 ;
    RECT 19.43 44.57 19.665 44.64 ;
    RECT 20.49 44.57 20.75 44.64 ;
    RECT 22.465 44.57 22.695 44.64 ;
    RECT 23.18 44.57 23.44 44.64 ;
    RECT 24.35 44.57 24.42 44.64 ;
    RECT 27.685 44.57 27.895 44.64 ;
    RECT 28.07 44.57 28.34 44.64 ;
    RECT 32.125 44.57 32.195 44.64 ;
    RECT 32.455 44.57 32.72 44.64 ;
    RECT 34.21 44.57 34.47 44.64 ;
    RECT 34.655 44.57 34.725 44.64 ;
    RECT 35.145 44.57 35.405 44.64 ;
    RECT 36.27 44.57 36.48 44.64 ;
    RECT 38.08 44.745 38.895 44.815 ;
    RECT 39.885 44.3 40.155 44.37 ;
    RECT 39.885 44.655 40.155 44.725 ;
    RECT 39.885 45.02 40.155 45.09 ;
    RECT 15.2 43.58 15.27 44.37 ;
    RECT 15.8 43.58 16.01 43.65 ;
    RECT 15.8 43.935 16.01 44.005 ;
    RECT 15.8 44.3 16.01 44.37 ;
    RECT 16.965 44.025 17.765 44.095 ;
    RECT 19.43 43.85 19.665 43.92 ;
    RECT 20.49 43.85 20.75 43.92 ;
    RECT 22.465 43.85 22.695 43.92 ;
    RECT 23.18 43.85 23.44 43.92 ;
    RECT 24.35 43.85 24.42 43.92 ;
    RECT 27.685 43.85 27.895 43.92 ;
    RECT 28.07 43.85 28.34 43.92 ;
    RECT 32.125 43.85 32.195 43.92 ;
    RECT 32.455 43.85 32.72 43.92 ;
    RECT 34.21 43.85 34.47 43.92 ;
    RECT 34.655 43.85 34.725 43.92 ;
    RECT 35.145 43.85 35.405 43.92 ;
    RECT 36.27 43.85 36.48 43.92 ;
    RECT 38.08 44.025 38.895 44.095 ;
    RECT 39.885 43.58 40.155 43.65 ;
    RECT 39.885 43.935 40.155 44.005 ;
    RECT 39.885 44.3 40.155 44.37 ;
    RECT 15.2 42.86 15.27 43.65 ;
    RECT 15.8 42.86 16.01 42.93 ;
    RECT 15.8 43.215 16.01 43.285 ;
    RECT 15.8 43.58 16.01 43.65 ;
    RECT 16.965 43.305 17.765 43.375 ;
    RECT 19.43 43.13 19.665 43.2 ;
    RECT 20.49 43.13 20.75 43.2 ;
    RECT 22.465 43.13 22.695 43.2 ;
    RECT 23.18 43.13 23.44 43.2 ;
    RECT 24.35 43.13 24.42 43.2 ;
    RECT 27.685 43.13 27.895 43.2 ;
    RECT 28.07 43.13 28.34 43.2 ;
    RECT 32.125 43.13 32.195 43.2 ;
    RECT 32.455 43.13 32.72 43.2 ;
    RECT 34.21 43.13 34.47 43.2 ;
    RECT 34.655 43.13 34.725 43.2 ;
    RECT 35.145 43.13 35.405 43.2 ;
    RECT 36.27 43.13 36.48 43.2 ;
    RECT 38.08 43.305 38.895 43.375 ;
    RECT 39.885 42.86 40.155 42.93 ;
    RECT 39.885 43.215 40.155 43.285 ;
    RECT 39.885 43.58 40.155 43.65 ;
    RECT 15.2 42.14 15.27 42.93 ;
    RECT 15.8 42.14 16.01 42.21 ;
    RECT 15.8 42.495 16.01 42.565 ;
    RECT 15.8 42.86 16.01 42.93 ;
    RECT 16.965 42.585 17.765 42.655 ;
    RECT 19.43 42.41 19.665 42.48 ;
    RECT 20.49 42.41 20.75 42.48 ;
    RECT 22.465 42.41 22.695 42.48 ;
    RECT 23.18 42.41 23.44 42.48 ;
    RECT 24.35 42.41 24.42 42.48 ;
    RECT 27.685 42.41 27.895 42.48 ;
    RECT 28.07 42.41 28.34 42.48 ;
    RECT 32.125 42.41 32.195 42.48 ;
    RECT 32.455 42.41 32.72 42.48 ;
    RECT 34.21 42.41 34.47 42.48 ;
    RECT 34.655 42.41 34.725 42.48 ;
    RECT 35.145 42.41 35.405 42.48 ;
    RECT 36.27 42.41 36.48 42.48 ;
    RECT 38.08 42.585 38.895 42.655 ;
    RECT 39.885 42.14 40.155 42.21 ;
    RECT 39.885 42.495 40.155 42.565 ;
    RECT 39.885 42.86 40.155 42.93 ;
    RECT 15.2 41.42 15.27 42.21 ;
    RECT 15.8 41.42 16.01 41.49 ;
    RECT 15.8 41.775 16.01 41.845 ;
    RECT 15.8 42.14 16.01 42.21 ;
    RECT 16.965 41.865 17.765 41.935 ;
    RECT 19.43 41.69 19.665 41.76 ;
    RECT 20.49 41.69 20.75 41.76 ;
    RECT 22.465 41.69 22.695 41.76 ;
    RECT 23.18 41.69 23.44 41.76 ;
    RECT 24.35 41.69 24.42 41.76 ;
    RECT 27.685 41.69 27.895 41.76 ;
    RECT 28.07 41.69 28.34 41.76 ;
    RECT 32.125 41.69 32.195 41.76 ;
    RECT 32.455 41.69 32.72 41.76 ;
    RECT 34.21 41.69 34.47 41.76 ;
    RECT 34.655 41.69 34.725 41.76 ;
    RECT 35.145 41.69 35.405 41.76 ;
    RECT 36.27 41.69 36.48 41.76 ;
    RECT 38.08 41.865 38.895 41.935 ;
    RECT 39.885 41.42 40.155 41.49 ;
    RECT 39.885 41.775 40.155 41.845 ;
    RECT 39.885 42.14 40.155 42.21 ;
    RECT 39.245 35.3 39.455 35.37 ;
    RECT 33.49 35.21 33.7 35.28 ;
    RECT 26.95 35.207 27.02 35.277 ;
    RECT 15.2 22.7 15.27 34.29 ;
    RECT 15.8 22.7 16.01 23.125 ;
    RECT 15.8 23.42 16.01 23.49 ;
    RECT 15.8 23.78 16.01 23.85 ;
    RECT 15.8 24.14 16.01 24.21 ;
    RECT 15.8 24.5 16.01 24.57 ;
    RECT 15.8 24.86 16.01 24.93 ;
    RECT 15.8 25.22 16.01 25.29 ;
    RECT 15.8 25.58 16.01 25.65 ;
    RECT 15.8 25.94 16.01 26.01 ;
    RECT 15.8 26.3 16.01 26.37 ;
    RECT 15.8 26.66 16.01 26.73 ;
    RECT 15.8 27.02 16.01 27.09 ;
    RECT 15.8 27.38 16.01 27.45 ;
    RECT 15.8 27.74 16.01 27.81 ;
    RECT 15.8 28.1 16.01 28.17 ;
    RECT 15.8 28.46 16.01 28.53 ;
    RECT 15.8 28.82 16.01 28.89 ;
    RECT 15.8 29.18 16.01 29.25 ;
    RECT 15.8 29.54 16.01 29.61 ;
    RECT 15.8 29.9 16.01 29.97 ;
    RECT 15.8 30.26 16.01 30.33 ;
    RECT 15.8 30.62 16.01 30.69 ;
    RECT 15.8 30.98 16.01 31.05 ;
    RECT 15.8 31.34 16.01 31.41 ;
    RECT 15.8 31.7 16.01 31.77 ;
    RECT 15.8 32.06 16.01 32.13 ;
    RECT 15.8 32.42 16.01 32.49 ;
    RECT 15.8 32.78 16.01 32.85 ;
    RECT 15.8 33.14 16.01 33.21 ;
    RECT 15.8 33.5 16.01 33.57 ;
    RECT 15.8 33.86 16.01 33.93 ;
    RECT 15.8 34.22 16.01 34.29 ;
    RECT 16.995 23.145 17.735 23.215 ;
    RECT 16.995 23.865 17.735 23.935 ;
    RECT 16.995 24.58 17.735 24.65 ;
    RECT 16.995 25.305 17.735 25.375 ;
    RECT 16.995 26.025 17.735 26.095 ;
    RECT 16.995 26.745 17.735 26.815 ;
    RECT 16.995 27.46 17.735 27.53 ;
    RECT 16.995 28.185 17.735 28.255 ;
    RECT 16.995 28.905 17.735 28.975 ;
    RECT 16.995 29.62 17.735 29.69 ;
    RECT 16.995 30.345 17.735 30.415 ;
    RECT 16.995 31.065 17.735 31.135 ;
    RECT 16.995 31.785 17.735 31.855 ;
    RECT 16.995 32.505 17.735 32.575 ;
    RECT 16.995 33.225 17.735 33.295 ;
    RECT 16.995 33.945 17.735 34.015 ;
    RECT 19.45 22.98 19.66 23.05 ;
    RECT 19.45 23.68 19.66 23.75 ;
    RECT 19.45 24.4 19.66 24.47 ;
    RECT 19.45 25.12 19.66 25.19 ;
    RECT 19.45 25.84 19.66 25.91 ;
    RECT 19.45 26.565 19.66 26.635 ;
    RECT 19.45 27.285 19.66 27.355 ;
    RECT 19.45 28.72 19.66 28.79 ;
    RECT 19.45 29.44 19.66 29.51 ;
    RECT 19.45 30.16 19.66 30.23 ;
    RECT 19.45 30.88 19.66 30.95 ;
    RECT 19.45 31.6 19.66 31.67 ;
    RECT 19.45 32.325 19.66 32.395 ;
    RECT 19.45 33.045 19.66 33.115 ;
    RECT 19.45 33.76 19.66 33.83 ;
    RECT 20.49 26.565 20.75 26.635 ;
    RECT 20.49 28.72 20.75 28.79 ;
    RECT 20.49 29.44 20.75 29.51 ;
    RECT 20.49 30.16 20.75 30.23 ;
    RECT 20.49 30.88 20.75 30.95 ;
    RECT 20.49 31.6 20.75 31.67 ;
    RECT 20.49 32.325 20.75 32.395 ;
    RECT 20.49 33.045 20.75 33.115 ;
    RECT 20.49 33.76 20.75 33.83 ;
    RECT 20.52 25.12 20.73 25.19 ;
    RECT 20.52 25.835 20.73 25.905 ;
    RECT 20.53 27.3 20.74 27.37 ;
    RECT 21.43 28.72 21.68 28.79 ;
    RECT 21.43 29.44 21.68 29.51 ;
    RECT 21.43 30.16 21.68 30.23 ;
    RECT 21.43 30.88 21.68 30.95 ;
    RECT 21.43 31.6 21.68 31.67 ;
    RECT 21.43 32.325 21.68 32.395 ;
    RECT 21.43 33.045 21.68 33.115 ;
    RECT 21.43 33.76 21.68 33.83 ;
    RECT 21.45 22.97 21.66 23.04 ;
    RECT 21.45 23.685 21.66 23.755 ;
    RECT 21.45 26.56 21.66 26.63 ;
    RECT 21.45 28.005 21.66 28.075 ;
    RECT 22.165 25.12 22.235 25.19 ;
    RECT 22.165 25.835 22.235 25.905 ;
    RECT 22.165 27.3 22.235 27.37 ;
    RECT 22.465 25.115 22.695 25.185 ;
    RECT 22.465 25.83 22.695 25.9 ;
    RECT 22.465 27.295 22.695 27.365 ;
    RECT 23.175 25.115 23.445 25.185 ;
    RECT 23.175 25.83 23.445 25.9 ;
    RECT 23.175 27.295 23.445 27.365 ;
    RECT 23.725 22.97 23.935 23.04 ;
    RECT 23.725 23.685 23.935 23.755 ;
    RECT 23.725 26.56 23.935 26.63 ;
    RECT 23.725 28.005 23.935 28.075 ;
    RECT 24.76 22.97 24.97 23.04 ;
    RECT 24.76 23.685 24.97 23.755 ;
    RECT 24.76 24.4 24.97 24.47 ;
    RECT 24.76 26.56 24.97 26.63 ;
    RECT 24.76 28.005 24.97 28.075 ;
    RECT 25.145 25.115 25.415 25.185 ;
    RECT 25.145 25.83 25.415 25.9 ;
    RECT 25.755 28.005 25.825 28.075 ;
    RECT 25.755 33.76 25.825 33.83 ;
    RECT 25.955 27.29 26.025 27.36 ;
    RECT 25.955 33.035 26.025 33.105 ;
    RECT 26.155 26.56 26.225 26.63 ;
    RECT 26.155 32.32 26.225 32.39 ;
    RECT 26.355 25.84 26.425 25.91 ;
    RECT 26.355 31.605 26.425 31.675 ;
    RECT 26.55 25.115 26.62 25.185 ;
    RECT 26.55 30.89 26.62 30.96 ;
    RECT 26.75 24.4 26.82 24.47 ;
    RECT 26.75 30.165 26.82 30.235 ;
    RECT 26.95 23.685 27.02 23.755 ;
    RECT 26.95 29.44 27.02 29.51 ;
    RECT 27.15 22.97 27.22 23.04 ;
    RECT 27.15 28.73 27.22 28.8 ;
    RECT 27.685 25.12 27.895 25.19 ;
    RECT 27.685 25.845 27.895 25.915 ;
    RECT 27.685 26.565 27.895 26.635 ;
    RECT 27.685 27.295 27.895 27.365 ;
    RECT 27.685 28.005 27.895 28.075 ;
    RECT 27.685 28.73 27.895 28.8 ;
    RECT 27.685 29.445 27.895 29.515 ;
    RECT 27.685 30.16 27.895 30.23 ;
    RECT 27.685 30.89 27.895 30.96 ;
    RECT 27.685 31.61 27.895 31.68 ;
    RECT 27.685 32.33 27.895 32.4 ;
    RECT 27.685 33.045 27.895 33.115 ;
    RECT 27.685 33.76 27.895 33.83 ;
    RECT 28.075 25.845 28.335 25.915 ;
    RECT 28.075 26.565 28.335 26.635 ;
    RECT 28.075 27.295 28.335 27.365 ;
    RECT 28.075 28.005 28.335 28.075 ;
    RECT 28.075 28.73 28.335 28.8 ;
    RECT 28.075 29.445 28.335 29.515 ;
    RECT 28.075 30.16 28.335 30.23 ;
    RECT 28.075 30.89 28.335 30.96 ;
    RECT 28.075 31.61 28.335 31.68 ;
    RECT 28.075 32.33 28.335 32.4 ;
    RECT 28.075 33.045 28.335 33.115 ;
    RECT 28.075 33.76 28.335 33.83 ;
    RECT 28.12 25.115 28.33 25.185 ;
    RECT 28.475 23.68 28.545 23.75 ;
    RECT 28.475 23.68 28.545 23.75 ;
    RECT 28.475 24.405 28.545 24.475 ;
    RECT 28.475 24.405 28.545 24.475 ;
    RECT 28.665 22.97 28.735 23.04 ;
    RECT 28.665 28.735 28.735 28.805 ;
    RECT 28.855 29.45 28.925 29.52 ;
    RECT 29.06 30.165 29.13 30.235 ;
    RECT 29.26 30.895 29.33 30.965 ;
    RECT 29.46 31.61 29.53 31.68 ;
    RECT 29.66 32.325 29.73 32.395 ;
    RECT 29.855 33.04 29.925 33.11 ;
    RECT 30.055 33.76 30.125 33.83 ;
    RECT 30.265 23.68 30.525 23.75 ;
    RECT 30.265 24.405 30.525 24.475 ;
    RECT 30.265 25.835 30.535 25.905 ;
    RECT 30.265 27.265 30.535 27.335 ;
    RECT 30.68 24.405 30.89 24.475 ;
    RECT 30.68 25.115 30.89 25.185 ;
    RECT 31.64 23.68 31.85 23.75 ;
    RECT 31.64 25.115 31.85 25.185 ;
    RECT 31.64 27.265 31.85 27.335 ;
    RECT 31.66 22.975 31.87 23.045 ;
    RECT 32.125 23.68 32.195 23.75 ;
    RECT 32.125 25.115 32.195 25.185 ;
    RECT 32.125 27.265 32.195 27.335 ;
    RECT 32.13 28.005 32.2 28.075 ;
    RECT 32.505 23.68 32.715 23.75 ;
    RECT 32.505 25.115 32.715 25.185 ;
    RECT 32.505 27.265 32.715 27.335 ;
    RECT 33.465 22.645 33.72 22.715 ;
    RECT 33.465 25.12 33.725 25.19 ;
    RECT 33.465 25.83 33.725 25.9 ;
    RECT 33.49 23.69 33.7 23.76 ;
    RECT 33.49 24.405 33.7 24.475 ;
    RECT 33.49 27.27 33.7 27.34 ;
    RECT 33.52 28.735 33.73 28.805 ;
    RECT 33.52 30.165 33.73 30.235 ;
    RECT 33.52 31.605 33.73 31.675 ;
    RECT 34.205 25.12 34.475 25.19 ;
    RECT 34.21 25.83 34.47 25.9 ;
    RECT 34.21 28.0 34.47 28.07 ;
    RECT 34.21 29.445 34.47 29.515 ;
    RECT 34.21 30.875 34.47 30.945 ;
    RECT 34.21 32.34 34.47 32.41 ;
    RECT 34.21 33.055 34.47 33.125 ;
    RECT 34.21 33.77 34.47 33.84 ;
    RECT 34.235 22.975 34.445 23.045 ;
    RECT 34.655 25.12 34.725 25.19 ;
    RECT 34.655 25.83 34.725 25.9 ;
    RECT 34.655 26.555 34.725 26.625 ;
    RECT 34.655 29.445 34.725 29.515 ;
    RECT 34.655 30.875 34.725 30.945 ;
    RECT 34.655 32.34 34.725 32.41 ;
    RECT 34.655 33.055 34.725 33.125 ;
    RECT 34.655 33.77 34.725 33.84 ;
    RECT 35.145 25.12 35.405 25.19 ;
    RECT 35.145 25.83 35.405 25.9 ;
    RECT 35.145 26.555 35.405 26.625 ;
    RECT 35.145 29.445 35.405 29.515 ;
    RECT 35.145 30.875 35.405 30.945 ;
    RECT 35.145 32.34 35.405 32.41 ;
    RECT 35.145 33.055 35.405 33.125 ;
    RECT 35.145 33.77 35.405 33.84 ;
    RECT 35.16 27.27 35.37 27.34 ;
    RECT 35.175 23.69 35.385 23.76 ;
    RECT 35.175 24.405 35.385 24.475 ;
    RECT 35.175 28.735 35.385 28.805 ;
    RECT 35.175 30.165 35.385 30.235 ;
    RECT 35.175 31.605 35.385 31.675 ;
    RECT 36.33 22.97 36.4 23.04 ;
    RECT 36.365 23.685 36.435 23.755 ;
    RECT 36.365 24.4 36.435 24.47 ;
    RECT 36.365 25.115 36.435 25.185 ;
    RECT 36.365 25.83 36.435 25.9 ;
    RECT 36.365 26.55 36.435 26.62 ;
    RECT 36.365 27.265 36.435 27.335 ;
    RECT 36.365 28.73 36.435 28.8 ;
    RECT 36.365 29.45 36.435 29.52 ;
    RECT 36.365 30.17 36.435 30.24 ;
    RECT 36.365 30.89 36.435 30.96 ;
    RECT 36.365 31.61 36.435 31.68 ;
    RECT 36.365 32.335 36.435 32.405 ;
    RECT 36.365 33.05 36.435 33.12 ;
    RECT 36.365 33.77 36.435 33.84 ;
    RECT 38.105 23.145 38.895 23.215 ;
    RECT 38.105 23.865 38.895 23.935 ;
    RECT 38.105 24.58 38.895 24.65 ;
    RECT 38.105 25.305 38.895 25.375 ;
    RECT 38.105 26.025 38.895 26.095 ;
    RECT 38.105 26.745 38.895 26.815 ;
    RECT 38.105 27.46 38.895 27.53 ;
    RECT 38.105 28.185 38.895 28.255 ;
    RECT 38.105 28.905 38.895 28.975 ;
    RECT 38.105 29.62 38.895 29.69 ;
    RECT 38.105 30.345 38.895 30.415 ;
    RECT 38.105 31.065 38.895 31.135 ;
    RECT 38.105 31.785 38.895 31.855 ;
    RECT 38.105 32.505 38.895 32.575 ;
    RECT 38.105 33.225 38.895 33.295 ;
    RECT 38.105 33.945 38.895 34.015 ;
    RECT 39.885 22.7 40.155 22.77 ;
    RECT 39.885 23.055 40.155 23.125 ;
    RECT 39.885 23.42 40.155 23.49 ;
    RECT 39.885 24.14 40.155 24.21 ;
    RECT 39.885 24.86 40.155 24.93 ;
    RECT 39.885 25.58 40.155 25.65 ;
    RECT 39.885 26.3 40.155 26.37 ;
    RECT 39.885 27.02 40.155 27.09 ;
    RECT 39.885 27.74 40.155 27.81 ;
    RECT 39.885 28.46 40.155 28.53 ;
    RECT 39.885 29.18 40.155 29.25 ;
    RECT 39.885 29.9 40.155 29.97 ;
    RECT 39.885 30.62 40.155 30.69 ;
    RECT 39.885 31.34 40.155 31.41 ;
    RECT 39.885 32.06 40.155 32.13 ;
    RECT 39.885 32.78 40.155 32.85 ;
    RECT 39.885 33.5 40.155 33.57 ;
    RECT 39.885 34.22 40.155 34.29 ;
    RECT 39.92 23.78 40.13 23.85 ;
    RECT 39.92 24.5 40.13 24.57 ;
    RECT 39.92 25.22 40.13 25.29 ;
    RECT 39.92 25.94 40.13 26.01 ;
    RECT 39.92 26.66 40.13 26.73 ;
    RECT 39.92 27.38 40.13 27.45 ;
    RECT 39.92 28.1 40.13 28.17 ;
    RECT 39.92 28.82 40.13 28.89 ;
    RECT 39.92 29.54 40.13 29.61 ;
    RECT 39.92 30.26 40.13 30.33 ;
    RECT 39.92 30.98 40.13 31.05 ;
    RECT 39.92 31.7 40.13 31.77 ;
    RECT 39.92 32.42 40.13 32.49 ;
    RECT 39.92 33.14 40.13 33.21 ;
    RECT 39.92 33.86 40.13 33.93 ;
    RECT 21.45 35.207 21.66 35.277 ;
    RECT 16.39 35.3 16.6 35.37 ;
    RECT 29.26 45.287 29.33 45.357 ;
    RECT 27.15 34.487 27.22 34.557 ;
    RECT 29.065 35.927 29.135 35.997 ;
    RECT 39.245 34.58 39.455 34.65 ;
    RECT 33.49 34.49 33.7 34.56 ;
    RECT 15.2 45.74 15.27 45.81 ;
    RECT 15.8 45.74 16.01 45.81 ;
    RECT 16.155 46.76 16.225 46.83 ;
    RECT 16.995 46.155 17.735 46.225 ;
    RECT 18.015 45.83 18.225 45.9 ;
    RECT 18.475 46.76 18.685 46.83 ;
    RECT 18.87 45.83 19.08 45.9 ;
    RECT 20.52 45.83 20.73 45.9 ;
    RECT 21.08 46.76 21.29 46.83 ;
    RECT 21.45 46.335 21.66 46.405 ;
    RECT 21.865 46.76 21.935 46.83 ;
    RECT 22.475 46.76 22.685 46.83 ;
    RECT 23.205 46.76 23.415 46.83 ;
    RECT 23.725 46.335 23.935 46.405 ;
    RECT 24.76 46.335 24.97 46.405 ;
    RECT 25.175 46.76 25.385 46.83 ;
    RECT 25.555 45.83 25.625 45.9 ;
    RECT 27.335 46.76 27.545 46.83 ;
    RECT 28.1 45.83 28.31 45.9 ;
    RECT 28.475 46.76 28.545 46.83 ;
    RECT 30.295 46.76 30.505 46.83 ;
    RECT 30.68 45.83 30.89 45.9 ;
    RECT 31.385 46.76 31.455 46.83 ;
    RECT 31.66 46.335 31.87 46.405 ;
    RECT 32.13 45.975 32.2 46.045 ;
    RECT 32.48 46.76 32.69 46.83 ;
    RECT 33.49 45.83 33.7 45.9 ;
    RECT 34.235 46.335 34.445 46.405 ;
    RECT 35.175 45.83 35.385 45.9 ;
    RECT 35.695 46.76 35.905 46.83 ;
    RECT 36.825 45.83 36.895 45.9 ;
    RECT 37.07 46.76 37.28 46.83 ;
    RECT 37.45 45.83 37.66 45.9 ;
    RECT 38.105 46.155 38.895 46.225 ;
    RECT 39.63 46.76 39.7 46.83 ;
    RECT 39.885 45.74 40.155 45.81 ;
    RECT 40.525 46.76 40.735 46.83 ;
    RECT 39.245 41.06 39.455 41.13 ;
    RECT 33.49 40.97 33.7 41.04 ;
    RECT 29.065 35.207 29.135 35.277 ;
    RECT 29.26 44.567 29.33 44.637 ;
    RECT 21.45 34.487 21.66 34.557 ;
    RECT 16.39 34.58 16.6 34.65 ;
    RECT 39.245 33.86 39.455 33.93 ;
    RECT 39.245 33.14 39.455 33.21 ;
    RECT 39.245 32.42 39.455 32.49 ;
    RECT 21.45 40.967 21.66 41.037 ;
    RECT 16.39 41.06 16.6 41.13 ;
    RECT 39.245 31.7 39.455 31.77 ;
    RECT 39.245 30.98 39.455 31.05 ;
    RECT 39.245 30.26 39.455 30.33 ;
    RECT 39.245 29.54 39.455 29.61 ;
    RECT 39.245 28.82 39.455 28.89 ;
    RECT 39.245 28.1 39.455 28.17 ;
    RECT 39.245 27.38 39.455 27.45 ;
    RECT 29.26 43.847 29.33 43.917 ;
    RECT 39.245 40.34 39.455 40.41 ;
    RECT 29.065 34.487 29.135 34.557 ;
    RECT 39.245 26.66 39.455 26.73 ;
    RECT 39.245 25.94 39.455 26.01 ;
    RECT 39.245 25.22 39.455 25.29 ;
    RECT 39.245 24.5 39.455 24.57 ;
    RECT 39.245 23.78 39.455 23.85 ;
    RECT 39.245 23.06 39.455 23.13 ;
    RECT 55.415 15.81 55.485 15.88 ;
    RECT 55.215 11.005 55.285 11.075 ;
    RECT 55.215 12.465 55.285 12.535 ;
    RECT 55.215 15.37 55.285 15.44 ;
    RECT 55.22 20.225 55.29 20.435 ;
    RECT 55.22 16.215 55.29 16.425 ;
    RECT 55.22 14.36 55.29 14.43 ;
    RECT 55.22 11.56 55.29 11.77 ;
    RECT 55.22 6.655 55.29 6.865 ;
    RECT 55.64 22.2 55.71 22.27 ;
    RECT 55.43 22.46 55.5 22.53 ;
    RECT 53.74 4.95 53.95 5.16 ;
    RECT 47.1 13.06 47.31 13.27 ;
    RECT 53.74 3.075 53.95 3.285 ;
    RECT 47.1 11.235 47.31 11.445 ;
    RECT 47.1 10.385 47.31 10.595 ;
    RECT 47.1 8.125 47.31 8.195 ;
    RECT 47.1 6.34 47.31 6.55 ;
    RECT 47.1 4.95 47.31 5.16 ;
    RECT 47.1 3.075 47.31 3.285 ;
    RECT 47.585 14.36 47.655 14.43 ;
    RECT 47.585 11.56 47.655 11.77 ;
    RECT 48.02 15.37 48.23 15.44 ;
    RECT 48.02 12.465 48.23 12.535 ;
    RECT 48.02 11.005 48.23 11.075 ;
    RECT 50.905 14.36 50.975 14.43 ;
    RECT 50.42 15.81 50.63 15.88 ;
    RECT 50.42 18.235 50.63 18.445 ;
    RECT 50.42 17.15 50.63 17.36 ;
    RECT 50.42 16.95 50.63 17.02 ;
    RECT 50.42 16.56 50.63 16.63 ;
    RECT 50.42 14.555 50.63 14.625 ;
    RECT 43.78 18.235 43.99 18.445 ;
    RECT 50.905 11.56 50.975 11.77 ;
    RECT 44.265 14.36 44.335 14.43 ;
    RECT 44.265 11.56 44.335 11.77 ;
    RECT 51.34 15.37 51.55 15.44 ;
    RECT 51.34 12.465 51.55 12.535 ;
    RECT 51.34 11.005 51.55 11.075 ;
    RECT 44.7 15.37 44.91 15.44 ;
    RECT 44.7 12.465 44.91 12.535 ;
    RECT 44.7 11.005 44.91 11.075 ;
    RECT 54.225 14.36 54.295 14.43 ;
    RECT 54.225 11.56 54.295 11.77 ;
    RECT 50.42 13.06 50.63 13.27 ;
    RECT 50.42 11.235 50.63 11.445 ;
    RECT 43.78 17.15 43.99 17.36 ;
    RECT 50.42 10.385 50.63 10.595 ;
    RECT 43.78 16.95 43.99 17.02 ;
    RECT 50.42 8.125 50.63 8.195 ;
    RECT 43.78 16.56 43.99 16.63 ;
    RECT 50.42 6.34 50.63 6.55 ;
    RECT 43.78 14.555 43.99 14.625 ;
    RECT 50.42 4.95 50.63 5.16 ;
    RECT 43.78 13.06 43.99 13.27 ;
    RECT 50.42 3.075 50.63 3.285 ;
    RECT 43.78 11.235 43.99 11.445 ;
    RECT 43.78 10.385 43.99 10.595 ;
    RECT 43.78 8.125 43.99 8.195 ;
    RECT 43.78 6.34 43.99 6.55 ;
    RECT 43.78 4.95 43.99 5.16 ;
    RECT 47.1 15.81 47.31 15.88 ;
    RECT 54.66 15.37 54.87 15.44 ;
    RECT 54.66 12.465 54.87 12.535 ;
    RECT 54.66 11.005 54.87 11.075 ;
    RECT 54.66 6.655 54.87 6.865 ;
    RECT 54.66 11.56 54.87 11.77 ;
    RECT 54.66 14.36 54.87 14.43 ;
    RECT 54.66 16.215 54.87 16.425 ;
    RECT 54.66 20.225 54.87 20.435 ;
    RECT 54.635 9.735 54.845 9.945 ;
    RECT 54.43 3.075 54.5 3.145 ;
    RECT 54.43 3.215 54.5 3.285 ;
    RECT 54.43 4.95 54.5 5.02 ;
    RECT 54.43 5.09 54.5 5.16 ;
    RECT 54.43 6.34 54.5 6.41 ;
    RECT 54.43 6.48 54.5 6.55 ;
    RECT 54.43 8.14 54.5 8.21 ;
    RECT 54.43 10.385 54.5 10.455 ;
    RECT 54.43 10.525 54.5 10.595 ;
    RECT 54.43 11.235 54.5 11.305 ;
    RECT 54.43 11.375 54.5 11.445 ;
    RECT 54.43 13.06 54.5 13.13 ;
    RECT 54.43 13.2 54.5 13.27 ;
    RECT 54.43 14.555 54.5 14.625 ;
    RECT 54.43 15.0 54.5 15.07 ;
    RECT 54.43 20.54 54.5 20.61 ;
    RECT 54.23 16.56 54.3 17.36 ;
    RECT 54.23 18.235 54.3 18.445 ;
    RECT 54.225 11.005 54.295 11.075 ;
    RECT 54.225 12.46 54.295 12.53 ;
    RECT 54.225 15.365 54.295 15.435 ;
    RECT 53.215 20.85 53.485 20.92 ;
    RECT 52.755 8.13 53.025 17.02 ;
    RECT 52.79 3.075 53.0 3.285 ;
    RECT 52.79 6.34 53.0 6.55 ;
    RECT 52.79 13.06 53.0 13.27 ;
    RECT 52.79 16.56 53.0 17.36 ;
    RECT 52.79 18.235 53.0 18.445 ;
    RECT 52.785 4.95 52.995 5.16 ;
    RECT 43.78 3.075 43.99 3.285 ;
    RECT 44.7 6.655 44.91 6.865 ;
    RECT 44.7 11.56 44.91 11.77 ;
    RECT 44.7 14.36 44.91 14.43 ;
    RECT 44.7 16.215 44.91 16.425 ;
    RECT 44.7 20.225 44.91 20.435 ;
    RECT 44.675 9.735 44.885 9.945 ;
    RECT 44.47 3.075 44.54 3.145 ;
    RECT 44.47 3.215 44.54 3.285 ;
    RECT 44.47 4.95 44.54 5.02 ;
    RECT 44.47 5.09 44.54 5.16 ;
    RECT 44.47 6.34 44.54 6.41 ;
    RECT 44.47 6.48 44.54 6.55 ;
    RECT 44.47 8.14 44.54 8.21 ;
    RECT 44.47 10.385 44.54 10.455 ;
    RECT 44.47 10.525 44.54 10.595 ;
    RECT 44.47 11.235 44.54 11.305 ;
    RECT 44.47 11.375 44.54 11.445 ;
    RECT 44.47 13.06 44.54 13.13 ;
    RECT 44.47 13.2 44.54 13.27 ;
    RECT 44.47 14.555 44.54 14.625 ;
    RECT 44.47 15.0 44.54 15.07 ;
    RECT 44.47 20.54 44.54 20.61 ;
    RECT 44.27 16.56 44.34 17.36 ;
    RECT 44.27 18.235 44.34 18.445 ;
    RECT 44.265 11.005 44.335 11.075 ;
    RECT 44.265 12.46 44.335 12.53 ;
    RECT 44.265 15.365 44.335 15.435 ;
    RECT 43.255 20.85 43.525 20.92 ;
    RECT 42.795 8.13 43.065 17.02 ;
    RECT 42.83 3.075 43.04 3.285 ;
    RECT 42.83 6.34 43.04 6.55 ;
    RECT 42.83 13.06 43.04 13.27 ;
    RECT 42.83 16.56 43.04 17.36 ;
    RECT 42.83 18.235 43.04 18.445 ;
    RECT 42.825 4.95 43.035 5.16 ;
    RECT 51.34 6.655 51.55 6.865 ;
    RECT 51.34 11.56 51.55 11.77 ;
    RECT 51.34 14.36 51.55 14.43 ;
    RECT 51.34 16.215 51.55 16.425 ;
    RECT 51.34 20.225 51.55 20.435 ;
    RECT 51.315 9.735 51.525 9.945 ;
    RECT 51.11 3.075 51.18 3.145 ;
    RECT 51.11 3.215 51.18 3.285 ;
    RECT 51.11 4.95 51.18 5.02 ;
    RECT 51.11 5.09 51.18 5.16 ;
    RECT 51.11 6.34 51.18 6.41 ;
    RECT 51.11 6.48 51.18 6.55 ;
    RECT 51.11 8.14 51.18 8.21 ;
    RECT 51.11 10.385 51.18 10.455 ;
    RECT 51.11 10.525 51.18 10.595 ;
    RECT 51.11 11.235 51.18 11.305 ;
    RECT 51.11 11.375 51.18 11.445 ;
    RECT 51.11 13.06 51.18 13.13 ;
    RECT 51.11 13.2 51.18 13.27 ;
    RECT 51.11 14.555 51.18 14.625 ;
    RECT 51.11 15.0 51.18 15.07 ;
    RECT 51.11 20.54 51.18 20.61 ;
    RECT 50.91 16.56 50.98 17.36 ;
    RECT 50.91 18.235 50.98 18.445 ;
    RECT 50.905 11.005 50.975 11.075 ;
    RECT 50.905 12.46 50.975 12.53 ;
    RECT 50.905 15.365 50.975 15.435 ;
    RECT 49.895 20.85 50.165 20.92 ;
    RECT 49.435 8.13 49.705 17.02 ;
    RECT 49.47 3.075 49.68 3.285 ;
    RECT 49.47 6.34 49.68 6.55 ;
    RECT 49.47 13.06 49.68 13.27 ;
    RECT 49.47 16.56 49.68 17.36 ;
    RECT 49.47 18.235 49.68 18.445 ;
    RECT 49.465 4.95 49.675 5.16 ;
    RECT 48.02 6.655 48.23 6.865 ;
    RECT 48.02 11.56 48.23 11.77 ;
    RECT 48.02 14.36 48.23 14.43 ;
    RECT 48.02 16.215 48.23 16.425 ;
    RECT 48.02 20.225 48.23 20.435 ;
    RECT 47.995 9.735 48.205 9.945 ;
    RECT 47.79 3.075 47.86 3.145 ;
    RECT 47.79 3.215 47.86 3.285 ;
    RECT 47.79 4.95 47.86 5.02 ;
    RECT 47.79 5.09 47.86 5.16 ;
    RECT 47.79 6.34 47.86 6.41 ;
    RECT 47.79 6.48 47.86 6.55 ;
    RECT 47.79 8.14 47.86 8.21 ;
    RECT 47.79 10.385 47.86 10.455 ;
    RECT 47.79 10.525 47.86 10.595 ;
    RECT 47.79 11.235 47.86 11.305 ;
    RECT 47.79 11.375 47.86 11.445 ;
    RECT 47.79 13.06 47.86 13.13 ;
    RECT 47.79 13.2 47.86 13.27 ;
    RECT 47.79 14.555 47.86 14.625 ;
    RECT 47.79 15.0 47.86 15.07 ;
    RECT 47.79 20.54 47.86 20.61 ;
    RECT 47.59 16.56 47.66 17.36 ;
    RECT 47.59 18.235 47.66 18.445 ;
    RECT 47.585 11.005 47.655 11.075 ;
    RECT 47.585 12.46 47.655 12.53 ;
    RECT 47.585 15.365 47.655 15.435 ;
    RECT 46.575 20.85 46.845 20.92 ;
    RECT 46.115 8.13 46.385 17.02 ;
    RECT 46.15 3.075 46.36 3.285 ;
    RECT 46.15 6.34 46.36 6.55 ;
    RECT 46.15 13.06 46.36 13.27 ;
    RECT 46.15 16.56 46.36 17.36 ;
    RECT 46.15 18.235 46.36 18.445 ;
    RECT 46.145 4.95 46.355 5.16 ;
    RECT 53.74 18.235 53.95 18.445 ;
    RECT 53.74 17.15 53.95 17.36 ;
    RECT 53.74 16.95 53.95 17.02 ;
    RECT 53.74 16.56 53.95 16.63 ;
    RECT 53.74 14.555 53.95 14.625 ;
    RECT 53.74 13.06 53.95 13.27 ;
    RECT 47.1 18.235 47.31 18.445 ;
    RECT 53.74 11.235 53.95 11.445 ;
    RECT 47.1 17.15 47.31 17.36 ;
    RECT 47.1 16.95 47.31 17.02 ;
    RECT 53.74 15.81 53.95 15.88 ;
    RECT 43.78 15.81 43.99 15.88 ;
    RECT 53.74 10.385 53.95 10.595 ;
    RECT 53.74 8.125 53.95 8.195 ;
    RECT 47.1 16.56 47.31 16.63 ;
    RECT 53.74 6.34 53.95 6.55 ;
    RECT 47.1 14.555 47.31 14.625 ;
    RECT 51.34 1.465 51.55 1.675 ;
    RECT 50.92 0.98 50.99 1.05 ;
    RECT 50.42 0.775 50.63 0.845 ;
    RECT 49.47 1.15 49.68 1.985 ;
    RECT 48.02 1.465 48.23 1.675 ;
    RECT 47.6 0.98 47.67 1.05 ;
    RECT 47.1 0.775 47.31 0.845 ;
    RECT 46.15 1.15 46.36 1.985 ;
    RECT 42.83 0.775 43.04 0.845 ;
    RECT 54.66 1.465 54.87 1.675 ;
    RECT 54.24 0.98 54.31 1.05 ;
    RECT 53.74 0.775 53.95 0.845 ;
    RECT 52.79 1.15 53.0 1.985 ;
    RECT 43.78 1.775 43.99 1.985 ;
    RECT 43.78 1.15 43.99 1.36 ;
    RECT 50.42 1.775 50.63 1.985 ;
    RECT 44.7 1.465 44.91 1.675 ;
    RECT 44.28 0.98 44.35 1.05 ;
    RECT 43.78 0.775 43.99 0.845 ;
    RECT 42.83 1.15 43.04 1.985 ;
    RECT 50.42 1.15 50.63 1.36 ;
    RECT 46.15 0.775 46.36 0.845 ;
    RECT 47.1 1.775 47.31 1.985 ;
    RECT 47.1 1.15 47.31 1.36 ;
    RECT 52.79 0.775 53.0 0.845 ;
    RECT 53.74 1.775 53.95 1.985 ;
    RECT 53.74 1.15 53.95 1.36 ;
    RECT 49.47 0.775 49.68 0.845 ;
    RECT 43.29 21.94 43.5 22.01 ;
    RECT 50.42 22.46 50.63 22.53 ;
    RECT 46.61 21.94 46.82 22.01 ;
    RECT 54.655 21.68 54.875 21.75 ;
    RECT 51.335 21.68 51.555 21.75 ;
    RECT 53.74 22.46 53.95 22.53 ;
    RECT 48.015 21.68 48.235 21.75 ;
    RECT 54.2 22.46 54.41 22.53 ;
    RECT 43.29 22.2 43.5 22.27 ;
    RECT 44.695 21.68 44.915 21.75 ;
    RECT 43.78 22.46 43.99 22.53 ;
    RECT 44.24 22.46 44.45 22.53 ;
    RECT 49.93 21.94 50.14 22.01 ;
    RECT 46.61 22.2 46.82 22.27 ;
    RECT 47.1 22.46 47.31 22.53 ;
    RECT 47.56 22.46 47.77 22.53 ;
    RECT 53.25 21.94 53.46 22.01 ;
    RECT 49.93 22.2 50.14 22.27 ;
    RECT 50.88 22.46 51.09 22.53 ;
    RECT 53.25 22.2 53.46 22.27 ;
    RECT 28.1 16.56 28.31 16.63 ;
    RECT 28.1 16.002 28.31 16.072 ;
    RECT 28.1 14.555 28.31 14.625 ;
    RECT 28.1 13.06 28.31 13.27 ;
    RECT 28.1 11.235 28.31 11.445 ;
    RECT 28.1 10.012 28.31 10.082 ;
    RECT 28.1 8.345 28.31 8.415 ;
    RECT 28.1 6.34 28.31 6.55 ;
    RECT 38.685 21.425 38.895 21.635 ;
    RECT 25.555 19.675 25.625 19.745 ;
    RECT 25.555 16.56 25.625 16.63 ;
    RECT 25.555 14.555 25.625 14.625 ;
    RECT 25.555 13.06 25.625 13.27 ;
    RECT 14.375 14.36 14.445 14.43 ;
    RECT 14.375 11.56 14.445 11.77 ;
    RECT 14.375 6.655 14.445 6.865 ;
    RECT 25.555 11.235 25.625 11.445 ;
    RECT 25.555 10.012 25.625 10.082 ;
    RECT 25.555 8.345 25.625 8.415 ;
    RECT 25.555 6.34 25.625 6.55 ;
    RECT 24.76 14.94 24.97 15.01 ;
    RECT 24.76 9.32 24.97 9.39 ;
    RECT 24.76 7.84 24.97 7.91 ;
    RECT 24.76 7.155 24.97 7.225 ;
    RECT 23.725 14.94 23.935 15.01 ;
    RECT 23.725 9.32 23.935 9.39 ;
    RECT 23.725 7.84 23.935 7.91 ;
    RECT 23.725 7.155 23.935 7.225 ;
    RECT 22.095 19.295 22.305 19.365 ;
    RECT 22.095 16.56 22.305 16.63 ;
    RECT 21.45 20.535 21.66 20.605 ;
    RECT 21.45 18.922 21.66 18.992 ;
    RECT 21.45 17.737 21.66 17.807 ;
    RECT 21.45 14.94 21.66 15.01 ;
    RECT 21.45 9.32 21.66 9.39 ;
    RECT 21.45 7.84 21.66 7.91 ;
    RECT 21.45 7.155 21.66 7.225 ;
    RECT 20.52 19.295 20.73 19.365 ;
    RECT 20.52 14.555 20.73 14.625 ;
    RECT 20.52 13.12 20.73 13.19 ;
    RECT 20.52 11.235 20.73 11.445 ;
    RECT 20.52 10.012 20.73 10.082 ;
    RECT 20.52 8.345 20.73 8.415 ;
    RECT 20.52 6.34 20.73 6.55 ;
    RECT 18.87 19.295 19.08 19.365 ;
    RECT 18.87 18.235 19.08 18.445 ;
    RECT 18.87 14.555 19.08 14.625 ;
    RECT 18.87 13.12 19.08 13.19 ;
    RECT 22.857 9.852 22.927 9.922 ;
    RECT 39.245 7.84 39.455 7.91 ;
    RECT 37.45 19.675 37.66 19.745 ;
    RECT 37.45 18.235 37.66 18.445 ;
    RECT 37.45 17.15 37.66 17.36 ;
    RECT 37.45 16.56 37.66 16.63 ;
    RECT 37.45 14.555 37.66 14.625 ;
    RECT 37.45 13.06 37.66 13.27 ;
    RECT 37.45 11.235 37.66 11.445 ;
    RECT 37.45 10.012 37.66 10.082 ;
    RECT 37.45 8.345 37.66 8.415 ;
    RECT 37.45 6.34 37.66 6.55 ;
    RECT 36.825 19.675 36.895 19.745 ;
    RECT 36.825 18.235 36.895 18.445 ;
    RECT 36.825 17.15 36.895 17.36 ;
    RECT 36.825 16.56 36.895 16.63 ;
    RECT 36.825 14.555 36.895 14.625 ;
    RECT 36.825 13.06 36.895 13.27 ;
    RECT 36.825 11.235 36.895 11.445 ;
    RECT 36.825 10.012 36.895 10.082 ;
    RECT 14.375 5.955 14.445 6.025 ;
    RECT 14.375 11.005 14.445 11.075 ;
    RECT 14.375 12.465 14.445 12.535 ;
    RECT 14.375 15.37 14.445 15.44 ;
    RECT 14.375 21.44 14.445 21.51 ;
    RECT 14.38 18.045 14.45 18.115 ;
    RECT 14.585 6.14 14.655 6.21 ;
    RECT 14.585 15.81 14.655 15.88 ;
    RECT 14.585 22.46 14.655 22.53 ;
    RECT 14.78 20.045 14.85 20.115 ;
    RECT 14.795 10.1 14.865 10.17 ;
    RECT 14.795 22.2 14.865 22.27 ;
    RECT 15.2 9.32 15.27 9.39 ;
    RECT 15.2 12.01 15.27 12.08 ;
    RECT 15.2 12.15 15.27 12.22 ;
    RECT 15.2 12.86 15.27 12.93 ;
    RECT 15.2 18.925 15.27 18.995 ;
    RECT 15.46 8.345 15.53 8.415 ;
    RECT 15.46 19.675 15.53 19.745 ;
    RECT 15.8 9.32 16.01 9.39 ;
    RECT 15.8 12.01 16.01 12.22 ;
    RECT 15.8 12.86 16.01 12.93 ;
    RECT 15.8 14.94 16.01 15.01 ;
    RECT 15.8 17.74 16.01 17.81 ;
    RECT 15.8 18.925 16.01 18.995 ;
    RECT 15.8 20.535 16.01 20.605 ;
    RECT 15.8 21.21 16.01 21.28 ;
    RECT 16.15 10.78 16.22 10.85 ;
    RECT 16.155 6.655 16.225 6.725 ;
    RECT 16.155 6.795 16.225 6.865 ;
    RECT 16.155 7.735 16.225 7.805 ;
    RECT 16.155 7.735 16.225 7.805 ;
    RECT 16.155 7.875 16.225 7.945 ;
    RECT 16.155 7.875 16.225 7.945 ;
    RECT 16.155 11.56 16.225 11.63 ;
    RECT 16.155 11.7 16.225 11.77 ;
    RECT 16.155 14.36 16.225 14.43 ;
    RECT 16.155 16.215 16.225 16.285 ;
    RECT 16.155 16.355 16.225 16.425 ;
    RECT 16.155 20.225 16.225 20.435 ;
    RECT 16.39 6.34 16.6 6.55 ;
    RECT 16.39 8.345 16.6 8.415 ;
    RECT 16.39 11.235 16.6 11.445 ;
    RECT 16.39 13.06 16.6 13.27 ;
    RECT 16.39 14.555 16.6 14.625 ;
    RECT 16.39 16.705 16.6 16.775 ;
    RECT 16.39 18.235 16.6 18.445 ;
    RECT 16.39 19.295 16.6 19.365 ;
    RECT 16.985 21.205 17.745 21.275 ;
    RECT 17.99 19.675 18.25 19.745 ;
    RECT 18.015 7.155 18.225 7.225 ;
    RECT 18.015 9.32 18.225 9.39 ;
    RECT 18.015 12.86 18.225 12.93 ;
    RECT 18.015 14.94 18.225 15.01 ;
    RECT 18.015 17.74 18.225 17.81 ;
    RECT 18.015 18.925 18.225 18.995 ;
    RECT 18.015 20.535 18.225 20.605 ;
    RECT 18.46 9.145 18.53 9.215 ;
    RECT 18.46 10.78 18.53 10.85 ;
    RECT 18.465 9.145 18.7 11.77 ;
    RECT 18.475 6.655 18.685 6.865 ;
    RECT 18.475 7.875 18.685 7.945 ;
    RECT 18.475 14.36 18.685 14.43 ;
    RECT 18.475 16.215 18.685 16.425 ;
    RECT 18.475 20.225 18.685 20.435 ;
    RECT 18.87 7.155 19.08 7.225 ;
    RECT 18.87 9.32 19.08 9.39 ;
    RECT 18.87 12.86 19.08 12.93 ;
    RECT 18.87 14.94 19.08 15.01 ;
    RECT 18.87 17.74 19.08 17.81 ;
    RECT 18.87 18.925 19.08 18.995 ;
    RECT 18.87 19.675 19.08 19.745 ;
    RECT 18.87 20.535 19.08 20.605 ;
    RECT 19.22 7.695 19.29 7.765 ;
    RECT 19.22 13.98 19.29 14.05 ;
    RECT 19.22 16.015 19.29 16.085 ;
    RECT 19.22 17.06 19.29 17.13 ;
    RECT 19.425 21.205 19.655 21.275 ;
    RECT 19.43 20.85 19.64 20.92 ;
    RECT 19.795 13.98 20.005 14.05 ;
    RECT 19.87 16.015 19.94 16.085 ;
    RECT 19.87 17.955 19.94 18.165 ;
    RECT 20.14 18.28 20.35 18.35 ;
    RECT 20.51 21.205 20.74 21.275 ;
    RECT 20.52 7.155 20.73 7.225 ;
    RECT 20.52 7.84 20.73 7.91 ;
    RECT 20.52 9.32 20.73 9.39 ;
    RECT 20.52 14.94 20.73 15.01 ;
    RECT 20.52 17.74 20.73 17.81 ;
    RECT 20.52 18.925 20.73 18.995 ;
    RECT 20.52 20.535 20.73 20.605 ;
    RECT 20.89 10.64 20.96 10.85 ;
    RECT 20.89 19.675 20.96 19.745 ;
    RECT 21.08 6.655 21.29 6.865 ;
    RECT 21.08 11.56 21.29 11.77 ;
    RECT 21.08 14.36 21.29 14.43 ;
    RECT 21.08 16.215 21.29 16.425 ;
    RECT 21.08 18.145 21.29 18.215 ;
    RECT 21.08 20.225 21.29 20.435 ;
    RECT 21.44 21.205 21.67 21.275 ;
    RECT 21.45 6.34 21.66 6.55 ;
    RECT 21.45 8.345 21.66 8.415 ;
    RECT 21.45 10.015 21.66 10.085 ;
    RECT 21.45 11.235 21.66 11.445 ;
    RECT 21.45 13.12 21.66 13.19 ;
    RECT 21.45 14.555 21.66 14.625 ;
    RECT 21.45 16.56 21.66 16.63 ;
    RECT 21.45 19.295 21.66 19.365 ;
    RECT 21.865 6.655 21.935 6.725 ;
    RECT 21.865 6.795 21.935 6.865 ;
    RECT 21.865 11.56 21.935 11.63 ;
    RECT 21.865 11.7 21.935 11.77 ;
    RECT 21.865 14.36 21.935 14.43 ;
    RECT 21.865 16.215 21.935 16.285 ;
    RECT 21.865 16.355 21.935 16.425 ;
    RECT 21.865 18.13 21.935 18.34 ;
    RECT 21.865 20.225 21.935 20.435 ;
    RECT 22.095 14.94 22.305 15.01 ;
    RECT 22.095 17.74 22.305 17.81 ;
    RECT 22.095 18.925 22.305 18.995 ;
    RECT 22.095 20.535 22.305 20.605 ;
    RECT 22.115 13.94 22.325 14.01 ;
    RECT 22.475 6.655 22.685 6.865 ;
    RECT 22.475 11.56 22.685 11.77 ;
    RECT 22.475 14.36 22.685 14.43 ;
    RECT 22.475 16.215 22.685 16.425 ;
    RECT 22.475 18.13 22.685 18.2 ;
    RECT 22.475 20.225 22.685 20.435 ;
    RECT 22.855 13.405 22.925 13.475 ;
    RECT 22.91 13.94 22.98 14.01 ;
    RECT 22.91 18.44 22.98 18.51 ;
    RECT 22.995 13.405 23.065 13.475 ;
    RECT 23.19 10.705 23.43 10.775 ;
    RECT 23.205 6.655 23.415 6.865 ;
    RECT 23.205 11.56 23.415 11.77 ;
    RECT 23.205 14.36 23.415 14.43 ;
    RECT 23.205 16.215 23.415 16.425 ;
    RECT 23.205 20.225 23.415 20.435 ;
    RECT 23.725 6.34 23.935 6.55 ;
    RECT 23.725 8.345 23.935 8.415 ;
    RECT 23.725 10.015 23.935 10.085 ;
    RECT 23.725 11.235 23.935 11.445 ;
    RECT 23.725 13.06 23.935 13.27 ;
    RECT 23.725 14.555 23.935 14.625 ;
    RECT 23.725 16.56 23.935 16.63 ;
    RECT 23.725 19.295 23.935 19.365 ;
    RECT 24.095 19.115 24.165 19.185 ;
    RECT 24.095 20.535 24.165 20.605 ;
    RECT 24.1 7.49 24.17 7.56 ;
    RECT 24.1 9.685 24.17 9.755 ;
    RECT 24.1 13.99 24.17 14.06 ;
    RECT 24.355 6.14 24.425 6.21 ;
    RECT 24.355 15.81 24.425 15.88 ;
    RECT 24.355 21.815 24.425 21.885 ;
    RECT 24.55 16.005 24.62 16.075 ;
    RECT 24.555 6.98 24.625 7.05 ;
    RECT 24.76 6.34 24.97 6.55 ;
    RECT 24.76 8.345 24.97 8.415 ;
    RECT 24.76 10.015 24.97 10.085 ;
    RECT 24.76 11.235 24.97 11.445 ;
    RECT 24.76 13.06 24.97 13.27 ;
    RECT 24.76 14.555 24.97 14.625 ;
    RECT 24.76 16.56 24.97 16.63 ;
    RECT 24.76 19.295 24.97 19.365 ;
    RECT 24.76 19.675 24.97 19.745 ;
    RECT 25.16 10.705 25.4 10.775 ;
    RECT 25.175 6.655 25.385 6.865 ;
    RECT 25.175 11.56 25.385 11.77 ;
    RECT 25.175 14.36 25.385 14.43 ;
    RECT 25.175 16.215 25.385 16.425 ;
    RECT 25.175 20.225 25.385 20.435 ;
    RECT 25.555 7.05 25.625 7.12 ;
    RECT 25.555 7.19 25.625 7.26 ;
    RECT 25.555 7.84 25.625 7.91 ;
    RECT 25.555 9.32 25.625 9.39 ;
    RECT 25.555 14.94 25.625 15.01 ;
    RECT 25.555 20.535 25.625 20.605 ;
    RECT 25.92 7.415 26.13 7.485 ;
    RECT 25.96 12.655 26.22 12.725 ;
    RECT 25.96 13.37 26.22 13.81 ;
    RECT 26.215 17.655 26.425 17.725 ;
    RECT 26.355 19.29 26.565 19.36 ;
    RECT 26.58 21.315 26.79 21.385 ;
    RECT 26.72 13.76 26.93 13.83 ;
    RECT 26.965 18.74 27.175 18.81 ;
    RECT 26.965 20.05 27.175 20.12 ;
    RECT 27.335 6.655 27.545 6.865 ;
    RECT 27.335 10.675 27.545 10.745 ;
    RECT 27.335 11.56 27.545 11.77 ;
    RECT 27.335 14.36 27.545 14.43 ;
    RECT 27.335 16.215 27.545 16.425 ;
    RECT 27.335 20.225 27.545 20.435 ;
    RECT 27.685 18.74 27.895 18.81 ;
    RECT 27.685 20.05 27.895 20.12 ;
    RECT 28.1 7.05 28.31 7.26 ;
    RECT 28.1 7.84 28.31 7.91 ;
    RECT 28.1 9.32 28.31 9.39 ;
    RECT 28.1 14.94 28.31 15.01 ;
    RECT 28.1 20.535 28.31 20.605 ;
    RECT 29.125 9.85 29.335 9.92 ;
    RECT 29.125 17.51 29.335 17.58 ;
    RECT 30.28 9.065 30.52 9.135 ;
    RECT 30.28 10.705 30.52 10.775 ;
    RECT 30.295 6.655 30.505 6.865 ;
    RECT 30.295 11.56 30.505 11.77 ;
    RECT 30.295 14.36 30.505 14.43 ;
    RECT 30.295 16.215 30.505 16.425 ;
    RECT 30.295 20.225 30.505 20.435 ;
    RECT 30.68 7.05 30.89 7.26 ;
    RECT 30.68 7.84 30.89 7.91 ;
    RECT 30.68 9.32 30.89 9.39 ;
    RECT 30.68 14.94 30.89 15.01 ;
    RECT 30.68 20.535 30.89 20.605 ;
    RECT 31.385 6.655 31.455 6.725 ;
    RECT 31.385 6.795 31.455 6.865 ;
    RECT 31.385 9.03 31.455 9.1 ;
    RECT 31.385 9.17 31.455 9.24 ;
    RECT 31.385 10.675 31.455 10.745 ;
    RECT 31.385 10.815 31.455 10.885 ;
    RECT 31.385 11.56 31.455 11.63 ;
    RECT 31.385 11.7 31.455 11.77 ;
    RECT 31.385 14.36 31.455 14.43 ;
    RECT 31.385 16.215 31.455 16.285 ;
    RECT 31.385 16.355 31.455 16.425 ;
    RECT 31.385 20.225 31.455 20.435 ;
    RECT 31.66 6.34 31.87 6.55 ;
    RECT 31.66 8.345 31.87 8.415 ;
    RECT 31.66 10.015 31.87 10.085 ;
    RECT 31.66 11.235 31.87 11.445 ;
    RECT 31.66 13.06 31.87 13.27 ;
    RECT 31.66 14.555 31.87 14.625 ;
    RECT 31.66 16.005 31.87 16.075 ;
    RECT 31.66 16.56 31.87 16.63 ;
    RECT 31.66 18.385 31.87 18.595 ;
    RECT 31.66 19.675 31.87 19.745 ;
    RECT 32.09 12.465 32.3 12.535 ;
    RECT 32.13 5.955 32.2 6.025 ;
    RECT 32.13 15.37 32.2 15.44 ;
    RECT 32.23 12.465 32.3 12.535 ;
    RECT 32.47 9.065 32.71 9.135 ;
    RECT 32.47 10.705 32.71 10.775 ;
    RECT 32.471 17.195 32.701 17.265 ;
    RECT 32.48 6.655 32.69 6.865 ;
    RECT 32.48 11.56 32.69 11.77 ;
    RECT 32.48 14.36 32.69 14.43 ;
    RECT 32.48 16.215 32.69 16.425 ;
    RECT 32.48 20.225 32.69 20.435 ;
    RECT 32.905 7.27 32.975 7.34 ;
    RECT 33.19 7.08 33.26 7.15 ;
    RECT 33.49 7.84 33.7 7.91 ;
    RECT 33.49 9.32 33.7 9.39 ;
    RECT 33.49 14.14 33.7 14.21 ;
    RECT 33.49 14.94 33.7 15.01 ;
    RECT 33.49 20.535 33.7 20.605 ;
    RECT 33.945 15.17 34.015 15.24 ;
    RECT 33.945 16.0 34.015 16.07 ;
    RECT 34.235 6.34 34.445 6.55 ;
    RECT 34.235 8.345 34.445 8.415 ;
    RECT 34.235 10.015 34.445 10.085 ;
    RECT 34.235 11.235 34.445 11.445 ;
    RECT 34.235 13.06 34.445 13.27 ;
    RECT 34.235 14.555 34.445 14.625 ;
    RECT 34.235 16.56 34.445 16.63 ;
    RECT 34.235 17.15 34.445 17.36 ;
    RECT 34.235 18.385 34.445 18.595 ;
    RECT 34.235 19.675 34.445 19.745 ;
    RECT 34.655 6.14 34.725 6.21 ;
    RECT 34.655 15.81 34.725 16.02 ;
    RECT 34.655 21.775 34.725 21.845 ;
    RECT 35.16 21.165 35.4 21.235 ;
    RECT 35.175 7.84 35.385 7.91 ;
    RECT 35.175 9.32 35.385 9.39 ;
    RECT 35.175 14.14 35.385 14.21 ;
    RECT 35.175 14.94 35.385 15.01 ;
    RECT 35.175 20.535 35.385 20.605 ;
    RECT 35.68 9.065 35.92 9.135 ;
    RECT 35.68 10.705 35.92 10.775 ;
    RECT 35.695 6.655 35.905 6.865 ;
    RECT 35.695 11.56 35.905 11.77 ;
    RECT 35.695 14.36 35.905 14.43 ;
    RECT 35.695 16.215 35.905 16.425 ;
    RECT 35.695 20.225 35.905 20.435 ;
    RECT 36.27 20.85 36.48 20.92 ;
    RECT 36.27 21.425 36.48 21.635 ;
    RECT 36.825 7.84 36.895 7.91 ;
    RECT 36.825 9.32 36.895 9.39 ;
    RECT 36.825 14.14 36.895 14.21 ;
    RECT 36.825 14.94 36.895 15.01 ;
    RECT 36.825 20.535 36.895 20.605 ;
    RECT 36.825 21.135 36.895 21.205 ;
    RECT 37.07 6.655 37.28 6.865 ;
    RECT 37.07 11.56 37.28 11.77 ;
    RECT 37.07 14.36 37.28 14.43 ;
    RECT 37.07 16.215 37.28 16.425 ;
    RECT 37.07 20.225 37.28 20.435 ;
    RECT 37.105 9.03 37.315 9.1 ;
    RECT 37.105 10.675 37.315 10.745 ;
    RECT 37.245 9.03 37.315 9.1 ;
    RECT 37.245 10.675 37.315 10.745 ;
    RECT 37.44 21.165 37.68 21.235 ;
    RECT 37.45 7.84 37.66 7.91 ;
    RECT 37.45 9.32 37.66 9.39 ;
    RECT 37.45 14.14 37.66 14.21 ;
    RECT 37.45 14.94 37.66 15.01 ;
    RECT 37.45 20.535 37.66 20.605 ;
    RECT 38.095 21.125 38.165 21.195 ;
    RECT 38.265 21.125 38.335 21.195 ;
    RECT 38.755 21.055 38.825 21.125 ;
    RECT 38.755 21.195 38.825 21.265 ;
    RECT 39.04 9.715 39.11 9.785 ;
    RECT 39.04 9.855 39.11 9.925 ;
    RECT 39.04 13.59 39.11 13.66 ;
    RECT 39.04 13.78 39.11 13.85 ;
    RECT 39.04 17.535 39.11 17.745 ;
    RECT 39.245 6.34 39.315 6.41 ;
    RECT 39.245 6.48 39.315 6.55 ;
    RECT 39.245 8.345 39.315 8.415 ;
    RECT 39.245 10.015 39.315 10.085 ;
    RECT 39.245 11.235 39.315 11.305 ;
    RECT 39.245 11.375 39.315 11.445 ;
    RECT 39.245 13.06 39.455 13.27 ;
    RECT 39.245 14.555 39.455 14.625 ;
    RECT 39.245 16.56 39.455 16.63 ;
    RECT 39.245 16.95 39.455 17.36 ;
    RECT 39.245 18.235 39.455 18.445 ;
    RECT 39.245 19.675 39.455 19.745 ;
    RECT 39.385 6.34 39.455 6.41 ;
    RECT 39.385 6.48 39.455 6.55 ;
    RECT 39.385 8.345 39.455 8.415 ;
    RECT 39.385 10.015 39.455 10.085 ;
    RECT 39.385 11.235 39.455 11.305 ;
    RECT 39.385 11.375 39.455 11.445 ;
    RECT 39.385 17.29 39.455 17.36 ;
    RECT 39.63 6.655 39.7 6.725 ;
    RECT 39.63 6.795 39.7 6.865 ;
    RECT 39.63 11.56 39.7 11.63 ;
    RECT 39.63 11.7 39.7 11.77 ;
    RECT 39.63 14.36 39.7 14.43 ;
    RECT 39.63 16.215 39.7 16.285 ;
    RECT 39.63 16.355 39.7 16.425 ;
    RECT 39.63 20.225 39.7 20.435 ;
    RECT 39.645 10.675 39.715 10.745 ;
    RECT 39.645 10.815 39.715 10.885 ;
    RECT 39.91 14.94 40.12 15.01 ;
    RECT 39.92 7.84 40.13 7.91 ;
    RECT 39.92 9.32 40.13 9.39 ;
    RECT 39.92 14.14 40.13 14.21 ;
    RECT 39.92 20.535 40.13 20.605 ;
    RECT 39.92 21.05 40.13 21.26 ;
    RECT 40.34 15.565 40.41 16.08 ;
    RECT 40.525 6.655 40.735 6.865 ;
    RECT 40.525 11.56 40.735 11.77 ;
    RECT 40.525 14.36 40.735 14.43 ;
    RECT 40.525 16.215 40.735 16.425 ;
    RECT 40.525 20.225 40.735 20.435 ;
    RECT 40.86 15.565 40.93 16.08 ;
    RECT 41.035 10.205 41.105 10.275 ;
    RECT 41.035 22.2 41.105 22.27 ;
    RECT 41.05 18.005 41.12 18.075 ;
    RECT 41.245 6.14 41.315 6.21 ;
    RECT 41.245 15.81 41.315 15.88 ;
    RECT 41.245 22.46 41.315 22.53 ;
    RECT 41.455 5.955 41.525 6.025 ;
    RECT 41.455 11.005 41.525 11.075 ;
    RECT 41.455 12.465 41.525 12.535 ;
    RECT 41.455 15.37 41.525 15.44 ;
    RECT 41.455 21.44 41.525 21.51 ;
    RECT 29.125 17.187 29.195 17.257 ;
    RECT 36.825 8.345 36.895 8.415 ;
    RECT 36.825 6.34 36.895 6.55 ;
    RECT 35.175 19.675 35.385 19.745 ;
    RECT 35.175 18.385 35.385 18.595 ;
    RECT 35.175 17.15 35.385 17.36 ;
    RECT 35.175 16.56 35.385 16.63 ;
    RECT 35.175 14.555 35.385 14.625 ;
    RECT 35.175 13.06 35.385 13.27 ;
    RECT 35.175 11.235 35.385 11.445 ;
    RECT 35.175 10.012 35.385 10.082 ;
    RECT 35.175 8.345 35.385 8.415 ;
    RECT 35.175 6.34 35.385 6.55 ;
    RECT 25.175 15.37 25.385 15.44 ;
    RECT 25.175 12.465 25.385 12.535 ;
    RECT 34.235 20.535 34.445 20.605 ;
    RECT 34.235 14.94 34.445 15.01 ;
    RECT 34.235 14.137 34.445 14.207 ;
    RECT 34.235 9.32 34.445 9.39 ;
    RECT 34.235 7.84 34.445 7.91 ;
    RECT 33.49 19.675 33.7 19.745 ;
    RECT 33.49 18.385 33.7 18.595 ;
    RECT 25.175 5.955 25.385 6.025 ;
    RECT 33.49 17.15 33.7 17.36 ;
    RECT 33.49 16.56 33.7 16.63 ;
    RECT 33.49 14.555 33.7 14.625 ;
    RECT 33.49 13.06 33.7 13.27 ;
    RECT 33.49 11.235 33.7 11.445 ;
    RECT 33.49 10.012 33.7 10.082 ;
    RECT 33.49 8.345 33.7 8.415 ;
    RECT 33.49 6.34 33.7 6.55 ;
    RECT 23.205 15.37 23.415 15.44 ;
    RECT 23.205 12.465 23.415 12.535 ;
    RECT 23.205 5.955 23.415 6.025 ;
    RECT 22.475 15.37 22.685 15.44 ;
    RECT 22.475 12.465 22.685 12.535 ;
    RECT 22.475 5.955 22.685 6.025 ;
    RECT 21.865 20.047 21.935 20.117 ;
    RECT 21.865 18.55 21.935 18.62 ;
    RECT 21.865 15.37 21.935 15.44 ;
    RECT 31.66 20.535 31.87 20.605 ;
    RECT 31.66 14.94 31.87 15.01 ;
    RECT 31.66 14.137 31.87 14.207 ;
    RECT 31.66 9.32 31.87 9.39 ;
    RECT 31.66 7.84 31.87 7.91 ;
    RECT 31.66 7.047 31.87 7.257 ;
    RECT 21.865 12.465 21.935 12.535 ;
    RECT 21.865 5.955 21.935 6.025 ;
    RECT 21.08 20.047 21.29 20.117 ;
    RECT 21.08 15.37 21.29 15.44 ;
    RECT 21.08 12.465 21.29 12.535 ;
    RECT 22.115 4.03 22.325 4.1 ;
    RECT 22.115 1.465 22.325 1.675 ;
    RECT 23.205 18.44 23.415 18.51 ;
    RECT 22.91 20.225 22.98 20.435 ;
    RECT 30.68 19.675 30.89 19.745 ;
    RECT 30.68 16.56 30.89 16.63 ;
    RECT 30.68 16.002 30.89 16.072 ;
    RECT 30.68 14.555 30.89 14.625 ;
    RECT 30.68 13.06 30.89 13.27 ;
    RECT 30.68 11.235 30.89 11.445 ;
    RECT 30.68 10.012 30.89 10.082 ;
    RECT 30.68 8.345 30.89 8.415 ;
    RECT 21.08 5.955 21.29 6.025 ;
    RECT 22.91 18.145 22.98 18.215 ;
    RECT 22.91 16.215 22.98 16.425 ;
    RECT 22.91 14.36 22.98 14.43 ;
    RECT 30.68 6.34 30.89 6.55 ;
    RECT 28.1 19.675 28.31 19.745 ;
    RECT 18.475 18.55 18.685 18.62 ;
    RECT 18.475 15.37 18.685 15.44 ;
    RECT 22.475 18.44 22.685 18.51 ;
    RECT 22.475 13.94 22.685 14.01 ;
    RECT 22.115 11.56 22.325 11.77 ;
    RECT 39.245 1.787 39.455 1.997 ;
    RECT 37.45 4.95 37.66 5.16 ;
    RECT 37.45 1.15 37.66 1.36 ;
    RECT 36.825 4.95 36.895 5.16 ;
    RECT 36.825 1.15 36.895 1.36 ;
    RECT 18.475 12.465 18.685 12.535 ;
    RECT 35.175 4.95 35.385 5.16 ;
    RECT 35.175 1.15 35.385 1.36 ;
    RECT 34.235 3.727 34.445 3.797 ;
    RECT 34.235 1.787 34.445 1.997 ;
    RECT 18.475 5.955 18.685 6.025 ;
    RECT 31.66 3.727 31.87 3.797 ;
    RECT 22.115 6.655 22.325 6.865 ;
    RECT 14.395 4.49 14.465 4.7 ;
    RECT 14.6 3.185 14.67 3.395 ;
    RECT 14.795 5.3 14.865 5.51 ;
    RECT 14.805 2.58 14.875 2.79 ;
    RECT 15.2 1.79 15.27 1.86 ;
    RECT 15.2 1.93 15.27 2.0 ;
    RECT 15.2 3.73 15.27 3.8 ;
    RECT 15.8 1.79 16.01 2.0 ;
    RECT 15.8 3.73 16.01 3.8 ;
    RECT 16.155 1.465 16.225 1.535 ;
    RECT 16.155 1.605 16.225 1.675 ;
    RECT 16.155 4.03 16.225 4.1 ;
    RECT 16.39 1.15 16.6 1.36 ;
    RECT 16.39 4.95 16.6 5.16 ;
    RECT 17.0 2.94 17.735 3.01 ;
    RECT 18.015 1.79 18.225 2.0 ;
    RECT 18.015 3.73 18.225 3.8 ;
    RECT 18.475 1.465 18.685 1.675 ;
    RECT 18.475 4.03 18.685 4.1 ;
    RECT 18.87 1.79 19.08 2.0 ;
    RECT 18.87 3.73 19.08 3.8 ;
    RECT 19.435 2.95 19.645 3.02 ;
    RECT 20.52 1.79 20.73 2.0 ;
    RECT 20.52 3.73 20.73 3.8 ;
    RECT 21.08 1.465 21.29 1.675 ;
    RECT 21.08 4.03 21.29 4.1 ;
    RECT 21.45 1.15 21.66 1.36 ;
    RECT 21.45 4.95 21.66 5.16 ;
    RECT 21.865 1.465 21.935 1.535 ;
    RECT 21.865 1.605 21.935 1.675 ;
    RECT 21.865 4.03 21.935 4.1 ;
    RECT 22.475 1.465 22.685 1.675 ;
    RECT 22.475 4.03 22.685 4.1 ;
    RECT 23.205 1.465 23.415 1.675 ;
    RECT 23.205 4.03 23.415 4.1 ;
    RECT 23.725 1.15 23.935 1.36 ;
    RECT 23.725 4.95 23.935 5.16 ;
    RECT 24.355 3.185 24.425 3.395 ;
    RECT 24.76 1.15 24.97 1.36 ;
    RECT 24.76 4.95 24.97 5.16 ;
    RECT 25.175 1.465 25.385 1.675 ;
    RECT 25.175 4.03 25.385 4.1 ;
    RECT 25.555 1.79 25.625 1.86 ;
    RECT 25.555 1.93 25.625 2.0 ;
    RECT 25.555 3.73 25.625 3.8 ;
    RECT 27.01 4.195 27.22 4.265 ;
    RECT 27.335 1.465 27.545 1.675 ;
    RECT 27.335 4.03 27.545 4.1 ;
    RECT 28.1 1.79 28.31 2.0 ;
    RECT 28.1 3.73 28.31 3.8 ;
    RECT 28.665 3.57 28.875 3.64 ;
    RECT 30.295 1.465 30.505 1.675 ;
    RECT 30.295 4.03 30.505 4.1 ;
    RECT 30.68 1.79 30.89 2.0 ;
    RECT 30.68 3.73 30.89 3.8 ;
    RECT 31.385 1.465 31.455 1.535 ;
    RECT 31.385 1.605 31.455 1.675 ;
    RECT 31.385 4.03 31.455 4.1 ;
    RECT 31.66 1.15 31.87 1.36 ;
    RECT 31.66 4.95 31.87 5.16 ;
    RECT 32.13 2.145 32.2 2.215 ;
    RECT 32.13 4.49 32.2 4.56 ;
    RECT 32.13 4.63 32.2 4.7 ;
    RECT 32.48 1.465 32.69 1.675 ;
    RECT 32.48 4.03 32.69 4.1 ;
    RECT 34.235 1.15 34.445 1.36 ;
    RECT 34.235 4.95 34.445 5.16 ;
    RECT 34.655 3.185 34.725 3.395 ;
    RECT 35.175 1.79 35.385 2.0 ;
    RECT 35.175 3.73 35.385 3.8 ;
    RECT 35.695 1.465 35.905 1.675 ;
    RECT 35.695 4.03 35.905 4.1 ;
    RECT 36.27 2.955 36.48 3.025 ;
    RECT 36.82 1.79 36.89 1.86 ;
    RECT 36.82 1.93 36.89 2.0 ;
    RECT 36.82 3.73 36.89 3.8 ;
    RECT 37.07 1.465 37.28 1.675 ;
    RECT 37.07 4.03 37.28 4.1 ;
    RECT 37.45 1.79 37.66 2.0 ;
    RECT 37.45 3.73 37.66 3.8 ;
    RECT 38.105 2.94 38.895 3.02 ;
    RECT 39.245 1.15 39.455 1.36 ;
    RECT 39.245 4.95 39.455 5.16 ;
    RECT 39.63 1.465 39.7 1.675 ;
    RECT 39.92 1.79 40.13 2.0 ;
    RECT 39.92 3.73 40.13 3.8 ;
    RECT 40.525 1.465 40.735 1.675 ;
    RECT 41.025 2.58 41.095 2.79 ;
    RECT 41.035 5.3 41.105 5.51 ;
    RECT 41.23 3.185 41.3 3.395 ;
    RECT 41.44 4.49 41.51 4.7 ;
    RECT 31.66 1.787 31.87 1.997 ;
    RECT 30.68 4.95 30.89 5.16 ;
    RECT 30.68 1.15 30.89 1.36 ;
    RECT 28.1 4.95 28.31 5.16 ;
    RECT 28.1 1.15 28.31 1.36 ;
    RECT 25.555 4.95 25.625 5.16 ;
    RECT 25.555 1.15 25.625 1.36 ;
    RECT 24.76 3.727 24.97 3.797 ;
    RECT 24.76 1.787 24.97 1.997 ;
    RECT 23.725 3.727 23.935 3.797 ;
    RECT 23.725 1.787 23.935 1.997 ;
    RECT 16.155 18.55 16.225 18.62 ;
    RECT 21.45 3.727 21.66 3.797 ;
    RECT 16.155 15.37 16.225 15.44 ;
    RECT 21.45 1.787 21.66 1.997 ;
    RECT 16.155 12.465 16.225 12.535 ;
    RECT 20.52 4.95 20.73 5.16 ;
    RECT 16.155 11.005 16.225 11.075 ;
    RECT 16.155 5.955 16.225 6.025 ;
    RECT 20.52 1.15 20.73 1.36 ;
    RECT 18.87 4.95 19.08 5.16 ;
    RECT 18.87 1.15 19.08 1.36 ;
    RECT 14.375 21.68 14.445 21.75 ;
    RECT 18.015 4.95 18.225 5.16 ;
    RECT 14.375 20.225 14.445 20.435 ;
    RECT 14.375 16.215 14.445 16.425 ;
    RECT 17.525 20.85 17.735 20.92 ;
    RECT 16.995 20.85 17.205 20.92 ;
    RECT 39.92 21.657 40.13 21.727 ;
    RECT 39.92 15.81 40.13 15.88 ;
    RECT 18.015 1.15 18.225 1.36 ;
    RECT 39.92 6.137 40.13 6.207 ;
    RECT 16.39 3.727 16.6 3.797 ;
    RECT 16.39 1.787 16.6 1.997 ;
    RECT 15.8 4.95 16.01 5.16 ;
    RECT 37.45 21.777 37.66 21.847 ;
    RECT 37.45 15.81 37.66 15.88 ;
    RECT 15.8 1.15 16.01 1.36 ;
    RECT 15.2 4.95 15.27 5.16 ;
    RECT 15.2 1.15 15.27 1.36 ;
    RECT 39.92 19.675 40.13 19.745 ;
    RECT 39.92 18.235 40.13 18.445 ;
    RECT 39.92 17.15 40.13 17.36 ;
    RECT 39.92 16.95 40.13 17.02 ;
    RECT 39.92 16.56 40.13 16.63 ;
    RECT 38.685 20.85 38.895 20.92 ;
    RECT 37.45 6.137 37.66 6.207 ;
    RECT 36.825 21.777 36.895 21.847 ;
    RECT 36.825 15.81 36.895 15.88 ;
    RECT 36.825 6.137 36.895 6.207 ;
    RECT 39.92 14.555 40.13 14.625 ;
    RECT 35.175 21.777 35.385 21.847 ;
    RECT 39.92 13.06 40.13 13.27 ;
    RECT 35.175 15.81 35.385 15.88 ;
    RECT 35.175 6.137 35.385 6.207 ;
    RECT 39.92 11.235 40.13 11.445 ;
    RECT 39.92 10.012 40.13 10.082 ;
    RECT 39.92 8.345 40.13 8.415 ;
    RECT 39.92 6.34 40.13 6.55 ;
    RECT 38.105 21.425 38.315 21.635 ;
    RECT 38.105 20.85 38.315 20.92 ;
    RECT 41.455 21.68 41.525 21.75 ;
    RECT 41.455 20.225 41.525 20.435 ;
    RECT 41.455 16.215 41.525 16.425 ;
    RECT 41.455 14.36 41.525 14.43 ;
    RECT 41.455 11.56 41.525 11.77 ;
    RECT 41.455 6.655 41.525 6.865 ;
    RECT 34.655 20.535 34.725 20.605 ;
    RECT 34.655 14.94 34.725 15.01 ;
    RECT 34.655 14.137 34.725 14.207 ;
    RECT 34.655 9.32 34.725 9.39 ;
    RECT 34.655 7.84 34.725 7.91 ;
    RECT 33.49 15.81 33.7 15.88 ;
    RECT 30.68 15.81 30.89 15.88 ;
    RECT 30.68 6.137 30.89 6.207 ;
    RECT 41.035 20.85 41.105 20.92 ;
    RECT 36.27 10.205 36.48 10.275 ;
    RECT 40.525 15.37 40.735 15.44 ;
    RECT 40.525 12.465 40.735 12.535 ;
    RECT 40.525 5.955 40.735 6.025 ;
    RECT 39.63 15.37 39.7 15.44 ;
    RECT 39.63 12.465 39.7 12.535 ;
    RECT 39.63 5.955 39.7 6.025 ;
    RECT 19.43 10.205 19.64 10.275 ;
    RECT 28.1 15.81 28.31 15.88 ;
    RECT 39.245 21.05 39.455 21.26 ;
    RECT 14.795 20.85 14.865 20.92 ;
    RECT 28.1 6.137 28.31 6.207 ;
    RECT 39.245 20.535 39.455 20.605 ;
    RECT 39.245 14.94 39.455 15.01 ;
    RECT 37.07 15.37 37.28 15.44 ;
    RECT 37.07 12.465 37.28 12.535 ;
    RECT 37.07 5.955 37.28 6.025 ;
    RECT 35.695 15.37 35.905 15.44 ;
    RECT 35.695 12.465 35.905 12.535 ;
    RECT 25.555 15.81 25.625 15.88 ;
    RECT 25.555 6.137 25.625 6.207 ;
    RECT 24.355 14.94 24.425 15.01 ;
    RECT 24.355 9.32 24.425 9.39 ;
    RECT 24.355 7.84 24.425 7.91 ;
    RECT 24.355 7.145 24.425 7.355 ;
    RECT 22.095 21.812 22.305 21.882 ;
    RECT 22.095 15.81 22.305 15.88 ;
    RECT 39.245 14.137 39.455 14.207 ;
    RECT 20.52 21.777 20.73 21.847 ;
    RECT 39.245 9.32 39.455 9.39 ;
    RECT 35.695 5.955 35.905 6.025 ;
    RECT 32.48 15.37 32.69 15.44 ;
    RECT 32.48 12.465 32.69 12.535 ;
    RECT 20.52 15.81 20.73 15.88 ;
    RECT 20.52 6.137 20.73 6.207 ;
    RECT 18.87 21.777 19.08 21.847 ;
    RECT 18.87 15.81 19.08 15.88 ;
    RECT 18.87 6.137 19.08 6.207 ;
    RECT 32.48 5.955 32.69 6.025 ;
    RECT 18.87 11.235 19.08 11.445 ;
    RECT 18.87 10.012 19.08 10.082 ;
    RECT 18.87 8.345 19.08 8.415 ;
    RECT 18.87 6.34 19.08 6.55 ;
    RECT 32.13 20.225 32.2 20.435 ;
    RECT 18.015 19.295 18.225 19.365 ;
    RECT 18.015 18.235 18.225 18.445 ;
    RECT 18.015 14.555 18.225 14.625 ;
    RECT 18.015 13.12 18.225 13.19 ;
    RECT 18.015 11.235 18.225 11.445 ;
    RECT 18.015 10.012 18.225 10.082 ;
    RECT 18.015 21.777 18.225 21.847 ;
    RECT 18.015 15.81 18.225 15.88 ;
    RECT 18.015 6.137 18.225 6.207 ;
    RECT 15.8 21.657 16.01 21.727 ;
    RECT 32.13 16.215 32.2 16.425 ;
    RECT 32.13 14.36 32.2 14.43 ;
    RECT 32.13 11.56 32.2 11.77 ;
    RECT 32.13 10.715 32.2 10.785 ;
    RECT 32.13 9.07 32.2 9.14 ;
    RECT 32.13 6.655 32.2 6.865 ;
    RECT 18.015 8.345 18.225 8.415 ;
    RECT 31.385 15.37 31.455 15.44 ;
    RECT 18.015 6.34 18.225 6.55 ;
    RECT 31.385 12.465 31.455 12.535 ;
    RECT 31.385 5.955 31.455 6.025 ;
    RECT 30.295 15.37 30.505 15.44 ;
    RECT 15.8 15.81 16.01 15.88 ;
    RECT 15.8 6.137 16.01 6.207 ;
    RECT 15.205 21.7 15.275 21.91 ;
    RECT 15.2 21.135 15.27 21.345 ;
    RECT 15.2 15.81 15.27 15.88 ;
    RECT 15.2 6.137 15.27 6.207 ;
    RECT 30.295 12.465 30.505 12.535 ;
    RECT 30.295 5.955 30.505 6.025 ;
    RECT 16.39 21.21 16.6 21.28 ;
    RECT 16.39 20.535 16.6 20.605 ;
    RECT 16.39 18.922 16.6 18.992 ;
    RECT 16.39 17.737 16.6 17.807 ;
    RECT 16.39 14.94 16.6 15.01 ;
    RECT 16.39 12.86 16.6 12.93 ;
    RECT 16.39 12.007 16.6 12.217 ;
    RECT 27.335 15.37 27.545 15.44 ;
    RECT 27.335 12.465 27.545 12.535 ;
    RECT 16.39 9.32 16.6 9.39 ;
    RECT 27.335 5.955 27.545 6.025 ;
    RECT 15.8 18.235 16.01 18.445 ;
    RECT 15.8 16.95 16.01 17.02 ;
    RECT 15.8 14.555 16.01 14.625 ;
    RECT 15.8 13.06 16.01 13.27 ;
    RECT 15.8 11.235 16.01 11.445 ;
    RECT 15.8 6.34 16.01 6.55 ;
    RECT 15.2 18.235 15.27 18.445 ;
    RECT 15.2 16.95 15.27 17.02 ;
    RECT 15.2 14.555 15.27 14.625 ;
    RECT 15.2 13.06 15.27 13.27 ;
    RECT 15.2 11.235 15.27 11.445 ;
    RECT 15.2 6.34 15.27 6.55 ;
    RECT 39.92 4.95 40.13 5.16 ;
    RECT 39.92 1.15 40.13 1.36 ;
    RECT 39.245 3.727 39.455 3.797 ;
    RECT 11.91 1.775 12.12 1.985 ;
    RECT 11.91 1.15 12.12 1.36 ;
    RECT 2.9 0.775 3.11 0.845 ;
    RECT 1.95 1.775 2.16 1.985 ;
    RECT 1.95 1.15 2.16 1.36 ;
    RECT 7.67 1.465 7.88 1.675 ;
    RECT 8.23 0.98 8.3 1.05 ;
    RECT 8.59 0.775 8.8 0.845 ;
    RECT 9.54 1.15 9.75 1.985 ;
    RECT 4.35 1.465 4.56 1.675 ;
    RECT 4.91 0.98 4.98 1.05 ;
    RECT 5.27 0.775 5.48 0.845 ;
    RECT 6.22 1.15 6.43 1.985 ;
    RECT 10.99 1.465 11.2 1.675 ;
    RECT 11.55 0.98 11.62 1.05 ;
    RECT 11.91 0.775 12.12 0.845 ;
    RECT 12.86 1.15 13.07 1.985 ;
    RECT 6.22 0.775 6.43 0.845 ;
    RECT 1.03 1.465 1.24 1.675 ;
    RECT 1.59 0.98 1.66 1.05 ;
    RECT 1.95 0.775 2.16 0.845 ;
    RECT 2.9 1.15 3.11 1.985 ;
    RECT 8.59 1.775 8.8 1.985 ;
    RECT 5.27 1.775 5.48 1.985 ;
    RECT 8.59 1.15 8.8 1.36 ;
    RECT 5.27 1.15 5.48 1.36 ;
    RECT 12.86 0.775 13.07 0.845 ;
    RECT 9.54 0.775 9.75 0.845 ;
    RECT 9.08 22.2 9.29 22.27 ;
    RECT 5.76 22.2 5.97 22.27 ;
    RECT 2.44 22.2 2.65 22.27 ;
    RECT 10.985 21.68 11.205 21.75 ;
    RECT 7.665 21.68 7.885 21.75 ;
    RECT 4.345 21.68 4.565 21.75 ;
    RECT 1.025 21.68 1.245 21.75 ;
    RECT 8.13 22.46 8.34 22.53 ;
    RECT 5.27 22.46 5.48 22.53 ;
    RECT 4.81 22.46 5.02 22.53 ;
    RECT 1.95 22.46 2.16 22.53 ;
    RECT 1.49 22.46 1.7 22.53 ;
    RECT 12.4 21.94 12.61 22.01 ;
    RECT 9.08 21.94 9.29 22.01 ;
    RECT 5.76 21.94 5.97 22.01 ;
    RECT 11.91 22.46 12.12 22.53 ;
    RECT 11.45 22.46 11.66 22.53 ;
    RECT 2.44 21.94 2.65 22.01 ;
    RECT 8.59 22.46 8.8 22.53 ;
    RECT 12.4 22.2 12.61 22.27 ;
    RECT 0.415 15.81 0.485 15.88 ;
    RECT 0.615 11.005 0.685 11.075 ;
    RECT 0.615 12.465 0.685 12.535 ;
    RECT 0.615 15.37 0.685 15.44 ;
    RECT 0.61 20.225 0.68 20.435 ;
    RECT 0.61 16.215 0.68 16.425 ;
    RECT 0.61 14.36 0.68 14.43 ;
    RECT 0.61 11.56 0.68 11.77 ;
    RECT 0.61 6.655 0.68 6.865 ;
    RECT 0.19 22.2 0.26 22.27 ;
    RECT 0.4 22.46 0.47 22.53 ;
    RECT 1.03 6.655 1.24 6.865 ;
    RECT 1.03 11.56 1.24 11.77 ;
    RECT 1.03 14.36 1.24 14.43 ;
    RECT 1.03 16.215 1.24 16.425 ;
    RECT 1.03 20.225 1.24 20.435 ;
    RECT 1.055 9.735 1.265 9.945 ;
    RECT 1.4 3.075 1.47 3.145 ;
    RECT 1.4 3.215 1.47 3.285 ;
    RECT 1.4 4.95 1.47 5.02 ;
    RECT 1.4 5.09 1.47 5.16 ;
    RECT 1.4 6.34 1.47 6.41 ;
    RECT 1.4 6.48 1.47 6.55 ;
    RECT 1.4 8.14 1.47 8.21 ;
    RECT 1.4 10.385 1.47 10.455 ;
    RECT 1.4 10.525 1.47 10.595 ;
    RECT 1.4 11.235 1.47 11.305 ;
    RECT 1.4 11.375 1.47 11.445 ;
    RECT 1.4 13.06 1.47 13.13 ;
    RECT 1.4 13.2 1.47 13.27 ;
    RECT 1.4 14.555 1.47 14.625 ;
    RECT 1.4 15.0 1.47 15.07 ;
    RECT 1.4 20.54 1.47 20.61 ;
    RECT 1.6 16.56 1.67 17.36 ;
    RECT 1.6 18.235 1.67 18.445 ;
    RECT 1.605 11.005 1.675 11.075 ;
    RECT 1.605 12.46 1.675 12.53 ;
    RECT 1.605 15.365 1.675 15.435 ;
    RECT 2.415 20.85 2.685 20.92 ;
    RECT 2.875 8.13 3.145 17.02 ;
    RECT 2.9 3.075 3.11 3.285 ;
    RECT 2.9 6.34 3.11 6.55 ;
    RECT 2.9 13.06 3.11 13.27 ;
    RECT 2.9 16.56 3.11 17.36 ;
    RECT 2.9 18.235 3.11 18.445 ;
    RECT 2.905 4.95 3.115 5.16 ;
    RECT 8.245 14.36 8.315 14.43 ;
    RECT 8.59 18.235 8.8 18.445 ;
    RECT 8.59 17.15 8.8 17.36 ;
    RECT 8.59 16.95 8.8 17.02 ;
    RECT 8.59 16.56 8.8 16.63 ;
    RECT 8.59 14.555 8.8 14.625 ;
    RECT 8.59 15.81 8.8 15.88 ;
    RECT 8.245 11.56 8.315 11.77 ;
    RECT 1.605 14.36 1.675 14.43 ;
    RECT 1.605 11.56 1.675 11.77 ;
    RECT 7.67 15.37 7.88 15.44 ;
    RECT 7.67 12.465 7.88 12.535 ;
    RECT 7.67 11.005 7.88 11.075 ;
    RECT 1.03 15.37 1.24 15.44 ;
    RECT 7.67 6.655 7.88 6.865 ;
    RECT 7.67 11.56 7.88 11.77 ;
    RECT 7.67 14.36 7.88 14.43 ;
    RECT 7.67 16.215 7.88 16.425 ;
    RECT 7.67 20.225 7.88 20.435 ;
    RECT 7.695 9.735 7.905 9.945 ;
    RECT 8.04 3.075 8.11 3.145 ;
    RECT 8.04 3.215 8.11 3.285 ;
    RECT 8.04 4.95 8.11 5.02 ;
    RECT 8.04 5.09 8.11 5.16 ;
    RECT 8.04 6.34 8.11 6.41 ;
    RECT 8.04 6.48 8.11 6.55 ;
    RECT 8.04 8.14 8.11 8.21 ;
    RECT 8.04 10.385 8.11 10.455 ;
    RECT 8.04 10.525 8.11 10.595 ;
    RECT 8.04 11.235 8.11 11.305 ;
    RECT 8.04 11.375 8.11 11.445 ;
    RECT 8.04 13.06 8.11 13.13 ;
    RECT 8.04 13.2 8.11 13.27 ;
    RECT 8.04 14.555 8.11 14.625 ;
    RECT 8.04 15.0 8.11 15.07 ;
    RECT 8.04 20.54 8.11 20.61 ;
    RECT 8.24 16.56 8.31 17.36 ;
    RECT 8.24 18.235 8.31 18.445 ;
    RECT 8.245 11.005 8.315 11.075 ;
    RECT 8.245 12.46 8.315 12.53 ;
    RECT 8.245 15.365 8.315 15.435 ;
    RECT 9.055 20.85 9.325 20.92 ;
    RECT 9.515 8.13 9.785 17.02 ;
    RECT 9.54 3.075 9.75 3.285 ;
    RECT 9.54 6.34 9.75 6.55 ;
    RECT 9.54 13.06 9.75 13.27 ;
    RECT 9.54 16.56 9.75 17.36 ;
    RECT 9.54 18.235 9.75 18.445 ;
    RECT 9.545 4.95 9.755 5.16 ;
    RECT 1.03 12.465 1.24 12.535 ;
    RECT 1.95 18.235 2.16 18.445 ;
    RECT 4.35 6.655 4.56 6.865 ;
    RECT 4.35 11.56 4.56 11.77 ;
    RECT 4.35 14.36 4.56 14.43 ;
    RECT 4.35 16.215 4.56 16.425 ;
    RECT 4.35 20.225 4.56 20.435 ;
    RECT 4.375 9.735 4.585 9.945 ;
    RECT 4.72 3.075 4.79 3.145 ;
    RECT 4.72 3.215 4.79 3.285 ;
    RECT 4.72 4.95 4.79 5.02 ;
    RECT 4.72 5.09 4.79 5.16 ;
    RECT 4.72 6.34 4.79 6.41 ;
    RECT 4.72 6.48 4.79 6.55 ;
    RECT 4.72 8.14 4.79 8.21 ;
    RECT 4.72 10.385 4.79 10.455 ;
    RECT 4.72 10.525 4.79 10.595 ;
    RECT 4.72 11.235 4.79 11.305 ;
    RECT 4.72 11.375 4.79 11.445 ;
    RECT 4.72 13.06 4.79 13.13 ;
    RECT 4.72 13.2 4.79 13.27 ;
    RECT 4.72 14.555 4.79 14.625 ;
    RECT 4.72 15.0 4.79 15.07 ;
    RECT 4.72 20.54 4.79 20.61 ;
    RECT 4.92 16.56 4.99 17.36 ;
    RECT 4.92 18.235 4.99 18.445 ;
    RECT 4.925 11.005 4.995 11.075 ;
    RECT 4.925 12.46 4.995 12.53 ;
    RECT 4.925 15.365 4.995 15.435 ;
    RECT 5.735 20.85 6.005 20.92 ;
    RECT 6.195 8.13 6.465 17.02 ;
    RECT 6.22 3.075 6.43 3.285 ;
    RECT 6.22 6.34 6.43 6.55 ;
    RECT 6.22 13.06 6.43 13.27 ;
    RECT 6.22 16.56 6.43 17.36 ;
    RECT 6.22 18.235 6.43 18.445 ;
    RECT 6.225 4.95 6.435 5.16 ;
    RECT 1.03 11.005 1.24 11.075 ;
    RECT 8.59 13.06 8.8 13.27 ;
    RECT 8.59 11.235 8.8 11.445 ;
    RECT 8.59 10.385 8.8 10.595 ;
    RECT 8.59 8.125 8.8 8.195 ;
    RECT 8.59 6.34 8.8 6.55 ;
    RECT 8.59 4.95 8.8 5.16 ;
    RECT 8.59 3.075 8.8 3.285 ;
    RECT 1.95 17.15 2.16 17.36 ;
    RECT 1.95 16.95 2.16 17.02 ;
    RECT 1.95 16.56 2.16 16.63 ;
    RECT 1.95 14.555 2.16 14.625 ;
    RECT 1.95 13.06 2.16 13.27 ;
    RECT 1.95 11.235 2.16 11.445 ;
    RECT 1.95 10.385 2.16 10.595 ;
    RECT 1.95 8.125 2.16 8.195 ;
    RECT 1.95 6.34 2.16 6.55 ;
    RECT 1.95 4.95 2.16 5.16 ;
    RECT 5.27 15.81 5.48 15.88 ;
    RECT 11.565 14.36 11.635 14.43 ;
    RECT 11.565 11.56 11.635 11.77 ;
    RECT 1.95 3.075 2.16 3.285 ;
    RECT 11.91 18.235 12.12 18.445 ;
    RECT 11.91 17.15 12.12 17.36 ;
    RECT 11.91 16.95 12.12 17.02 ;
    RECT 11.91 16.56 12.12 16.63 ;
    RECT 11.91 14.555 12.12 14.625 ;
    RECT 5.27 18.235 5.48 18.445 ;
    RECT 11.91 13.06 12.12 13.27 ;
    RECT 5.27 17.15 5.48 17.36 ;
    RECT 11.91 11.235 12.12 11.445 ;
    RECT 5.27 16.95 5.48 17.02 ;
    RECT 11.91 15.81 12.12 15.88 ;
    RECT 4.925 14.36 4.995 14.43 ;
    RECT 4.925 11.56 4.995 11.77 ;
    RECT 11.91 10.385 12.12 10.595 ;
    RECT 10.99 15.37 11.2 15.44 ;
    RECT 11.91 8.125 12.12 8.195 ;
    RECT 10.99 12.465 11.2 12.535 ;
    RECT 11.91 6.34 12.12 6.55 ;
    RECT 10.99 11.005 11.2 11.075 ;
    RECT 11.91 4.95 12.12 5.16 ;
    RECT 4.35 15.37 4.56 15.44 ;
    RECT 11.91 3.075 12.12 3.285 ;
    RECT 4.35 12.465 4.56 12.535 ;
    RECT 4.35 11.005 4.56 11.075 ;
    RECT 1.95 15.81 2.16 15.88 ;
    RECT 5.27 16.56 5.48 16.63 ;
    RECT 5.27 14.555 5.48 14.625 ;
    RECT 5.27 13.06 5.48 13.27 ;
    RECT 5.27 11.235 5.48 11.445 ;
    RECT 5.27 10.385 5.48 10.595 ;
    RECT 5.27 8.125 5.48 8.195 ;
    RECT 5.27 6.34 5.48 6.55 ;
    RECT 5.27 4.95 5.48 5.16 ;
    RECT 5.27 3.075 5.48 3.285 ;
    RECT 10.99 6.655 11.2 6.865 ;
    RECT 10.99 11.56 11.2 11.77 ;
    RECT 10.99 14.36 11.2 14.43 ;
    RECT 10.99 16.215 11.2 16.425 ;
    RECT 10.99 20.225 11.2 20.435 ;
    RECT 11.015 9.735 11.225 9.945 ;
    RECT 11.36 3.075 11.43 3.145 ;
    RECT 11.36 3.215 11.43 3.285 ;
    RECT 11.36 4.95 11.43 5.02 ;
    RECT 11.36 5.09 11.43 5.16 ;
    RECT 11.36 6.34 11.43 6.41 ;
    RECT 11.36 6.48 11.43 6.55 ;
    RECT 11.36 8.14 11.43 8.21 ;
    RECT 11.36 10.385 11.43 10.455 ;
    RECT 11.36 10.525 11.43 10.595 ;
    RECT 11.36 11.235 11.43 11.305 ;
    RECT 11.36 11.375 11.43 11.445 ;
    RECT 11.36 13.06 11.43 13.13 ;
    RECT 11.36 13.2 11.43 13.27 ;
    RECT 11.36 14.555 11.43 14.625 ;
    RECT 11.36 15.0 11.43 15.07 ;
    RECT 11.36 20.54 11.43 20.61 ;
    RECT 11.56 16.56 11.63 17.36 ;
    RECT 11.56 18.235 11.63 18.445 ;
    RECT 11.565 11.005 11.635 11.075 ;
    RECT 11.565 12.46 11.635 12.53 ;
    RECT 11.565 15.365 11.635 15.435 ;
    RECT 12.375 20.85 12.645 20.92 ;
    RECT 12.835 8.13 13.105 17.02 ;
    RECT 12.86 3.075 13.07 3.285 ;
    RECT 12.86 6.34 13.07 6.55 ;
    RECT 12.86 13.06 13.07 13.27 ;
    RECT 12.86 16.56 13.07 17.36 ;
    RECT 12.86 18.235 13.07 18.445 ;
    RECT 12.865 4.95 13.075 5.16 ;
    RECT 39.245 47.697 39.455 47.767 ;
    RECT 17.525 47.425 17.735 47.495 ;
    RECT 34.235 47.697 34.445 47.767 ;
    RECT 16.995 47.425 17.205 47.495 ;
    RECT 11.445 47.685 11.655 47.755 ;
    RECT 11.92 47.685 12.13 47.755 ;
    RECT 12.405 47.405 12.615 47.475 ;
    RECT 8.125 47.685 8.335 47.755 ;
    RECT 8.6 47.685 8.81 47.755 ;
    RECT 9.085 47.405 9.295 47.475 ;
    RECT 4.805 47.685 5.015 47.755 ;
    RECT 5.28 47.685 5.49 47.755 ;
    RECT 5.765 47.405 5.975 47.475 ;
    RECT 1.485 47.685 1.695 47.755 ;
    RECT 1.96 47.685 2.17 47.755 ;
    RECT 2.445 47.405 2.655 47.475 ;
    RECT 55.43 47.705 55.5 47.775 ;
    RECT 24.76 47.697 24.97 47.767 ;
    RECT 23.725 47.697 23.935 47.767 ;
    RECT 16.39 47.697 16.6 47.767 ;
    RECT 15.2 47.705 15.27 47.775 ;
    RECT 15.49 47.425 15.56 47.495 ;
    RECT 15.8 47.705 16.01 47.775 ;
    RECT 18.015 47.705 18.225 47.775 ;
    RECT 18.87 47.705 19.08 47.775 ;
    RECT 19.43 47.425 19.64 47.495 ;
    RECT 20.52 47.705 20.73 47.775 ;
    RECT 25.56 47.705 25.63 47.775 ;
    RECT 28.1 47.705 28.31 47.775 ;
    RECT 30.68 47.705 30.89 47.775 ;
    RECT 33.49 47.7 33.7 47.77 ;
    RECT 35.175 47.705 35.385 47.775 ;
    RECT 36.27 47.425 36.48 47.495 ;
    RECT 36.83 47.705 36.9 47.775 ;
    RECT 37.45 47.705 37.66 47.775 ;
    RECT 39.92 47.705 40.13 47.775 ;
    RECT 55.64 47.425 55.71 47.495 ;
    RECT 54.205 47.685 54.415 47.755 ;
    RECT 53.73 47.685 53.94 47.755 ;
    RECT 53.245 47.405 53.455 47.475 ;
    RECT 50.885 47.685 51.095 47.755 ;
    RECT 50.41 47.685 50.62 47.755 ;
    RECT 49.925 47.405 50.135 47.475 ;
    RECT 47.565 47.685 47.775 47.755 ;
    RECT 47.09 47.685 47.3 47.755 ;
    RECT 46.605 47.405 46.815 47.475 ;
    RECT 44.245 47.685 44.455 47.755 ;
    RECT 43.77 47.685 43.98 47.755 ;
    RECT 43.285 47.405 43.495 47.475 ;
    RECT 38.685 47.425 38.895 47.495 ;
    RECT 38.105 47.425 38.315 47.495 ;
    RECT 0.19 47.425 0.26 47.495 ;
    RECT 0.4 47.705 0.47 47.775 ;
    LAYER M4 DESIGNRULEWIDTH 0.165 ;
    RECT 11.48 0.0 11.55 0.33 ;
    RECT 11.55 0.0 11.62 0.695 ;
    RECT 12.825 0.385 13.105 0.695 ;
    RECT 54.31 0.0 54.38 0.33 ;
    RECT 54.24 0.0 54.31 0.695 ;
    RECT 52.755 0.385 53.035 0.695 ;
    RECT 8.16 0.0 8.23 0.33 ;
    RECT 8.23 0.0 8.3 0.695 ;
    RECT 9.505 0.385 9.785 0.695 ;
    RECT 50.99 0.0 51.06 0.33 ;
    RECT 50.92 0.0 50.99 0.695 ;
    RECT 49.435 0.385 49.715 0.695 ;
    RECT 4.84 0.0 4.91 0.33 ;
    RECT 4.91 0.0 4.98 0.695 ;
    RECT 6.185 0.385 6.465 0.695 ;
    RECT 47.67 0.0 47.74 0.33 ;
    RECT 47.6 0.0 47.67 0.695 ;
    RECT 46.115 0.385 46.395 0.695 ;
    RECT 1.52 0.0 1.59 0.33 ;
    RECT 1.59 0.0 1.66 0.695 ;
    RECT 2.865 0.385 3.145 0.695 ;
    RECT 44.35 0.0 44.42 0.33 ;
    RECT 44.28 0.0 44.35 0.695 ;
    RECT 42.795 0.385 43.075 0.695 ;
    RECT 14.205 0.0 14.285 0.695 ;
    RECT 14.955 0.0 15.09 0.695 ;
    RECT 15.38 0.0 15.73 0.695 ;
    RECT 16.315 0.0 17.88 0.695 ;
    RECT 19.15 0.0 19.305 0.695 ;
    RECT 19.765 0.32 20.39 0.695 ;
    RECT 19.765 0.0 20.0 0.32 ;
    RECT 20.86 0.0 21.01 0.695 ;
    RECT 21.36 0.0 21.755 0.695 ;
    RECT 22.045 0.0 22.365 0.695 ;
    RECT 22.795 0.0 23.075 0.695 ;
    RECT 23.545 0.0 24.245 0.695 ;
    RECT 24.535 0.0 25.045 0.695 ;
    RECT 25.715 0.0 27.265 0.695 ;
    RECT 27.615 0.0 27.965 0.695 ;
    RECT 28.445 0.0 30.16 0.695 ;
    RECT 30.96 0.0 31.28 0.695 ;
    RECT 31.56 0.0 32.02 0.695 ;
    RECT 32.82 0.0 34.545 0.695 ;
    RECT 34.835 0.0 35.04 0.695 ;
    RECT 36.04 0.0 36.2 0.695 ;
    RECT 36.55 0.0 36.72 0.695 ;
    RECT 37.79 0.0 39.035 0.695 ;
    RECT 39.035 0.0 39.115 0.79 ;
    RECT 39.115 0.0 39.525 0.695 ;
    RECT 40.265 0.0 40.31 0.695 ;
    RECT 40.31 0.0 40.405 0.775 ;
    RECT 40.405 0.0 40.455 0.695 ;
    RECT 40.805 0.0 40.945 0.695 ;
    RECT 41.615 0.0 41.695 0.695 ;
    RECT 14.97 40.735 15.09 41.455 ;
    RECT 15.38 40.735 15.73 41.455 ;
    RECT 16.315 40.735 17.88 41.455 ;
    RECT 19.15 40.735 19.305 41.455 ;
    RECT 19.765 40.735 20.39 41.455 ;
    RECT 20.86 40.735 21.01 41.455 ;
    RECT 21.36 40.735 21.755 41.455 ;
    RECT 22.045 40.735 22.365 41.455 ;
    RECT 22.795 40.735 23.075 41.455 ;
    RECT 23.545 40.735 24.245 41.455 ;
    RECT 24.535 40.735 25.045 41.455 ;
    RECT 25.715 40.735 27.265 41.455 ;
    RECT 27.615 40.735 27.965 41.455 ;
    RECT 28.62 40.735 30.16 41.455 ;
    RECT 30.96 40.735 31.28 41.455 ;
    RECT 31.56 40.735 32.02 41.455 ;
    RECT 32.82 40.735 33.36 41.455 ;
    RECT 33.83 40.735 34.545 41.455 ;
    RECT 34.835 40.735 35.04 41.455 ;
    RECT 36.04 40.735 36.2 41.455 ;
    RECT 36.55 40.735 36.72 41.455 ;
    RECT 37.79 40.735 39.525 41.455 ;
    RECT 40.265 40.735 40.455 41.455 ;
    RECT 40.805 40.735 40.93 41.455 ;
    RECT 14.97 40.015 15.09 40.735 ;
    RECT 15.38 40.015 15.73 40.735 ;
    RECT 16.315 40.015 17.88 40.735 ;
    RECT 19.15 40.015 19.305 40.735 ;
    RECT 19.765 40.015 20.39 40.735 ;
    RECT 20.86 40.015 21.01 40.735 ;
    RECT 21.36 40.015 21.755 40.735 ;
    RECT 22.045 40.015 22.365 40.735 ;
    RECT 22.795 40.015 23.075 40.735 ;
    RECT 23.545 40.015 24.245 40.735 ;
    RECT 24.535 40.015 25.045 40.735 ;
    RECT 25.715 40.015 27.265 40.735 ;
    RECT 27.615 40.015 27.965 40.735 ;
    RECT 28.62 40.015 30.16 40.735 ;
    RECT 30.96 40.015 31.28 40.735 ;
    RECT 31.56 40.015 32.02 40.735 ;
    RECT 32.82 40.015 33.36 40.735 ;
    RECT 33.83 40.015 34.545 40.735 ;
    RECT 34.835 40.015 35.04 40.735 ;
    RECT 36.04 40.015 36.2 40.735 ;
    RECT 36.55 40.015 36.72 40.735 ;
    RECT 37.79 40.015 39.525 40.735 ;
    RECT 40.265 40.015 40.455 40.735 ;
    RECT 40.805 40.015 40.93 40.735 ;
    RECT 14.97 39.295 15.09 40.015 ;
    RECT 15.38 39.295 15.73 40.015 ;
    RECT 16.315 39.295 17.88 40.015 ;
    RECT 19.15 39.295 19.305 40.015 ;
    RECT 19.765 39.295 20.39 40.015 ;
    RECT 20.86 39.295 21.01 40.015 ;
    RECT 21.36 39.295 21.755 40.015 ;
    RECT 22.045 39.295 22.365 40.015 ;
    RECT 22.795 39.295 23.075 40.015 ;
    RECT 23.545 39.295 24.245 40.015 ;
    RECT 24.535 39.295 25.045 40.015 ;
    RECT 25.715 39.295 27.265 40.015 ;
    RECT 27.615 39.295 27.965 40.015 ;
    RECT 28.62 39.295 30.16 40.015 ;
    RECT 30.96 39.295 31.28 40.015 ;
    RECT 31.56 39.295 32.02 40.015 ;
    RECT 32.82 39.295 33.36 40.015 ;
    RECT 33.83 39.295 34.545 40.015 ;
    RECT 34.835 39.295 35.04 40.015 ;
    RECT 36.04 39.295 36.2 40.015 ;
    RECT 36.55 39.295 36.72 40.015 ;
    RECT 37.79 39.295 39.525 40.015 ;
    RECT 40.265 39.295 40.455 40.015 ;
    RECT 40.805 39.295 40.93 40.015 ;
    RECT 14.97 38.575 15.09 39.295 ;
    RECT 15.38 38.575 15.73 39.295 ;
    RECT 16.315 38.575 17.88 39.295 ;
    RECT 19.15 38.575 19.305 39.295 ;
    RECT 19.765 38.575 20.39 39.295 ;
    RECT 20.86 38.575 21.01 39.295 ;
    RECT 21.36 38.575 21.755 39.295 ;
    RECT 22.045 38.575 22.365 39.295 ;
    RECT 22.795 38.575 23.075 39.295 ;
    RECT 23.545 38.575 24.245 39.295 ;
    RECT 24.535 38.575 25.045 39.295 ;
    RECT 25.715 38.575 27.265 39.295 ;
    RECT 27.615 38.575 27.965 39.295 ;
    RECT 28.62 38.575 30.16 39.295 ;
    RECT 30.96 38.575 31.28 39.295 ;
    RECT 31.56 38.575 32.02 39.295 ;
    RECT 32.82 38.575 33.36 39.295 ;
    RECT 33.83 38.575 34.545 39.295 ;
    RECT 34.835 38.575 35.04 39.295 ;
    RECT 36.04 38.575 36.2 39.295 ;
    RECT 36.55 38.575 36.72 39.295 ;
    RECT 37.79 38.575 39.525 39.295 ;
    RECT 40.265 38.575 40.455 39.295 ;
    RECT 40.805 38.575 40.93 39.295 ;
    RECT 14.97 37.855 15.09 38.575 ;
    RECT 15.38 37.855 15.73 38.575 ;
    RECT 16.315 37.855 17.88 38.575 ;
    RECT 19.15 37.855 19.305 38.575 ;
    RECT 19.765 37.855 20.39 38.575 ;
    RECT 20.86 37.855 21.01 38.575 ;
    RECT 21.36 37.855 21.755 38.575 ;
    RECT 22.045 37.855 22.365 38.575 ;
    RECT 22.795 37.855 23.075 38.575 ;
    RECT 23.545 37.855 24.245 38.575 ;
    RECT 24.535 37.855 25.045 38.575 ;
    RECT 25.715 37.855 27.265 38.575 ;
    RECT 27.615 37.855 27.965 38.575 ;
    RECT 28.62 37.855 30.16 38.575 ;
    RECT 30.96 37.855 31.28 38.575 ;
    RECT 31.56 37.855 32.02 38.575 ;
    RECT 32.82 37.855 33.36 38.575 ;
    RECT 33.83 37.855 34.545 38.575 ;
    RECT 34.835 37.855 35.04 38.575 ;
    RECT 36.04 37.855 36.2 38.575 ;
    RECT 36.55 37.855 36.72 38.575 ;
    RECT 37.79 37.855 39.525 38.575 ;
    RECT 40.265 37.855 40.455 38.575 ;
    RECT 40.805 37.855 40.93 38.575 ;
    RECT 14.97 37.135 15.09 37.855 ;
    RECT 15.38 37.135 15.73 37.855 ;
    RECT 16.315 37.135 17.88 37.855 ;
    RECT 19.15 37.135 19.305 37.855 ;
    RECT 19.765 37.135 20.39 37.855 ;
    RECT 20.86 37.135 21.01 37.855 ;
    RECT 21.36 37.135 21.755 37.855 ;
    RECT 22.045 37.135 22.365 37.855 ;
    RECT 22.795 37.135 23.075 37.855 ;
    RECT 23.545 37.135 24.245 37.855 ;
    RECT 24.535 37.135 25.045 37.855 ;
    RECT 25.715 37.135 27.265 37.855 ;
    RECT 27.615 37.135 27.965 37.855 ;
    RECT 28.62 37.135 30.16 37.855 ;
    RECT 30.96 37.135 31.28 37.855 ;
    RECT 31.56 37.135 32.02 37.855 ;
    RECT 32.82 37.135 33.36 37.855 ;
    RECT 33.83 37.135 34.545 37.855 ;
    RECT 34.835 37.135 35.04 37.855 ;
    RECT 36.04 37.135 36.2 37.855 ;
    RECT 36.55 37.135 36.72 37.855 ;
    RECT 37.79 37.135 39.525 37.855 ;
    RECT 40.265 37.135 40.455 37.855 ;
    RECT 40.805 37.135 40.93 37.855 ;
    RECT 14.97 36.415 15.09 37.135 ;
    RECT 15.38 36.415 15.73 37.135 ;
    RECT 16.315 36.415 17.88 37.135 ;
    RECT 19.15 36.415 19.305 37.135 ;
    RECT 19.765 36.415 20.39 37.135 ;
    RECT 20.86 36.415 21.01 37.135 ;
    RECT 21.36 36.415 21.755 37.135 ;
    RECT 22.045 36.415 22.365 37.135 ;
    RECT 22.795 36.415 23.075 37.135 ;
    RECT 23.545 36.415 24.245 37.135 ;
    RECT 24.535 36.415 25.045 37.135 ;
    RECT 25.715 36.415 27.265 37.135 ;
    RECT 27.615 36.415 27.965 37.135 ;
    RECT 28.62 36.415 30.16 37.135 ;
    RECT 30.96 36.415 31.28 37.135 ;
    RECT 31.56 36.415 32.02 37.135 ;
    RECT 32.82 36.415 33.36 37.135 ;
    RECT 33.83 36.415 34.545 37.135 ;
    RECT 34.835 36.415 35.04 37.135 ;
    RECT 36.04 36.415 36.2 37.135 ;
    RECT 36.55 36.415 36.72 37.135 ;
    RECT 37.79 36.415 39.525 37.135 ;
    RECT 40.265 36.415 40.455 37.135 ;
    RECT 40.805 36.415 40.93 37.135 ;
    RECT 14.97 35.695 15.09 36.415 ;
    RECT 15.38 35.695 15.73 36.415 ;
    RECT 16.315 35.695 17.88 36.415 ;
    RECT 19.15 35.695 19.305 36.415 ;
    RECT 19.765 35.695 20.39 36.415 ;
    RECT 20.86 35.695 21.01 36.415 ;
    RECT 21.36 35.695 21.755 36.415 ;
    RECT 22.045 35.695 22.365 36.415 ;
    RECT 22.795 35.695 23.075 36.415 ;
    RECT 23.545 35.695 24.245 36.415 ;
    RECT 24.535 35.695 25.045 36.415 ;
    RECT 25.715 35.695 27.265 36.415 ;
    RECT 27.615 35.695 27.965 36.415 ;
    RECT 28.62 35.695 30.16 36.415 ;
    RECT 30.96 35.695 31.28 36.415 ;
    RECT 31.56 35.695 32.02 36.415 ;
    RECT 32.82 35.695 33.36 36.415 ;
    RECT 33.83 35.695 34.545 36.415 ;
    RECT 34.835 35.695 35.04 36.415 ;
    RECT 36.04 35.695 36.2 36.415 ;
    RECT 36.55 35.695 36.72 36.415 ;
    RECT 37.79 35.695 39.525 36.415 ;
    RECT 40.265 35.695 40.455 36.415 ;
    RECT 40.805 35.695 40.93 36.415 ;
    RECT 14.97 34.975 15.09 35.695 ;
    RECT 15.38 34.975 15.73 35.695 ;
    RECT 16.315 34.975 17.88 35.695 ;
    RECT 19.15 34.975 19.305 35.695 ;
    RECT 19.765 34.975 20.39 35.695 ;
    RECT 20.86 34.975 21.01 35.695 ;
    RECT 21.36 34.975 21.755 35.695 ;
    RECT 22.045 34.975 22.365 35.695 ;
    RECT 22.795 34.975 23.075 35.695 ;
    RECT 23.545 34.975 24.245 35.695 ;
    RECT 24.535 34.975 25.045 35.695 ;
    RECT 25.715 34.975 27.265 35.695 ;
    RECT 27.615 34.975 27.965 35.695 ;
    RECT 28.62 34.975 30.16 35.695 ;
    RECT 30.96 34.975 31.28 35.695 ;
    RECT 31.56 34.975 32.02 35.695 ;
    RECT 32.82 34.975 33.36 35.695 ;
    RECT 33.83 34.975 34.545 35.695 ;
    RECT 34.835 34.975 35.04 35.695 ;
    RECT 36.04 34.975 36.2 35.695 ;
    RECT 36.55 34.975 36.72 35.695 ;
    RECT 37.79 34.975 39.525 35.695 ;
    RECT 40.265 34.975 40.455 35.695 ;
    RECT 40.805 34.975 40.93 35.695 ;
    RECT 14.97 34.255 15.09 34.975 ;
    RECT 15.38 34.255 15.73 34.975 ;
    RECT 16.315 34.255 17.88 34.975 ;
    RECT 19.15 34.255 19.305 34.975 ;
    RECT 19.765 34.255 20.39 34.975 ;
    RECT 20.86 34.255 21.01 34.975 ;
    RECT 21.36 34.255 21.755 34.975 ;
    RECT 22.045 34.255 22.365 34.975 ;
    RECT 22.795 34.255 23.075 34.975 ;
    RECT 23.545 34.255 24.245 34.975 ;
    RECT 24.535 34.255 25.045 34.975 ;
    RECT 25.715 34.255 27.265 34.975 ;
    RECT 27.615 34.255 27.965 34.975 ;
    RECT 28.62 34.255 30.16 34.975 ;
    RECT 30.96 34.255 31.28 34.975 ;
    RECT 31.56 34.255 32.02 34.975 ;
    RECT 32.82 34.255 33.36 34.975 ;
    RECT 33.83 34.255 34.545 34.975 ;
    RECT 34.835 34.255 35.04 34.975 ;
    RECT 36.04 34.255 36.2 34.975 ;
    RECT 36.55 34.255 36.72 34.975 ;
    RECT 37.79 34.255 39.525 34.975 ;
    RECT 40.265 34.255 40.455 34.975 ;
    RECT 40.805 34.255 40.93 34.975 ;
    RECT 14.97 45.055 15.09 45.775 ;
    RECT 15.38 45.055 15.73 45.775 ;
    RECT 16.315 45.055 17.88 45.775 ;
    RECT 19.15 45.055 19.305 45.775 ;
    RECT 19.765 45.055 20.39 45.775 ;
    RECT 20.86 45.055 21.01 45.775 ;
    RECT 21.36 45.055 21.755 45.775 ;
    RECT 22.045 45.055 22.365 45.775 ;
    RECT 22.795 45.055 23.075 45.775 ;
    RECT 23.545 45.055 24.245 45.775 ;
    RECT 24.535 45.055 25.045 45.775 ;
    RECT 25.715 45.055 27.265 45.775 ;
    RECT 27.615 45.055 27.965 45.775 ;
    RECT 28.62 45.055 30.16 45.775 ;
    RECT 30.96 45.055 31.28 45.775 ;
    RECT 31.56 45.055 32.02 45.775 ;
    RECT 32.82 45.055 33.36 45.775 ;
    RECT 33.83 45.055 34.545 45.775 ;
    RECT 34.835 45.055 35.04 45.775 ;
    RECT 36.04 45.055 36.2 45.775 ;
    RECT 36.55 45.055 36.72 45.775 ;
    RECT 37.79 45.055 39.525 45.775 ;
    RECT 40.265 45.055 40.455 45.775 ;
    RECT 40.805 45.055 40.93 45.775 ;
    RECT 14.97 44.335 15.09 45.055 ;
    RECT 15.38 44.335 15.73 45.055 ;
    RECT 16.315 44.335 17.88 45.055 ;
    RECT 19.15 44.335 19.305 45.055 ;
    RECT 19.765 44.335 20.39 45.055 ;
    RECT 20.86 44.335 21.01 45.055 ;
    RECT 21.36 44.335 21.755 45.055 ;
    RECT 22.045 44.335 22.365 45.055 ;
    RECT 22.795 44.335 23.075 45.055 ;
    RECT 23.545 44.335 24.245 45.055 ;
    RECT 24.535 44.335 25.045 45.055 ;
    RECT 25.715 44.335 27.265 45.055 ;
    RECT 27.615 44.335 27.965 45.055 ;
    RECT 28.62 44.335 30.16 45.055 ;
    RECT 30.96 44.335 31.28 45.055 ;
    RECT 31.56 44.335 32.02 45.055 ;
    RECT 32.82 44.335 33.36 45.055 ;
    RECT 33.83 44.335 34.545 45.055 ;
    RECT 34.835 44.335 35.04 45.055 ;
    RECT 36.04 44.335 36.2 45.055 ;
    RECT 36.55 44.335 36.72 45.055 ;
    RECT 37.79 44.335 39.525 45.055 ;
    RECT 40.265 44.335 40.455 45.055 ;
    RECT 40.805 44.335 40.93 45.055 ;
    RECT 14.97 43.615 15.09 44.335 ;
    RECT 15.38 43.615 15.73 44.335 ;
    RECT 16.315 43.615 17.88 44.335 ;
    RECT 19.15 43.615 19.305 44.335 ;
    RECT 19.765 43.615 20.39 44.335 ;
    RECT 20.86 43.615 21.01 44.335 ;
    RECT 21.36 43.615 21.755 44.335 ;
    RECT 22.045 43.615 22.365 44.335 ;
    RECT 22.795 43.615 23.075 44.335 ;
    RECT 23.545 43.615 24.245 44.335 ;
    RECT 24.535 43.615 25.045 44.335 ;
    RECT 25.715 43.615 27.265 44.335 ;
    RECT 27.615 43.615 27.965 44.335 ;
    RECT 28.62 43.615 30.16 44.335 ;
    RECT 30.96 43.615 31.28 44.335 ;
    RECT 31.56 43.615 32.02 44.335 ;
    RECT 32.82 43.615 33.36 44.335 ;
    RECT 33.83 43.615 34.545 44.335 ;
    RECT 34.835 43.615 35.04 44.335 ;
    RECT 36.04 43.615 36.2 44.335 ;
    RECT 36.55 43.615 36.72 44.335 ;
    RECT 37.79 43.615 39.525 44.335 ;
    RECT 40.265 43.615 40.455 44.335 ;
    RECT 40.805 43.615 40.93 44.335 ;
    RECT 14.97 42.895 15.09 43.615 ;
    RECT 15.38 42.895 15.73 43.615 ;
    RECT 16.315 42.895 17.88 43.615 ;
    RECT 19.15 42.895 19.305 43.615 ;
    RECT 19.765 42.895 20.39 43.615 ;
    RECT 20.86 42.895 21.01 43.615 ;
    RECT 21.36 42.895 21.755 43.615 ;
    RECT 22.045 42.895 22.365 43.615 ;
    RECT 22.795 42.895 23.075 43.615 ;
    RECT 23.545 42.895 24.245 43.615 ;
    RECT 24.535 42.895 25.045 43.615 ;
    RECT 25.715 42.895 27.265 43.615 ;
    RECT 27.615 42.895 27.965 43.615 ;
    RECT 28.62 42.895 30.16 43.615 ;
    RECT 30.96 42.895 31.28 43.615 ;
    RECT 31.56 42.895 32.02 43.615 ;
    RECT 32.82 42.895 33.36 43.615 ;
    RECT 33.83 42.895 34.545 43.615 ;
    RECT 34.835 42.895 35.04 43.615 ;
    RECT 36.04 42.895 36.2 43.615 ;
    RECT 36.55 42.895 36.72 43.615 ;
    RECT 37.79 42.895 39.525 43.615 ;
    RECT 40.265 42.895 40.455 43.615 ;
    RECT 40.805 42.895 40.93 43.615 ;
    RECT 14.97 42.175 15.09 42.895 ;
    RECT 15.38 42.175 15.73 42.895 ;
    RECT 16.315 42.175 17.88 42.895 ;
    RECT 19.15 42.175 19.305 42.895 ;
    RECT 19.765 42.175 20.39 42.895 ;
    RECT 20.86 42.175 21.01 42.895 ;
    RECT 21.36 42.175 21.755 42.895 ;
    RECT 22.045 42.175 22.365 42.895 ;
    RECT 22.795 42.175 23.075 42.895 ;
    RECT 23.545 42.175 24.245 42.895 ;
    RECT 24.535 42.175 25.045 42.895 ;
    RECT 25.715 42.175 27.265 42.895 ;
    RECT 27.615 42.175 27.965 42.895 ;
    RECT 28.62 42.175 30.16 42.895 ;
    RECT 30.96 42.175 31.28 42.895 ;
    RECT 31.56 42.175 32.02 42.895 ;
    RECT 32.82 42.175 33.36 42.895 ;
    RECT 33.83 42.175 34.545 42.895 ;
    RECT 34.835 42.175 35.04 42.895 ;
    RECT 36.04 42.175 36.2 42.895 ;
    RECT 36.55 42.175 36.72 42.895 ;
    RECT 37.79 42.175 39.525 42.895 ;
    RECT 40.265 42.175 40.455 42.895 ;
    RECT 40.805 42.175 40.93 42.895 ;
    RECT 14.97 41.455 15.09 42.175 ;
    RECT 15.38 41.455 15.73 42.175 ;
    RECT 16.315 41.455 17.88 42.175 ;
    RECT 19.15 41.455 19.305 42.175 ;
    RECT 19.765 41.455 20.39 42.175 ;
    RECT 20.86 41.455 21.01 42.175 ;
    RECT 21.36 41.455 21.755 42.175 ;
    RECT 22.045 41.455 22.365 42.175 ;
    RECT 22.795 41.455 23.075 42.175 ;
    RECT 23.545 41.455 24.245 42.175 ;
    RECT 24.535 41.455 25.045 42.175 ;
    RECT 25.715 41.455 27.265 42.175 ;
    RECT 27.615 41.455 27.965 42.175 ;
    RECT 28.62 41.455 30.16 42.175 ;
    RECT 30.96 41.455 31.28 42.175 ;
    RECT 31.56 41.455 32.02 42.175 ;
    RECT 32.82 41.455 33.36 42.175 ;
    RECT 33.83 41.455 34.545 42.175 ;
    RECT 34.835 41.455 35.04 42.175 ;
    RECT 36.04 41.455 36.2 42.175 ;
    RECT 36.55 41.455 36.72 42.175 ;
    RECT 37.79 41.455 39.525 42.175 ;
    RECT 40.265 41.455 40.455 42.175 ;
    RECT 40.805 41.455 40.93 42.175 ;
    RECT 14.97 22.735 15.09 34.255 ;
    RECT 15.38 22.735 15.73 34.255 ;
    RECT 16.315 22.735 17.88 34.255 ;
    RECT 19.15 22.735 19.305 34.255 ;
    RECT 19.765 22.735 20.39 34.255 ;
    RECT 20.86 22.735 21.01 34.255 ;
    RECT 21.36 22.735 21.755 34.255 ;
    RECT 22.045 27.45 22.365 34.255 ;
    RECT 22.795 22.735 23.075 34.255 ;
    RECT 23.545 22.735 24.245 34.255 ;
    RECT 24.535 22.735 25.045 34.255 ;
    RECT 25.715 22.735 27.265 34.255 ;
    RECT 27.615 22.735 27.965 34.255 ;
    RECT 28.445 22.735 28.62 33.465 ;
    RECT 28.62 22.735 30.16 34.255 ;
    RECT 30.96 22.735 31.28 34.255 ;
    RECT 31.56 22.735 32.02 34.255 ;
    RECT 32.82 22.735 33.36 34.255 ;
    RECT 33.83 22.735 34.545 34.255 ;
    RECT 34.835 22.735 35.04 34.255 ;
    RECT 36.04 22.735 36.2 34.255 ;
    RECT 36.55 22.735 36.72 34.255 ;
    RECT 37.79 22.735 39.525 34.255 ;
    RECT 40.265 22.735 40.455 34.255 ;
    RECT 40.805 22.735 40.93 34.255 ;
    RECT 14.97 45.775 15.09 47.305 ;
    RECT 15.38 45.775 15.73 46.265 ;
    RECT 16.315 45.775 17.88 47.305 ;
    RECT 19.15 45.775 19.305 47.305 ;
    RECT 19.765 45.775 20.39 47.305 ;
    RECT 20.86 45.775 21.01 47.305 ;
    RECT 21.36 45.775 21.755 47.305 ;
    RECT 22.045 45.775 22.365 47.305 ;
    RECT 22.795 45.775 23.075 47.305 ;
    RECT 23.545 45.775 24.245 47.305 ;
    RECT 24.535 45.775 25.045 47.305 ;
    RECT 25.715 45.775 25.74 47.305 ;
    RECT 25.74 45.75 25.84 47.305 ;
    RECT 25.84 45.775 27.265 47.305 ;
    RECT 27.615 45.775 27.965 47.305 ;
    RECT 28.62 45.775 30.16 47.305 ;
    RECT 30.96 45.775 31.28 47.305 ;
    RECT 31.56 45.775 32.02 47.305 ;
    RECT 32.82 45.775 33.36 47.305 ;
    RECT 33.83 45.775 34.545 47.305 ;
    RECT 34.835 45.775 35.04 47.305 ;
    RECT 36.04 45.775 36.2 47.305 ;
    RECT 36.55 45.775 36.72 47.305 ;
    RECT 37.79 45.775 39.525 47.305 ;
    RECT 40.265 45.775 40.455 47.305 ;
    RECT 40.805 45.775 40.93 47.305 ;
    RECT 54.43 2.85 54.5 14.685 ;
    RECT 54.43 14.94 54.5 20.69 ;
    RECT 54.23 16.505 54.3 18.625 ;
    RECT 52.755 2.135 53.035 20.245 ;
    RECT 44.47 2.85 44.54 14.685 ;
    RECT 44.47 14.94 44.54 20.69 ;
    RECT 44.27 16.505 44.34 18.625 ;
    RECT 42.795 2.135 43.075 20.245 ;
    RECT 51.11 2.85 51.18 14.685 ;
    RECT 51.11 14.94 51.18 20.69 ;
    RECT 50.91 16.505 50.98 18.625 ;
    RECT 49.435 2.135 49.715 20.245 ;
    RECT 47.79 2.85 47.86 14.685 ;
    RECT 47.79 14.94 47.86 20.69 ;
    RECT 47.59 16.505 47.66 18.625 ;
    RECT 46.115 2.135 46.395 20.245 ;
    RECT 50.92 0.695 50.99 1.11 ;
    RECT 49.435 0.695 49.715 2.135 ;
    RECT 47.6 0.695 47.67 1.11 ;
    RECT 46.115 0.695 46.395 2.135 ;
    RECT 54.24 0.695 54.31 1.11 ;
    RECT 52.755 0.695 53.035 2.135 ;
    RECT 44.28 0.695 44.35 1.11 ;
    RECT 42.795 0.695 43.075 2.135 ;
    RECT 14.205 5.885 14.285 22.735 ;
    RECT 14.955 5.885 15.09 22.735 ;
    RECT 15.38 5.885 15.73 22.735 ;
    RECT 16.315 5.885 17.88 22.735 ;
    RECT 19.15 5.885 19.305 22.735 ;
    RECT 19.765 5.885 20.39 22.735 ;
    RECT 20.86 5.885 21.01 22.735 ;
    RECT 21.36 5.885 21.755 22.735 ;
    RECT 22.045 5.885 22.365 14.83 ;
    RECT 22.795 5.885 23.075 22.735 ;
    RECT 23.545 5.885 24.245 22.735 ;
    RECT 24.535 5.885 25.045 22.735 ;
    RECT 25.715 5.885 27.265 22.735 ;
    RECT 27.615 5.885 27.965 22.735 ;
    RECT 28.445 5.885 30.16 22.735 ;
    RECT 30.96 5.885 31.28 22.735 ;
    RECT 31.56 5.885 32.02 22.735 ;
    RECT 32.82 5.885 33.36 22.735 ;
    RECT 33.36 5.885 33.83 6.165 ;
    RECT 33.83 5.885 34.545 22.735 ;
    RECT 34.835 5.885 35.04 22.735 ;
    RECT 36.04 5.885 36.2 22.735 ;
    RECT 36.55 5.885 36.72 22.735 ;
    RECT 37.79 5.885 39.525 22.735 ;
    RECT 40.265 5.885 40.455 22.735 ;
    RECT 40.805 5.885 40.945 22.735 ;
    RECT 41.615 5.885 41.695 22.735 ;
    RECT 14.205 0.695 14.285 5.885 ;
    RECT 14.955 0.695 15.09 5.885 ;
    RECT 15.38 0.695 15.73 5.885 ;
    RECT 16.315 0.695 17.88 5.885 ;
    RECT 19.15 0.695 19.305 5.885 ;
    RECT 19.765 0.695 20.39 5.885 ;
    RECT 20.86 0.695 21.01 5.885 ;
    RECT 21.36 0.695 21.755 5.885 ;
    RECT 22.045 0.695 22.365 5.885 ;
    RECT 22.795 0.695 23.075 5.885 ;
    RECT 23.545 0.695 24.245 5.885 ;
    RECT 24.535 0.695 25.045 5.885 ;
    RECT 25.715 0.695 27.265 5.885 ;
    RECT 27.615 0.695 27.965 5.885 ;
    RECT 28.445 0.695 30.16 5.885 ;
    RECT 30.96 0.695 31.28 5.885 ;
    RECT 31.56 0.695 32.02 5.885 ;
    RECT 32.82 0.695 34.545 5.885 ;
    RECT 34.835 0.695 35.04 5.885 ;
    RECT 36.04 0.695 36.2 5.885 ;
    RECT 36.55 0.695 36.72 5.885 ;
    RECT 37.79 0.695 39.525 5.885 ;
    RECT 40.265 0.695 40.455 5.885 ;
    RECT 40.805 0.695 40.945 5.885 ;
    RECT 41.615 0.695 41.695 5.885 ;
    RECT 8.23 0.695 8.3 1.11 ;
    RECT 9.505 0.695 9.785 2.135 ;
    RECT 4.91 0.695 4.98 1.11 ;
    RECT 6.185 0.695 6.465 2.135 ;
    RECT 11.55 0.695 11.62 1.11 ;
    RECT 12.825 0.695 13.105 2.135 ;
    RECT 1.59 0.695 1.66 1.11 ;
    RECT 2.865 0.695 3.145 2.135 ;
    RECT 1.4 2.85 1.47 14.685 ;
    RECT 1.4 14.94 1.47 20.69 ;
    RECT 1.6 16.505 1.67 18.625 ;
    RECT 2.865 2.135 3.145 20.245 ;
    RECT 8.04 2.85 8.11 14.685 ;
    RECT 8.04 14.94 8.11 20.69 ;
    RECT 8.24 16.505 8.31 18.625 ;
    RECT 9.505 2.135 9.785 20.245 ;
    RECT 4.72 2.85 4.79 14.685 ;
    RECT 4.72 14.94 4.79 20.69 ;
    RECT 4.92 16.505 4.99 18.625 ;
    RECT 6.185 2.135 6.465 20.245 ;
    RECT 11.36 2.85 11.43 14.685 ;
    RECT 11.36 14.94 11.43 20.69 ;
    RECT 11.56 16.505 11.63 18.625 ;
    RECT 12.825 2.135 13.105 20.245 ;
    RECT 14.205 47.305 14.285 47.89 ;
    RECT 14.955 47.305 15.09 47.89 ;
    RECT 15.38 47.695 15.73 47.89 ;
    RECT 16.315 47.305 17.88 47.89 ;
    RECT 19.15 47.305 19.305 47.89 ;
    RECT 19.765 47.305 20.39 47.89 ;
    RECT 20.86 47.305 21.01 47.89 ;
    RECT 21.36 47.305 21.755 47.89 ;
    RECT 22.045 47.305 22.365 47.89 ;
    RECT 22.795 47.305 23.075 47.89 ;
    RECT 23.545 47.305 24.245 47.89 ;
    RECT 24.535 47.305 25.045 47.89 ;
    RECT 25.715 47.305 27.265 47.89 ;
    RECT 27.615 47.305 27.965 47.89 ;
    RECT 28.445 47.305 30.16 47.89 ;
    RECT 30.96 47.305 31.28 47.89 ;
    RECT 31.56 47.305 32.02 47.89 ;
    RECT 32.82 47.305 33.36 47.89 ;
    RECT 33.83 47.305 34.545 47.89 ;
    RECT 34.835 47.305 35.04 47.89 ;
    RECT 36.04 47.305 36.2 47.89 ;
    RECT 36.55 47.305 36.72 47.89 ;
    RECT 37.79 47.305 39.525 47.89 ;
    RECT 40.265 47.305 40.455 47.89 ;
    RECT 40.805 47.305 40.945 47.89 ;
    RECT 41.615 47.305 41.695 47.89 ;
    #obstructions of filtered out pwrgnd shapes
    RECT 44.205 44.975 44.485 45.855 ;
    RECT 54.165 44.975 54.445 45.855 ;
    RECT 50.845 44.975 51.125 45.855 ;
    RECT 47.525 44.975 47.805 45.855 ;
    RECT 44.205 34.175 44.485 35.055 ;
    RECT 54.165 34.175 54.445 35.055 ;
    RECT 50.845 34.175 51.125 35.055 ;
    RECT 47.525 34.175 47.805 35.055 ;
    RECT 44.205 44.255 44.485 45.135 ;
    RECT 54.165 44.255 54.445 45.135 ;
    RECT 50.845 44.255 51.125 45.135 ;
    RECT 47.525 44.255 47.805 45.135 ;
    RECT 54.165 45.775 54.445 47.305 ;
    RECT 50.845 45.775 51.125 47.305 ;
    RECT 47.525 45.775 47.805 47.305 ;
    RECT 44.205 45.775 44.485 47.305 ;
    RECT 44.205 32.735 44.485 33.615 ;
    RECT 54.165 32.735 54.445 33.615 ;
    RECT 50.845 32.735 51.125 33.615 ;
    RECT 47.525 32.735 47.805 33.615 ;
    RECT 44.205 43.535 44.485 44.415 ;
    RECT 54.165 43.535 54.445 44.415 ;
    RECT 50.845 43.535 51.125 44.415 ;
    RECT 47.525 43.535 47.805 44.415 ;
    RECT 44.205 42.815 44.485 43.695 ;
    RECT 54.165 42.815 54.445 43.695 ;
    RECT 50.845 42.815 51.125 43.695 ;
    RECT 47.525 42.815 47.805 43.695 ;
    RECT 44.205 42.095 44.485 42.975 ;
    RECT 54.165 42.095 54.445 42.975 ;
    RECT 50.845 42.095 51.125 42.975 ;
    RECT 47.525 42.095 47.805 42.975 ;
    RECT 44.205 41.375 44.485 42.255 ;
    RECT 54.165 41.375 54.445 42.255 ;
    RECT 50.845 41.375 51.125 42.255 ;
    RECT 47.525 41.375 47.805 42.255 ;
    RECT 44.205 40.655 44.485 41.535 ;
    RECT 54.165 40.655 54.445 41.535 ;
    RECT 50.845 40.655 51.125 41.535 ;
    RECT 47.525 40.655 47.805 41.535 ;
    RECT 44.205 39.935 44.485 40.815 ;
    RECT 54.165 39.935 54.445 40.815 ;
    RECT 50.845 39.935 51.125 40.815 ;
    RECT 47.525 39.935 47.805 40.815 ;
    RECT 44.205 39.215 44.485 40.095 ;
    RECT 54.165 39.215 54.445 40.095 ;
    RECT 50.845 39.215 51.125 40.095 ;
    RECT 47.525 39.215 47.805 40.095 ;
    RECT 44.205 38.495 44.485 39.375 ;
    RECT 54.165 38.495 54.445 39.375 ;
    RECT 50.845 38.495 51.125 39.375 ;
    RECT 47.525 38.495 47.805 39.375 ;
    RECT 44.205 37.775 44.485 38.655 ;
    RECT 54.165 37.775 54.445 38.655 ;
    RECT 50.845 37.775 51.125 38.655 ;
    RECT 47.525 37.775 47.805 38.655 ;
    RECT 44.205 37.055 44.485 37.935 ;
    RECT 54.165 37.055 54.445 37.935 ;
    RECT 50.845 37.055 51.125 37.935 ;
    RECT 47.525 37.055 47.805 37.935 ;
    RECT 44.205 29.135 44.485 30.015 ;
    RECT 54.165 29.135 54.445 30.015 ;
    RECT 50.845 29.135 51.125 30.015 ;
    RECT 47.525 29.135 47.805 30.015 ;
    RECT 44.205 28.415 44.485 29.295 ;
    RECT 54.165 28.415 54.445 29.295 ;
    RECT 50.845 28.415 51.125 29.295 ;
    RECT 47.525 28.415 47.805 29.295 ;
    RECT 44.205 27.695 44.485 28.575 ;
    RECT 54.165 27.695 54.445 28.575 ;
    RECT 50.845 27.695 51.125 28.575 ;
    RECT 47.525 27.695 47.805 28.575 ;
    RECT 44.205 26.975 44.485 27.855 ;
    RECT 54.165 26.975 54.445 27.855 ;
    RECT 50.845 26.975 51.125 27.855 ;
    RECT 47.525 26.975 47.805 27.855 ;
    RECT 44.205 26.255 44.485 27.135 ;
    RECT 54.165 26.255 54.445 27.135 ;
    RECT 50.845 26.255 51.125 27.135 ;
    RECT 47.525 26.255 47.805 27.135 ;
    RECT 44.205 25.535 44.485 26.415 ;
    RECT 54.165 25.535 54.445 26.415 ;
    RECT 50.845 25.535 51.125 26.415 ;
    RECT 47.525 25.535 47.805 26.415 ;
    RECT 44.205 33.455 44.485 34.335 ;
    RECT 54.165 33.455 54.445 34.335 ;
    RECT 50.845 33.455 51.125 34.335 ;
    RECT 47.525 33.455 47.805 34.335 ;
    RECT 44.205 24.815 44.485 25.695 ;
    RECT 54.165 24.815 54.445 25.695 ;
    RECT 50.845 24.815 51.125 25.695 ;
    RECT 47.525 24.815 47.805 25.695 ;
    RECT 44.205 24.095 44.485 24.975 ;
    RECT 54.165 24.095 54.445 24.975 ;
    RECT 50.845 24.095 51.125 24.975 ;
    RECT 47.525 24.095 47.805 24.975 ;
    RECT 44.205 23.375 44.485 24.255 ;
    RECT 54.165 23.375 54.445 24.255 ;
    RECT 50.845 23.375 51.125 24.255 ;
    RECT 47.525 23.375 47.805 24.255 ;
    RECT 44.205 36.335 44.485 37.215 ;
    RECT 54.165 36.335 54.445 37.215 ;
    RECT 50.845 36.335 51.125 37.215 ;
    RECT 47.525 36.335 47.805 37.215 ;
    RECT 44.205 35.615 44.485 36.495 ;
    RECT 54.165 35.615 54.445 36.495 ;
    RECT 50.845 35.615 51.125 36.495 ;
    RECT 47.525 35.615 47.805 36.495 ;
    RECT 44.205 34.895 44.485 35.775 ;
    RECT 54.165 34.895 54.445 35.775 ;
    RECT 50.845 34.895 51.125 35.775 ;
    RECT 47.525 34.895 47.805 35.775 ;
    RECT 44.205 32.015 44.485 32.895 ;
    RECT 54.165 32.015 54.445 32.895 ;
    RECT 50.845 32.015 51.125 32.895 ;
    RECT 47.525 32.015 47.805 32.895 ;
    RECT 44.205 31.295 44.485 32.175 ;
    RECT 54.165 31.295 54.445 32.175 ;
    RECT 50.845 31.295 51.125 32.175 ;
    RECT 47.525 31.295 47.805 32.175 ;
    RECT 54.165 22.655 54.445 23.535 ;
    RECT 44.205 22.655 44.485 23.535 ;
    RECT 50.845 22.655 51.125 23.535 ;
    RECT 47.525 22.655 47.805 23.535 ;
    RECT 44.205 30.575 44.485 31.455 ;
    RECT 54.165 30.575 54.445 31.455 ;
    RECT 50.845 30.575 51.125 31.455 ;
    RECT 47.525 30.575 47.805 31.455 ;
    RECT 44.205 29.855 44.485 30.735 ;
    RECT 54.165 29.855 54.445 30.735 ;
    RECT 50.845 29.855 51.125 30.735 ;
    RECT 47.525 29.855 47.805 30.735 ;
    RECT 1.455 44.975 1.735 45.855 ;
    RECT 11.415 44.975 11.695 45.855 ;
    RECT 8.095 44.975 8.375 45.855 ;
    RECT 4.775 44.975 5.055 45.855 ;
    RECT 1.455 34.175 1.735 35.055 ;
    RECT 11.415 34.175 11.695 35.055 ;
    RECT 8.095 34.175 8.375 35.055 ;
    RECT 4.775 34.175 5.055 35.055 ;
    RECT 1.455 36.335 1.735 37.215 ;
    RECT 11.415 36.335 11.695 37.215 ;
    RECT 8.095 36.335 8.375 37.215 ;
    RECT 4.775 36.335 5.055 37.215 ;
    RECT 1.455 35.615 1.735 36.495 ;
    RECT 11.415 35.615 11.695 36.495 ;
    RECT 8.095 35.615 8.375 36.495 ;
    RECT 4.775 35.615 5.055 36.495 ;
    RECT 1.455 34.895 1.735 35.775 ;
    RECT 11.415 34.895 11.695 35.775 ;
    RECT 8.095 34.895 8.375 35.775 ;
    RECT 4.775 34.895 5.055 35.775 ;
    RECT 1.455 32.015 1.735 32.895 ;
    RECT 11.415 32.015 11.695 32.895 ;
    RECT 8.095 32.015 8.375 32.895 ;
    RECT 4.775 32.015 5.055 32.895 ;
    RECT 1.455 31.295 1.735 32.175 ;
    RECT 11.415 31.295 11.695 32.175 ;
    RECT 8.095 31.295 8.375 32.175 ;
    RECT 4.775 31.295 5.055 32.175 ;
    RECT 1.455 30.575 1.735 31.455 ;
    RECT 11.415 30.575 11.695 31.455 ;
    RECT 8.095 30.575 8.375 31.455 ;
    RECT 4.775 30.575 5.055 31.455 ;
    RECT 1.455 29.855 1.735 30.735 ;
    RECT 11.415 29.855 11.695 30.735 ;
    RECT 8.095 29.855 8.375 30.735 ;
    RECT 4.775 29.855 5.055 30.735 ;
    RECT 1.455 32.735 1.735 33.615 ;
    RECT 11.415 32.735 11.695 33.615 ;
    RECT 8.095 32.735 8.375 33.615 ;
    RECT 4.775 32.735 5.055 33.615 ;
    RECT 11.415 45.775 11.695 47.305 ;
    RECT 8.095 45.775 8.375 47.305 ;
    RECT 4.775 45.775 5.055 47.305 ;
    RECT 1.455 45.775 1.735 47.305 ;
    RECT 1.455 44.255 1.735 45.135 ;
    RECT 11.415 44.255 11.695 45.135 ;
    RECT 8.095 44.255 8.375 45.135 ;
    RECT 4.775 44.255 5.055 45.135 ;
    RECT 1.455 33.455 1.735 34.335 ;
    RECT 11.415 33.455 11.695 34.335 ;
    RECT 8.095 33.455 8.375 34.335 ;
    RECT 4.775 33.455 5.055 34.335 ;
    RECT 1.455 43.535 1.735 44.415 ;
    RECT 11.415 43.535 11.695 44.415 ;
    RECT 8.095 43.535 8.375 44.415 ;
    RECT 4.775 43.535 5.055 44.415 ;
    RECT 1.455 42.815 1.735 43.695 ;
    RECT 11.415 42.815 11.695 43.695 ;
    RECT 8.095 42.815 8.375 43.695 ;
    RECT 4.775 42.815 5.055 43.695 ;
    RECT 1.455 42.095 1.735 42.975 ;
    RECT 11.415 42.095 11.695 42.975 ;
    RECT 8.095 42.095 8.375 42.975 ;
    RECT 4.775 42.095 5.055 42.975 ;
    RECT 1.455 41.375 1.735 42.255 ;
    RECT 11.415 41.375 11.695 42.255 ;
    RECT 8.095 41.375 8.375 42.255 ;
    RECT 4.775 41.375 5.055 42.255 ;
    RECT 1.455 40.655 1.735 41.535 ;
    RECT 11.415 40.655 11.695 41.535 ;
    RECT 8.095 40.655 8.375 41.535 ;
    RECT 4.775 40.655 5.055 41.535 ;
    RECT 1.455 39.935 1.735 40.815 ;
    RECT 11.415 39.935 11.695 40.815 ;
    RECT 8.095 39.935 8.375 40.815 ;
    RECT 4.775 39.935 5.055 40.815 ;
    RECT 1.455 29.135 1.735 30.015 ;
    RECT 11.415 29.135 11.695 30.015 ;
    RECT 8.095 29.135 8.375 30.015 ;
    RECT 4.775 29.135 5.055 30.015 ;
    RECT 1.455 39.215 1.735 40.095 ;
    RECT 11.415 39.215 11.695 40.095 ;
    RECT 8.095 39.215 8.375 40.095 ;
    RECT 4.775 39.215 5.055 40.095 ;
    RECT 1.455 28.415 1.735 29.295 ;
    RECT 11.415 28.415 11.695 29.295 ;
    RECT 8.095 28.415 8.375 29.295 ;
    RECT 4.775 28.415 5.055 29.295 ;
    RECT 1.455 38.495 1.735 39.375 ;
    RECT 11.415 38.495 11.695 39.375 ;
    RECT 8.095 38.495 8.375 39.375 ;
    RECT 4.775 38.495 5.055 39.375 ;
    RECT 1.455 27.695 1.735 28.575 ;
    RECT 11.415 27.695 11.695 28.575 ;
    RECT 8.095 27.695 8.375 28.575 ;
    RECT 4.775 27.695 5.055 28.575 ;
    RECT 1.455 37.775 1.735 38.655 ;
    RECT 11.415 37.775 11.695 38.655 ;
    RECT 8.095 37.775 8.375 38.655 ;
    RECT 4.775 37.775 5.055 38.655 ;
    RECT 1.455 26.975 1.735 27.855 ;
    RECT 11.415 26.975 11.695 27.855 ;
    RECT 8.095 26.975 8.375 27.855 ;
    RECT 4.775 26.975 5.055 27.855 ;
    RECT 1.455 37.055 1.735 37.935 ;
    RECT 11.415 37.055 11.695 37.935 ;
    RECT 8.095 37.055 8.375 37.935 ;
    RECT 4.775 37.055 5.055 37.935 ;
    RECT 1.455 26.255 1.735 27.135 ;
    RECT 11.415 26.255 11.695 27.135 ;
    RECT 8.095 26.255 8.375 27.135 ;
    RECT 4.775 26.255 5.055 27.135 ;
    RECT 1.455 25.535 1.735 26.415 ;
    RECT 11.415 25.535 11.695 26.415 ;
    RECT 8.095 25.535 8.375 26.415 ;
    RECT 4.775 25.535 5.055 26.415 ;
    RECT 1.455 24.815 1.735 25.695 ;
    RECT 11.415 24.815 11.695 25.695 ;
    RECT 8.095 24.815 8.375 25.695 ;
    RECT 4.775 24.815 5.055 25.695 ;
    RECT 1.455 24.095 1.735 24.975 ;
    RECT 11.415 24.095 11.695 24.975 ;
    RECT 8.095 24.095 8.375 24.975 ;
    RECT 4.775 24.095 5.055 24.975 ;
    RECT 1.455 23.375 1.735 24.255 ;
    RECT 11.415 23.375 11.695 24.255 ;
    RECT 8.095 23.375 8.375 24.255 ;
    RECT 4.775 23.375 5.055 24.255 ;
    RECT 11.415 22.655 11.695 23.535 ;
    RECT 1.455 22.655 1.735 23.535 ;
    RECT 8.095 22.655 8.375 23.535 ;
    RECT 4.775 22.655 5.055 23.535 ;
    RECT 28.47 40.735 28.55 41.455 ;
    RECT 33.46 40.735 33.73 41.455 ;
    RECT 28.47 40.015 28.55 40.735 ;
    RECT 33.46 40.015 33.73 40.735 ;
    RECT 28.47 39.295 28.55 40.015 ;
    RECT 33.46 39.295 33.73 40.015 ;
    RECT 28.47 38.575 28.55 39.295 ;
    RECT 33.46 38.575 33.73 39.295 ;
    RECT 28.47 37.855 28.55 38.575 ;
    RECT 33.46 37.855 33.73 38.575 ;
    RECT 28.47 37.135 28.55 37.855 ;
    RECT 33.46 37.135 33.73 37.855 ;
    RECT 28.47 36.415 28.55 37.135 ;
    RECT 33.46 36.415 33.73 37.135 ;
    RECT 28.47 35.695 28.55 36.415 ;
    RECT 33.46 35.695 33.73 36.415 ;
    RECT 28.47 34.975 28.55 35.695 ;
    RECT 33.46 34.975 33.73 35.695 ;
    RECT 28.47 34.255 28.55 34.975 ;
    RECT 33.46 34.255 33.73 34.975 ;
    RECT 28.47 45.055 28.55 45.775 ;
    RECT 33.46 45.055 33.73 45.775 ;
    RECT 28.47 44.335 28.55 45.055 ;
    RECT 33.46 44.335 33.73 45.055 ;
    RECT 28.47 43.615 28.55 44.335 ;
    RECT 33.46 43.615 33.73 44.335 ;
    RECT 28.47 42.895 28.55 43.615 ;
    RECT 33.46 42.895 33.73 43.615 ;
    RECT 28.47 42.175 28.55 42.895 ;
    RECT 33.46 42.175 33.73 42.895 ;
    RECT 28.47 41.455 28.55 42.175 ;
    RECT 33.46 41.455 33.73 42.175 ;
    RECT 22.095 22.735 22.305 27.38 ;
    RECT 28.465 25.51 28.47 25.72 ;
    RECT 28.47 22.78 28.55 34.255 ;
    RECT 33.46 22.615 33.73 34.255 ;
    RECT 15.43 46.335 15.62 47.305 ;
    RECT 28.47 45.775 28.55 47.28 ;
    RECT 33.46 45.775 33.73 47.305 ;
    RECT 54.165 20.95 54.445 21.245 ;
    RECT 54.225 10.91 54.295 15.505 ;
    RECT 44.205 20.95 44.485 21.245 ;
    RECT 44.265 10.91 44.335 15.505 ;
    RECT 50.845 20.95 51.125 21.245 ;
    RECT 50.905 10.91 50.975 15.505 ;
    RECT 47.525 20.95 47.805 21.245 ;
    RECT 47.585 10.91 47.655 15.505 ;
    RECT 54.165 21.205 54.445 22.735 ;
    RECT 50.845 21.205 51.125 22.735 ;
    RECT 47.525 21.205 47.805 22.735 ;
    RECT 44.205 21.205 44.485 22.735 ;
    RECT 22.095 14.9 22.305 22.735 ;
    RECT 32.24 12.435 32.34 12.565 ;
    RECT 33.46 6.265 33.73 22.735 ;
    RECT 37.28 9.0 37.315 9.13 ;
    RECT 37.28 10.645 37.315 10.775 ;
    RECT 11.415 21.205 11.695 22.735 ;
    RECT 8.095 21.205 8.375 22.735 ;
    RECT 4.775 21.205 5.055 22.735 ;
    RECT 1.455 21.205 1.735 22.735 ;
    RECT 1.455 20.95 1.735 21.245 ;
    RECT 1.605 10.91 1.675 15.505 ;
    RECT 8.095 20.95 8.375 21.245 ;
    RECT 8.245 10.91 8.315 15.505 ;
    RECT 4.775 20.95 5.055 21.245 ;
    RECT 4.925 10.91 4.995 15.505 ;
    RECT 11.415 20.95 11.695 21.245 ;
    RECT 11.565 10.91 11.635 15.505 ;
    RECT 11.415 47.305 11.695 47.82 ;
    RECT 8.095 47.305 8.375 47.82 ;
    RECT 4.775 47.305 5.055 47.82 ;
    RECT 1.455 47.305 1.735 47.82 ;
    RECT 15.43 47.305 15.62 47.625 ;
    RECT 33.46 47.305 33.73 47.82 ;
    RECT 54.165 47.305 54.445 47.82 ;
    RECT 50.845 47.305 51.125 47.82 ;
    RECT 47.525 47.305 47.805 47.82 ;
    RECT 44.205 47.305 44.485 47.82 ;
    END
  END RAMSP128X16

END LIBRARY

